VERSION 5.8 ;
BUSBITCHARS "[]" ;
DIVIDERCHAR "/" ;
UNITS
    DATABASE MICRONS 1000 ;
END UNITS

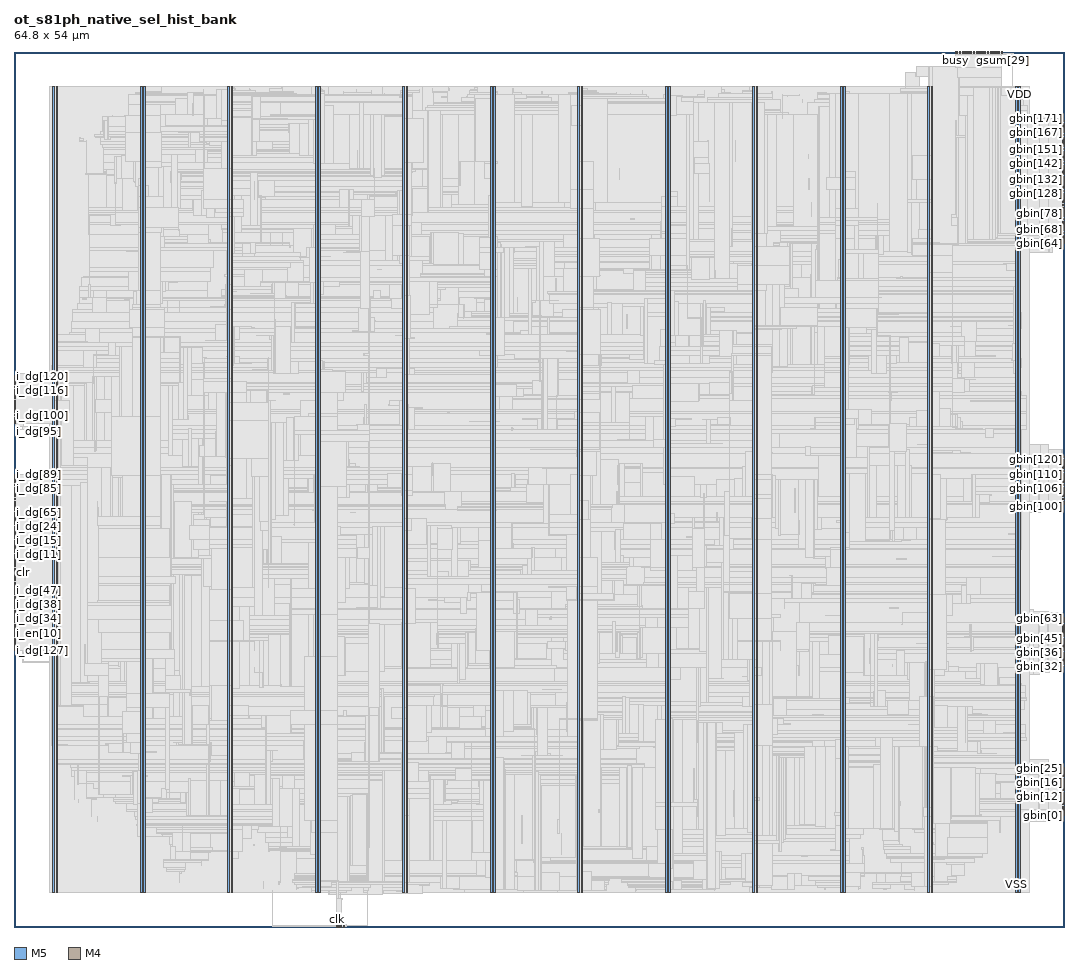
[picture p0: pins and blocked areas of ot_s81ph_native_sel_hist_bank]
MACRO ot_s81ph_native_sel_hist_bank
  FOREIGN ot_s81ph_native_sel_hist_bank 0 0 ;
  CLASS BLOCK ;
  SIZE 64.8 BY 54 ;
  PIN busy
    DIRECTION OUTPUT ;
    USE SIGNAL ;
    PORT
      LAYER M5 ;
        RECT  58.128 53.916 58.152 54 ;
    END
  END busy
  PIN clk
    DIRECTION INPUT ;
    USE SIGNAL ;
    PORT
      LAYER M5 ;
        RECT  19.92 0 19.944 0.084 ;
    END
  END clk
  PIN clr
    DIRECTION INPUT ;
    USE SIGNAL ;
    PORT
      LAYER M4 ;
        RECT  0 21.84 0.084 21.864 ;
    END
  END clr
  PIN gbin[0]
    DIRECTION OUTPUT ;
    USE SIGNAL ;
    PORT
      LAYER M4 ;
        RECT  64.716 6.864 64.8 6.888 ;
    END
  END gbin[0]
  PIN gbin[100]
    DIRECTION OUTPUT ;
    USE SIGNAL ;
    PORT
      LAYER M4 ;
        RECT  64.716 26.448 64.8 26.472 ;
    END
  END gbin[100]
  PIN gbin[101]
    DIRECTION OUTPUT ;
    USE SIGNAL ;
    PORT
      LAYER M4 ;
        RECT  64.716 26.544 64.8 26.568 ;
    END
  END gbin[101]
  PIN gbin[102]
    DIRECTION OUTPUT ;
    USE SIGNAL ;
    PORT
      LAYER M4 ;
        RECT  64.716 26.64 64.8 26.664 ;
    END
  END gbin[102]
  PIN gbin[103]
    DIRECTION OUTPUT ;
    USE SIGNAL ;
    PORT
      LAYER M4 ;
        RECT  64.716 26.736 64.8 26.76 ;
    END
  END gbin[103]
  PIN gbin[104]
    DIRECTION OUTPUT ;
    USE SIGNAL ;
    PORT
      LAYER M4 ;
        RECT  64.716 26.832 64.8 26.856 ;
    END
  END gbin[104]
  PIN gbin[105]
    DIRECTION OUTPUT ;
    USE SIGNAL ;
    PORT
      LAYER M4 ;
        RECT  64.716 26.928 64.8 26.952 ;
    END
  END gbin[105]
  PIN gbin[106]
    DIRECTION OUTPUT ;
    USE SIGNAL ;
    PORT
      LAYER M4 ;
        RECT  64.716 27.024 64.8 27.048 ;
    END
  END gbin[106]
  PIN gbin[107]
    DIRECTION OUTPUT ;
    USE SIGNAL ;
    PORT
      LAYER M4 ;
        RECT  64.716 27.12 64.8 27.144 ;
    END
  END gbin[107]
  PIN gbin[108]
    DIRECTION OUTPUT ;
    USE SIGNAL ;
    PORT
      LAYER M4 ;
        RECT  64.716 27.216 64.8 27.24 ;
    END
  END gbin[108]
  PIN gbin[109]
    DIRECTION OUTPUT ;
    USE SIGNAL ;
    PORT
      LAYER M4 ;
        RECT  64.716 27.312 64.8 27.336 ;
    END
  END gbin[109]
  PIN gbin[10]
    DIRECTION OUTPUT ;
    USE SIGNAL ;
    PORT
      LAYER M4 ;
        RECT  64.716 7.824 64.8 7.848 ;
    END
  END gbin[10]
  PIN gbin[110]
    DIRECTION OUTPUT ;
    USE SIGNAL ;
    PORT
      LAYER M4 ;
        RECT  64.716 27.408 64.8 27.432 ;
    END
  END gbin[110]
  PIN gbin[111]
    DIRECTION OUTPUT ;
    USE SIGNAL ;
    PORT
      LAYER M4 ;
        RECT  64.716 27.504 64.8 27.528 ;
    END
  END gbin[111]
  PIN gbin[112]
    DIRECTION OUTPUT ;
    USE SIGNAL ;
    PORT
      LAYER M4 ;
        RECT  64.716 27.6 64.8 27.624 ;
    END
  END gbin[112]
  PIN gbin[113]
    DIRECTION OUTPUT ;
    USE SIGNAL ;
    PORT
      LAYER M4 ;
        RECT  64.716 27.696 64.8 27.72 ;
    END
  END gbin[113]
  PIN gbin[114]
    DIRECTION OUTPUT ;
    USE SIGNAL ;
    PORT
      LAYER M4 ;
        RECT  64.716 27.792 64.8 27.816 ;
    END
  END gbin[114]
  PIN gbin[115]
    DIRECTION OUTPUT ;
    USE SIGNAL ;
    PORT
      LAYER M4 ;
        RECT  64.716 27.888 64.8 27.912 ;
    END
  END gbin[115]
  PIN gbin[116]
    DIRECTION OUTPUT ;
    USE SIGNAL ;
    PORT
      LAYER M4 ;
        RECT  64.716 27.984 64.8 28.008 ;
    END
  END gbin[116]
  PIN gbin[117]
    DIRECTION OUTPUT ;
    USE SIGNAL ;
    PORT
      LAYER M4 ;
        RECT  64.716 28.08 64.8 28.104 ;
    END
  END gbin[117]
  PIN gbin[118]
    DIRECTION OUTPUT ;
    USE SIGNAL ;
    PORT
      LAYER M4 ;
        RECT  64.716 28.176 64.8 28.2 ;
    END
  END gbin[118]
  PIN gbin[119]
    DIRECTION OUTPUT ;
    USE SIGNAL ;
    PORT
      LAYER M4 ;
        RECT  64.716 28.272 64.8 28.296 ;
    END
  END gbin[119]
  PIN gbin[11]
    DIRECTION OUTPUT ;
    USE SIGNAL ;
    PORT
      LAYER M4 ;
        RECT  64.716 7.92 64.8 7.944 ;
    END
  END gbin[11]
  PIN gbin[120]
    DIRECTION OUTPUT ;
    USE SIGNAL ;
    PORT
      LAYER M4 ;
        RECT  64.716 28.368 64.8 28.392 ;
    END
  END gbin[120]
  PIN gbin[121]
    DIRECTION OUTPUT ;
    USE SIGNAL ;
    PORT
      LAYER M4 ;
        RECT  64.716 28.464 64.8 28.488 ;
    END
  END gbin[121]
  PIN gbin[122]
    DIRECTION OUTPUT ;
    USE SIGNAL ;
    PORT
      LAYER M4 ;
        RECT  64.716 28.56 64.8 28.584 ;
    END
  END gbin[122]
  PIN gbin[123]
    DIRECTION OUTPUT ;
    USE SIGNAL ;
    PORT
      LAYER M4 ;
        RECT  64.716 28.656 64.8 28.68 ;
    END
  END gbin[123]
  PIN gbin[124]
    DIRECTION OUTPUT ;
    USE SIGNAL ;
    PORT
      LAYER M4 ;
        RECT  64.716 28.752 64.8 28.776 ;
    END
  END gbin[124]
  PIN gbin[125]
    DIRECTION OUTPUT ;
    USE SIGNAL ;
    PORT
      LAYER M4 ;
        RECT  64.716 28.848 64.8 28.872 ;
    END
  END gbin[125]
  PIN gbin[126]
    DIRECTION OUTPUT ;
    USE SIGNAL ;
    PORT
      LAYER M4 ;
        RECT  64.716 28.944 64.8 28.968 ;
    END
  END gbin[126]
  PIN gbin[127]
    DIRECTION OUTPUT ;
    USE SIGNAL ;
    PORT
      LAYER M4 ;
        RECT  64.716 29.04 64.8 29.064 ;
    END
  END gbin[127]
  PIN gbin[128]
    DIRECTION OUTPUT ;
    USE SIGNAL ;
    PORT
      LAYER M4 ;
        RECT  64.716 45.264 64.8 45.288 ;
    END
  END gbin[128]
  PIN gbin[129]
    DIRECTION OUTPUT ;
    USE SIGNAL ;
    PORT
      LAYER M4 ;
        RECT  64.716 45.36 64.8 45.384 ;
    END
  END gbin[129]
  PIN gbin[12]
    DIRECTION OUTPUT ;
    USE SIGNAL ;
    PORT
      LAYER M4 ;
        RECT  64.716 8.016 64.8 8.04 ;
    END
  END gbin[12]
  PIN gbin[130]
    DIRECTION OUTPUT ;
    USE SIGNAL ;
    PORT
      LAYER M4 ;
        RECT  64.716 45.456 64.8 45.48 ;
    END
  END gbin[130]
  PIN gbin[131]
    DIRECTION OUTPUT ;
    USE SIGNAL ;
    PORT
      LAYER M4 ;
        RECT  64.716 45.552 64.8 45.576 ;
    END
  END gbin[131]
  PIN gbin[132]
    DIRECTION OUTPUT ;
    USE SIGNAL ;
    PORT
      LAYER M4 ;
        RECT  64.716 45.648 64.8 45.672 ;
    END
  END gbin[132]
  PIN gbin[133]
    DIRECTION OUTPUT ;
    USE SIGNAL ;
    PORT
      LAYER M4 ;
        RECT  64.716 45.744 64.8 45.768 ;
    END
  END gbin[133]
  PIN gbin[134]
    DIRECTION OUTPUT ;
    USE SIGNAL ;
    PORT
      LAYER M4 ;
        RECT  64.716 45.84 64.8 45.864 ;
    END
  END gbin[134]
  PIN gbin[135]
    DIRECTION OUTPUT ;
    USE SIGNAL ;
    PORT
      LAYER M4 ;
        RECT  64.716 45.936 64.8 45.96 ;
    END
  END gbin[135]
  PIN gbin[136]
    DIRECTION OUTPUT ;
    USE SIGNAL ;
    PORT
      LAYER M4 ;
        RECT  64.716 46.032 64.8 46.056 ;
    END
  END gbin[136]
  PIN gbin[137]
    DIRECTION OUTPUT ;
    USE SIGNAL ;
    PORT
      LAYER M4 ;
        RECT  64.716 46.128 64.8 46.152 ;
    END
  END gbin[137]
  PIN gbin[138]
    DIRECTION OUTPUT ;
    USE SIGNAL ;
    PORT
      LAYER M4 ;
        RECT  64.716 46.224 64.8 46.248 ;
    END
  END gbin[138]
  PIN gbin[139]
    DIRECTION OUTPUT ;
    USE SIGNAL ;
    PORT
      LAYER M4 ;
        RECT  64.716 46.32 64.8 46.344 ;
    END
  END gbin[139]
  PIN gbin[13]
    DIRECTION OUTPUT ;
    USE SIGNAL ;
    PORT
      LAYER M4 ;
        RECT  64.716 8.112 64.8 8.136 ;
    END
  END gbin[13]
  PIN gbin[140]
    DIRECTION OUTPUT ;
    USE SIGNAL ;
    PORT
      LAYER M4 ;
        RECT  64.716 46.416 64.8 46.44 ;
    END
  END gbin[140]
  PIN gbin[141]
    DIRECTION OUTPUT ;
    USE SIGNAL ;
    PORT
      LAYER M4 ;
        RECT  64.716 46.512 64.8 46.536 ;
    END
  END gbin[141]
  PIN gbin[142]
    DIRECTION OUTPUT ;
    USE SIGNAL ;
    PORT
      LAYER M4 ;
        RECT  64.716 46.608 64.8 46.632 ;
    END
  END gbin[142]
  PIN gbin[143]
    DIRECTION OUTPUT ;
    USE SIGNAL ;
    PORT
      LAYER M4 ;
        RECT  64.716 46.704 64.8 46.728 ;
    END
  END gbin[143]
  PIN gbin[144]
    DIRECTION OUTPUT ;
    USE SIGNAL ;
    PORT
      LAYER M4 ;
        RECT  64.716 46.8 64.8 46.824 ;
    END
  END gbin[144]
  PIN gbin[145]
    DIRECTION OUTPUT ;
    USE SIGNAL ;
    PORT
      LAYER M4 ;
        RECT  64.716 46.896 64.8 46.92 ;
    END
  END gbin[145]
  PIN gbin[146]
    DIRECTION OUTPUT ;
    USE SIGNAL ;
    PORT
      LAYER M4 ;
        RECT  64.716 46.992 64.8 47.016 ;
    END
  END gbin[146]
  PIN gbin[147]
    DIRECTION OUTPUT ;
    USE SIGNAL ;
    PORT
      LAYER M4 ;
        RECT  64.716 47.088 64.8 47.112 ;
    END
  END gbin[147]
  PIN gbin[148]
    DIRECTION OUTPUT ;
    USE SIGNAL ;
    PORT
      LAYER M4 ;
        RECT  64.716 47.184 64.8 47.208 ;
    END
  END gbin[148]
  PIN gbin[149]
    DIRECTION OUTPUT ;
    USE SIGNAL ;
    PORT
      LAYER M4 ;
        RECT  64.716 47.28 64.8 47.304 ;
    END
  END gbin[149]
  PIN gbin[14]
    DIRECTION OUTPUT ;
    USE SIGNAL ;
    PORT
      LAYER M4 ;
        RECT  64.716 8.208 64.8 8.232 ;
    END
  END gbin[14]
  PIN gbin[150]
    DIRECTION OUTPUT ;
    USE SIGNAL ;
    PORT
      LAYER M4 ;
        RECT  64.716 47.376 64.8 47.4 ;
    END
  END gbin[150]
  PIN gbin[151]
    DIRECTION OUTPUT ;
    USE SIGNAL ;
    PORT
      LAYER M4 ;
        RECT  64.716 47.472 64.8 47.496 ;
    END
  END gbin[151]
  PIN gbin[152]
    DIRECTION OUTPUT ;
    USE SIGNAL ;
    PORT
      LAYER M4 ;
        RECT  64.716 47.568 64.8 47.592 ;
    END
  END gbin[152]
  PIN gbin[153]
    DIRECTION OUTPUT ;
    USE SIGNAL ;
    PORT
      LAYER M4 ;
        RECT  64.716 47.664 64.8 47.688 ;
    END
  END gbin[153]
  PIN gbin[154]
    DIRECTION OUTPUT ;
    USE SIGNAL ;
    PORT
      LAYER M4 ;
        RECT  64.716 47.76 64.8 47.784 ;
    END
  END gbin[154]
  PIN gbin[155]
    DIRECTION OUTPUT ;
    USE SIGNAL ;
    PORT
      LAYER M4 ;
        RECT  64.716 47.856 64.8 47.88 ;
    END
  END gbin[155]
  PIN gbin[156]
    DIRECTION OUTPUT ;
    USE SIGNAL ;
    PORT
      LAYER M4 ;
        RECT  64.716 47.952 64.8 47.976 ;
    END
  END gbin[156]
  PIN gbin[157]
    DIRECTION OUTPUT ;
    USE SIGNAL ;
    PORT
      LAYER M4 ;
        RECT  64.716 48.048 64.8 48.072 ;
    END
  END gbin[157]
  PIN gbin[158]
    DIRECTION OUTPUT ;
    USE SIGNAL ;
    PORT
      LAYER M4 ;
        RECT  64.716 48.144 64.8 48.168 ;
    END
  END gbin[158]
  PIN gbin[159]
    DIRECTION OUTPUT ;
    USE SIGNAL ;
    PORT
      LAYER M4 ;
        RECT  64.716 48.24 64.8 48.264 ;
    END
  END gbin[159]
  PIN gbin[15]
    DIRECTION OUTPUT ;
    USE SIGNAL ;
    PORT
      LAYER M4 ;
        RECT  64.716 8.304 64.8 8.328 ;
    END
  END gbin[15]
  PIN gbin[160]
    DIRECTION OUTPUT ;
    USE SIGNAL ;
    PORT
      LAYER M4 ;
        RECT  64.716 48.336 64.8 48.36 ;
    END
  END gbin[160]
  PIN gbin[161]
    DIRECTION OUTPUT ;
    USE SIGNAL ;
    PORT
      LAYER M4 ;
        RECT  64.716 48.432 64.8 48.456 ;
    END
  END gbin[161]
  PIN gbin[162]
    DIRECTION OUTPUT ;
    USE SIGNAL ;
    PORT
      LAYER M4 ;
        RECT  64.716 48.528 64.8 48.552 ;
    END
  END gbin[162]
  PIN gbin[163]
    DIRECTION OUTPUT ;
    USE SIGNAL ;
    PORT
      LAYER M4 ;
        RECT  64.716 48.624 64.8 48.648 ;
    END
  END gbin[163]
  PIN gbin[164]
    DIRECTION OUTPUT ;
    USE SIGNAL ;
    PORT
      LAYER M4 ;
        RECT  64.716 48.72 64.8 48.744 ;
    END
  END gbin[164]
  PIN gbin[165]
    DIRECTION OUTPUT ;
    USE SIGNAL ;
    PORT
      LAYER M4 ;
        RECT  64.716 48.816 64.8 48.84 ;
    END
  END gbin[165]
  PIN gbin[166]
    DIRECTION OUTPUT ;
    USE SIGNAL ;
    PORT
      LAYER M4 ;
        RECT  64.716 48.912 64.8 48.936 ;
    END
  END gbin[166]
  PIN gbin[167]
    DIRECTION OUTPUT ;
    USE SIGNAL ;
    PORT
      LAYER M4 ;
        RECT  64.716 49.008 64.8 49.032 ;
    END
  END gbin[167]
  PIN gbin[168]
    DIRECTION OUTPUT ;
    USE SIGNAL ;
    PORT
      LAYER M4 ;
        RECT  64.716 49.104 64.8 49.128 ;
    END
  END gbin[168]
  PIN gbin[169]
    DIRECTION OUTPUT ;
    USE SIGNAL ;
    PORT
      LAYER M4 ;
        RECT  64.716 49.2 64.8 49.224 ;
    END
  END gbin[169]
  PIN gbin[16]
    DIRECTION OUTPUT ;
    USE SIGNAL ;
    PORT
      LAYER M4 ;
        RECT  64.716 8.4 64.8 8.424 ;
    END
  END gbin[16]
  PIN gbin[170]
    DIRECTION OUTPUT ;
    USE SIGNAL ;
    PORT
      LAYER M4 ;
        RECT  64.716 49.296 64.8 49.32 ;
    END
  END gbin[170]
  PIN gbin[171]
    DIRECTION OUTPUT ;
    USE SIGNAL ;
    PORT
      LAYER M4 ;
        RECT  64.716 49.392 64.8 49.416 ;
    END
  END gbin[171]
  PIN gbin[172]
    DIRECTION OUTPUT ;
    USE SIGNAL ;
    PORT
      LAYER M4 ;
        RECT  64.716 49.488 64.8 49.512 ;
    END
  END gbin[172]
  PIN gbin[173]
    DIRECTION OUTPUT ;
    USE SIGNAL ;
    PORT
      LAYER M4 ;
        RECT  64.716 49.584 64.8 49.608 ;
    END
  END gbin[173]
  PIN gbin[174]
    DIRECTION OUTPUT ;
    USE SIGNAL ;
    PORT
      LAYER M4 ;
        RECT  64.716 49.68 64.8 49.704 ;
    END
  END gbin[174]
  PIN gbin[175]
    DIRECTION OUTPUT ;
    USE SIGNAL ;
    PORT
      LAYER M4 ;
        RECT  64.716 49.776 64.8 49.8 ;
    END
  END gbin[175]
  PIN gbin[17]
    DIRECTION OUTPUT ;
    USE SIGNAL ;
    PORT
      LAYER M4 ;
        RECT  64.716 8.496 64.8 8.52 ;
    END
  END gbin[17]
  PIN gbin[18]
    DIRECTION OUTPUT ;
    USE SIGNAL ;
    PORT
      LAYER M4 ;
        RECT  64.716 8.592 64.8 8.616 ;
    END
  END gbin[18]
  PIN gbin[19]
    DIRECTION OUTPUT ;
    USE SIGNAL ;
    PORT
      LAYER M4 ;
        RECT  64.716 8.688 64.8 8.712 ;
    END
  END gbin[19]
  PIN gbin[1]
    DIRECTION OUTPUT ;
    USE SIGNAL ;
    PORT
      LAYER M4 ;
        RECT  64.716 6.96 64.8 6.984 ;
    END
  END gbin[1]
  PIN gbin[20]
    DIRECTION OUTPUT ;
    USE SIGNAL ;
    PORT
      LAYER M4 ;
        RECT  64.716 8.784 64.8 8.808 ;
    END
  END gbin[20]
  PIN gbin[21]
    DIRECTION OUTPUT ;
    USE SIGNAL ;
    PORT
      LAYER M4 ;
        RECT  64.716 8.88 64.8 8.904 ;
    END
  END gbin[21]
  PIN gbin[22]
    DIRECTION OUTPUT ;
    USE SIGNAL ;
    PORT
      LAYER M4 ;
        RECT  64.716 8.976 64.8 9 ;
    END
  END gbin[22]
  PIN gbin[23]
    DIRECTION OUTPUT ;
    USE SIGNAL ;
    PORT
      LAYER M4 ;
        RECT  64.716 9.072 64.8 9.096 ;
    END
  END gbin[23]
  PIN gbin[24]
    DIRECTION OUTPUT ;
    USE SIGNAL ;
    PORT
      LAYER M4 ;
        RECT  64.716 9.168 64.8 9.192 ;
    END
  END gbin[24]
  PIN gbin[25]
    DIRECTION OUTPUT ;
    USE SIGNAL ;
    PORT
      LAYER M4 ;
        RECT  64.716 9.264 64.8 9.288 ;
    END
  END gbin[25]
  PIN gbin[26]
    DIRECTION OUTPUT ;
    USE SIGNAL ;
    PORT
      LAYER M4 ;
        RECT  64.716 9.36 64.8 9.384 ;
    END
  END gbin[26]
  PIN gbin[27]
    DIRECTION OUTPUT ;
    USE SIGNAL ;
    PORT
      LAYER M4 ;
        RECT  64.716 9.456 64.8 9.48 ;
    END
  END gbin[27]
  PIN gbin[28]
    DIRECTION OUTPUT ;
    USE SIGNAL ;
    PORT
      LAYER M4 ;
        RECT  64.716 9.552 64.8 9.576 ;
    END
  END gbin[28]
  PIN gbin[29]
    DIRECTION OUTPUT ;
    USE SIGNAL ;
    PORT
      LAYER M4 ;
        RECT  64.716 9.648 64.8 9.672 ;
    END
  END gbin[29]
  PIN gbin[2]
    DIRECTION OUTPUT ;
    USE SIGNAL ;
    PORT
      LAYER M4 ;
        RECT  64.716 7.056 64.8 7.08 ;
    END
  END gbin[2]
  PIN gbin[30]
    DIRECTION OUTPUT ;
    USE SIGNAL ;
    PORT
      LAYER M4 ;
        RECT  64.716 9.744 64.8 9.768 ;
    END
  END gbin[30]
  PIN gbin[31]
    DIRECTION OUTPUT ;
    USE SIGNAL ;
    PORT
      LAYER M4 ;
        RECT  64.716 9.84 64.8 9.864 ;
    END
  END gbin[31]
  PIN gbin[32]
    DIRECTION OUTPUT ;
    USE SIGNAL ;
    PORT
      LAYER M4 ;
        RECT  64.716 16.08 64.8 16.104 ;
    END
  END gbin[32]
  PIN gbin[33]
    DIRECTION OUTPUT ;
    USE SIGNAL ;
    PORT
      LAYER M4 ;
        RECT  64.716 16.176 64.8 16.2 ;
    END
  END gbin[33]
  PIN gbin[34]
    DIRECTION OUTPUT ;
    USE SIGNAL ;
    PORT
      LAYER M4 ;
        RECT  64.716 16.272 64.8 16.296 ;
    END
  END gbin[34]
  PIN gbin[35]
    DIRECTION OUTPUT ;
    USE SIGNAL ;
    PORT
      LAYER M4 ;
        RECT  64.716 16.368 64.8 16.392 ;
    END
  END gbin[35]
  PIN gbin[36]
    DIRECTION OUTPUT ;
    USE SIGNAL ;
    PORT
      LAYER M4 ;
        RECT  64.716 16.464 64.8 16.488 ;
    END
  END gbin[36]
  PIN gbin[37]
    DIRECTION OUTPUT ;
    USE SIGNAL ;
    PORT
      LAYER M4 ;
        RECT  64.716 16.56 64.8 16.584 ;
    END
  END gbin[37]
  PIN gbin[38]
    DIRECTION OUTPUT ;
    USE SIGNAL ;
    PORT
      LAYER M4 ;
        RECT  64.716 16.656 64.8 16.68 ;
    END
  END gbin[38]
  PIN gbin[39]
    DIRECTION OUTPUT ;
    USE SIGNAL ;
    PORT
      LAYER M4 ;
        RECT  64.716 16.752 64.8 16.776 ;
    END
  END gbin[39]
  PIN gbin[3]
    DIRECTION OUTPUT ;
    USE SIGNAL ;
    PORT
      LAYER M4 ;
        RECT  64.716 7.152 64.8 7.176 ;
    END
  END gbin[3]
  PIN gbin[40]
    DIRECTION OUTPUT ;
    USE SIGNAL ;
    PORT
      LAYER M4 ;
        RECT  64.716 16.848 64.8 16.872 ;
    END
  END gbin[40]
  PIN gbin[41]
    DIRECTION OUTPUT ;
    USE SIGNAL ;
    PORT
      LAYER M4 ;
        RECT  64.716 16.944 64.8 16.968 ;
    END
  END gbin[41]
  PIN gbin[42]
    DIRECTION OUTPUT ;
    USE SIGNAL ;
    PORT
      LAYER M4 ;
        RECT  64.716 17.04 64.8 17.064 ;
    END
  END gbin[42]
  PIN gbin[43]
    DIRECTION OUTPUT ;
    USE SIGNAL ;
    PORT
      LAYER M4 ;
        RECT  64.716 17.136 64.8 17.16 ;
    END
  END gbin[43]
  PIN gbin[44]
    DIRECTION OUTPUT ;
    USE SIGNAL ;
    PORT
      LAYER M4 ;
        RECT  64.716 17.232 64.8 17.256 ;
    END
  END gbin[44]
  PIN gbin[45]
    DIRECTION OUTPUT ;
    USE SIGNAL ;
    PORT
      LAYER M4 ;
        RECT  64.716 17.328 64.8 17.352 ;
    END
  END gbin[45]
  PIN gbin[46]
    DIRECTION OUTPUT ;
    USE SIGNAL ;
    PORT
      LAYER M4 ;
        RECT  64.716 17.424 64.8 17.448 ;
    END
  END gbin[46]
  PIN gbin[47]
    DIRECTION OUTPUT ;
    USE SIGNAL ;
    PORT
      LAYER M4 ;
        RECT  64.716 17.52 64.8 17.544 ;
    END
  END gbin[47]
  PIN gbin[48]
    DIRECTION OUTPUT ;
    USE SIGNAL ;
    PORT
      LAYER M4 ;
        RECT  64.716 17.616 64.8 17.64 ;
    END
  END gbin[48]
  PIN gbin[49]
    DIRECTION OUTPUT ;
    USE SIGNAL ;
    PORT
      LAYER M4 ;
        RECT  64.716 17.712 64.8 17.736 ;
    END
  END gbin[49]
  PIN gbin[4]
    DIRECTION OUTPUT ;
    USE SIGNAL ;
    PORT
      LAYER M4 ;
        RECT  64.716 7.248 64.8 7.272 ;
    END
  END gbin[4]
  PIN gbin[50]
    DIRECTION OUTPUT ;
    USE SIGNAL ;
    PORT
      LAYER M4 ;
        RECT  64.716 17.808 64.8 17.832 ;
    END
  END gbin[50]
  PIN gbin[51]
    DIRECTION OUTPUT ;
    USE SIGNAL ;
    PORT
      LAYER M4 ;
        RECT  64.716 17.904 64.8 17.928 ;
    END
  END gbin[51]
  PIN gbin[52]
    DIRECTION OUTPUT ;
    USE SIGNAL ;
    PORT
      LAYER M4 ;
        RECT  64.716 18 64.8 18.024 ;
    END
  END gbin[52]
  PIN gbin[53]
    DIRECTION OUTPUT ;
    USE SIGNAL ;
    PORT
      LAYER M4 ;
        RECT  64.716 18.096 64.8 18.12 ;
    END
  END gbin[53]
  PIN gbin[54]
    DIRECTION OUTPUT ;
    USE SIGNAL ;
    PORT
      LAYER M4 ;
        RECT  64.716 18.192 64.8 18.216 ;
    END
  END gbin[54]
  PIN gbin[55]
    DIRECTION OUTPUT ;
    USE SIGNAL ;
    PORT
      LAYER M4 ;
        RECT  64.716 18.288 64.8 18.312 ;
    END
  END gbin[55]
  PIN gbin[56]
    DIRECTION OUTPUT ;
    USE SIGNAL ;
    PORT
      LAYER M4 ;
        RECT  64.716 18.384 64.8 18.408 ;
    END
  END gbin[56]
  PIN gbin[57]
    DIRECTION OUTPUT ;
    USE SIGNAL ;
    PORT
      LAYER M4 ;
        RECT  64.716 18.48 64.8 18.504 ;
    END
  END gbin[57]
  PIN gbin[58]
    DIRECTION OUTPUT ;
    USE SIGNAL ;
    PORT
      LAYER M4 ;
        RECT  64.716 18.576 64.8 18.6 ;
    END
  END gbin[58]
  PIN gbin[59]
    DIRECTION OUTPUT ;
    USE SIGNAL ;
    PORT
      LAYER M4 ;
        RECT  64.716 18.672 64.8 18.696 ;
    END
  END gbin[59]
  PIN gbin[5]
    DIRECTION OUTPUT ;
    USE SIGNAL ;
    PORT
      LAYER M4 ;
        RECT  64.716 7.344 64.8 7.368 ;
    END
  END gbin[5]
  PIN gbin[60]
    DIRECTION OUTPUT ;
    USE SIGNAL ;
    PORT
      LAYER M4 ;
        RECT  64.716 18.768 64.8 18.792 ;
    END
  END gbin[60]
  PIN gbin[61]
    DIRECTION OUTPUT ;
    USE SIGNAL ;
    PORT
      LAYER M4 ;
        RECT  64.716 18.864 64.8 18.888 ;
    END
  END gbin[61]
  PIN gbin[62]
    DIRECTION OUTPUT ;
    USE SIGNAL ;
    PORT
      LAYER M4 ;
        RECT  64.716 18.96 64.8 18.984 ;
    END
  END gbin[62]
  PIN gbin[63]
    DIRECTION OUTPUT ;
    USE SIGNAL ;
    PORT
      LAYER M4 ;
        RECT  64.716 19.056 64.8 19.08 ;
    END
  END gbin[63]
  PIN gbin[64]
    DIRECTION OUTPUT ;
    USE SIGNAL ;
    PORT
      LAYER M4 ;
        RECT  64.716 42.192 64.8 42.216 ;
    END
  END gbin[64]
  PIN gbin[65]
    DIRECTION OUTPUT ;
    USE SIGNAL ;
    PORT
      LAYER M4 ;
        RECT  64.716 42.288 64.8 42.312 ;
    END
  END gbin[65]
  PIN gbin[66]
    DIRECTION OUTPUT ;
    USE SIGNAL ;
    PORT
      LAYER M4 ;
        RECT  64.716 42.384 64.8 42.408 ;
    END
  END gbin[66]
  PIN gbin[67]
    DIRECTION OUTPUT ;
    USE SIGNAL ;
    PORT
      LAYER M4 ;
        RECT  64.716 42.48 64.8 42.504 ;
    END
  END gbin[67]
  PIN gbin[68]
    DIRECTION OUTPUT ;
    USE SIGNAL ;
    PORT
      LAYER M4 ;
        RECT  64.716 42.576 64.8 42.6 ;
    END
  END gbin[68]
  PIN gbin[69]
    DIRECTION OUTPUT ;
    USE SIGNAL ;
    PORT
      LAYER M4 ;
        RECT  64.716 42.672 64.8 42.696 ;
    END
  END gbin[69]
  PIN gbin[6]
    DIRECTION OUTPUT ;
    USE SIGNAL ;
    PORT
      LAYER M4 ;
        RECT  64.716 7.44 64.8 7.464 ;
    END
  END gbin[6]
  PIN gbin[70]
    DIRECTION OUTPUT ;
    USE SIGNAL ;
    PORT
      LAYER M4 ;
        RECT  64.716 42.768 64.8 42.792 ;
    END
  END gbin[70]
  PIN gbin[71]
    DIRECTION OUTPUT ;
    USE SIGNAL ;
    PORT
      LAYER M4 ;
        RECT  64.716 42.864 64.8 42.888 ;
    END
  END gbin[71]
  PIN gbin[72]
    DIRECTION OUTPUT ;
    USE SIGNAL ;
    PORT
      LAYER M4 ;
        RECT  64.716 42.96 64.8 42.984 ;
    END
  END gbin[72]
  PIN gbin[73]
    DIRECTION OUTPUT ;
    USE SIGNAL ;
    PORT
      LAYER M4 ;
        RECT  64.716 43.056 64.8 43.08 ;
    END
  END gbin[73]
  PIN gbin[74]
    DIRECTION OUTPUT ;
    USE SIGNAL ;
    PORT
      LAYER M4 ;
        RECT  64.716 43.152 64.8 43.176 ;
    END
  END gbin[74]
  PIN gbin[75]
    DIRECTION OUTPUT ;
    USE SIGNAL ;
    PORT
      LAYER M4 ;
        RECT  64.716 43.248 64.8 43.272 ;
    END
  END gbin[75]
  PIN gbin[76]
    DIRECTION OUTPUT ;
    USE SIGNAL ;
    PORT
      LAYER M4 ;
        RECT  64.716 43.344 64.8 43.368 ;
    END
  END gbin[76]
  PIN gbin[77]
    DIRECTION OUTPUT ;
    USE SIGNAL ;
    PORT
      LAYER M4 ;
        RECT  64.716 43.44 64.8 43.464 ;
    END
  END gbin[77]
  PIN gbin[78]
    DIRECTION OUTPUT ;
    USE SIGNAL ;
    PORT
      LAYER M4 ;
        RECT  64.716 43.536 64.8 43.56 ;
    END
  END gbin[78]
  PIN gbin[79]
    DIRECTION OUTPUT ;
    USE SIGNAL ;
    PORT
      LAYER M4 ;
        RECT  64.716 43.632 64.8 43.656 ;
    END
  END gbin[79]
  PIN gbin[7]
    DIRECTION OUTPUT ;
    USE SIGNAL ;
    PORT
      LAYER M4 ;
        RECT  64.716 7.536 64.8 7.56 ;
    END
  END gbin[7]
  PIN gbin[80]
    DIRECTION OUTPUT ;
    USE SIGNAL ;
    PORT
      LAYER M4 ;
        RECT  64.716 43.728 64.8 43.752 ;
    END
  END gbin[80]
  PIN gbin[81]
    DIRECTION OUTPUT ;
    USE SIGNAL ;
    PORT
      LAYER M4 ;
        RECT  64.716 43.824 64.8 43.848 ;
    END
  END gbin[81]
  PIN gbin[82]
    DIRECTION OUTPUT ;
    USE SIGNAL ;
    PORT
      LAYER M4 ;
        RECT  64.716 43.92 64.8 43.944 ;
    END
  END gbin[82]
  PIN gbin[83]
    DIRECTION OUTPUT ;
    USE SIGNAL ;
    PORT
      LAYER M4 ;
        RECT  64.716 44.016 64.8 44.04 ;
    END
  END gbin[83]
  PIN gbin[84]
    DIRECTION OUTPUT ;
    USE SIGNAL ;
    PORT
      LAYER M4 ;
        RECT  64.716 44.112 64.8 44.136 ;
    END
  END gbin[84]
  PIN gbin[85]
    DIRECTION OUTPUT ;
    USE SIGNAL ;
    PORT
      LAYER M4 ;
        RECT  64.716 44.208 64.8 44.232 ;
    END
  END gbin[85]
  PIN gbin[86]
    DIRECTION OUTPUT ;
    USE SIGNAL ;
    PORT
      LAYER M4 ;
        RECT  64.716 44.304 64.8 44.328 ;
    END
  END gbin[86]
  PIN gbin[87]
    DIRECTION OUTPUT ;
    USE SIGNAL ;
    PORT
      LAYER M4 ;
        RECT  64.716 44.4 64.8 44.424 ;
    END
  END gbin[87]
  PIN gbin[88]
    DIRECTION OUTPUT ;
    USE SIGNAL ;
    PORT
      LAYER M4 ;
        RECT  64.716 44.496 64.8 44.52 ;
    END
  END gbin[88]
  PIN gbin[89]
    DIRECTION OUTPUT ;
    USE SIGNAL ;
    PORT
      LAYER M4 ;
        RECT  64.716 44.592 64.8 44.616 ;
    END
  END gbin[89]
  PIN gbin[8]
    DIRECTION OUTPUT ;
    USE SIGNAL ;
    PORT
      LAYER M4 ;
        RECT  64.716 7.632 64.8 7.656 ;
    END
  END gbin[8]
  PIN gbin[90]
    DIRECTION OUTPUT ;
    USE SIGNAL ;
    PORT
      LAYER M4 ;
        RECT  64.716 44.688 64.8 44.712 ;
    END
  END gbin[90]
  PIN gbin[91]
    DIRECTION OUTPUT ;
    USE SIGNAL ;
    PORT
      LAYER M4 ;
        RECT  64.716 44.784 64.8 44.808 ;
    END
  END gbin[91]
  PIN gbin[92]
    DIRECTION OUTPUT ;
    USE SIGNAL ;
    PORT
      LAYER M4 ;
        RECT  64.716 44.88 64.8 44.904 ;
    END
  END gbin[92]
  PIN gbin[93]
    DIRECTION OUTPUT ;
    USE SIGNAL ;
    PORT
      LAYER M4 ;
        RECT  64.716 44.976 64.8 45 ;
    END
  END gbin[93]
  PIN gbin[94]
    DIRECTION OUTPUT ;
    USE SIGNAL ;
    PORT
      LAYER M4 ;
        RECT  64.716 45.072 64.8 45.096 ;
    END
  END gbin[94]
  PIN gbin[95]
    DIRECTION OUTPUT ;
    USE SIGNAL ;
    PORT
      LAYER M4 ;
        RECT  64.716 45.168 64.8 45.192 ;
    END
  END gbin[95]
  PIN gbin[96]
    DIRECTION OUTPUT ;
    USE SIGNAL ;
    PORT
      LAYER M4 ;
        RECT  64.716 26.064 64.8 26.088 ;
    END
  END gbin[96]
  PIN gbin[97]
    DIRECTION OUTPUT ;
    USE SIGNAL ;
    PORT
      LAYER M4 ;
        RECT  64.716 26.16 64.8 26.184 ;
    END
  END gbin[97]
  PIN gbin[98]
    DIRECTION OUTPUT ;
    USE SIGNAL ;
    PORT
      LAYER M4 ;
        RECT  64.716 26.256 64.8 26.28 ;
    END
  END gbin[98]
  PIN gbin[99]
    DIRECTION OUTPUT ;
    USE SIGNAL ;
    PORT
      LAYER M4 ;
        RECT  64.716 26.352 64.8 26.376 ;
    END
  END gbin[99]
  PIN gbin[9]
    DIRECTION OUTPUT ;
    USE SIGNAL ;
    PORT
      LAYER M4 ;
        RECT  64.716 7.728 64.8 7.752 ;
    END
  END gbin[9]
  PIN gsel[0]
    DIRECTION INPUT ;
    USE SIGNAL ;
    PORT
      LAYER M5 ;
        RECT  20.016 0 20.04 0.084 ;
    END
  END gsel[0]
  PIN gsel[1]
    DIRECTION INPUT ;
    USE SIGNAL ;
    PORT
      LAYER M5 ;
        RECT  20.112 0 20.136 0.084 ;
    END
  END gsel[1]
  PIN gsel[2]
    DIRECTION INPUT ;
    USE SIGNAL ;
    PORT
      LAYER M5 ;
        RECT  20.208 0 20.232 0.084 ;
    END
  END gsel[2]
  PIN gsel[3]
    DIRECTION INPUT ;
    USE SIGNAL ;
    PORT
      LAYER M5 ;
        RECT  20.304 0 20.328 0.084 ;
    END
  END gsel[3]
  PIN gsum[0]
    DIRECTION OUTPUT ;
    USE SIGNAL ;
    PORT
      LAYER M5 ;
        RECT  58.224 53.916 58.248 54 ;
    END
  END gsum[0]
  PIN gsum[10]
    DIRECTION OUTPUT ;
    USE SIGNAL ;
    PORT
      LAYER M5 ;
        RECT  59.184 53.916 59.208 54 ;
    END
  END gsum[10]
  PIN gsum[11]
    DIRECTION OUTPUT ;
    USE SIGNAL ;
    PORT
      LAYER M5 ;
        RECT  59.28 53.916 59.304 54 ;
    END
  END gsum[11]
  PIN gsum[12]
    DIRECTION OUTPUT ;
    USE SIGNAL ;
    PORT
      LAYER M5 ;
        RECT  59.376 53.916 59.4 54 ;
    END
  END gsum[12]
  PIN gsum[13]
    DIRECTION OUTPUT ;
    USE SIGNAL ;
    PORT
      LAYER M5 ;
        RECT  59.472 53.916 59.496 54 ;
    END
  END gsum[13]
  PIN gsum[14]
    DIRECTION OUTPUT ;
    USE SIGNAL ;
    PORT
      LAYER M5 ;
        RECT  59.568 53.916 59.592 54 ;
    END
  END gsum[14]
  PIN gsum[15]
    DIRECTION OUTPUT ;
    USE SIGNAL ;
    PORT
      LAYER M5 ;
        RECT  59.664 53.916 59.688 54 ;
    END
  END gsum[15]
  PIN gsum[16]
    DIRECTION OUTPUT ;
    USE SIGNAL ;
    PORT
      LAYER M5 ;
        RECT  59.76 53.916 59.784 54 ;
    END
  END gsum[16]
  PIN gsum[17]
    DIRECTION OUTPUT ;
    USE SIGNAL ;
    PORT
      LAYER M5 ;
        RECT  59.856 53.916 59.88 54 ;
    END
  END gsum[17]
  PIN gsum[18]
    DIRECTION OUTPUT ;
    USE SIGNAL ;
    PORT
      LAYER M5 ;
        RECT  59.952 53.916 59.976 54 ;
    END
  END gsum[18]
  PIN gsum[19]
    DIRECTION OUTPUT ;
    USE SIGNAL ;
    PORT
      LAYER M5 ;
        RECT  60.048 53.916 60.072 54 ;
    END
  END gsum[19]
  PIN gsum[1]
    DIRECTION OUTPUT ;
    USE SIGNAL ;
    PORT
      LAYER M5 ;
        RECT  58.32 53.916 58.344 54 ;
    END
  END gsum[1]
  PIN gsum[20]
    DIRECTION OUTPUT ;
    USE SIGNAL ;
    PORT
      LAYER M5 ;
        RECT  60.144 53.916 60.168 54 ;
    END
  END gsum[20]
  PIN gsum[21]
    DIRECTION OUTPUT ;
    USE SIGNAL ;
    PORT
      LAYER M5 ;
        RECT  60.24 53.916 60.264 54 ;
    END
  END gsum[21]
  PIN gsum[22]
    DIRECTION OUTPUT ;
    USE SIGNAL ;
    PORT
      LAYER M5 ;
        RECT  60.336 53.916 60.36 54 ;
    END
  END gsum[22]
  PIN gsum[23]
    DIRECTION OUTPUT ;
    USE SIGNAL ;
    PORT
      LAYER M5 ;
        RECT  60.432 53.916 60.456 54 ;
    END
  END gsum[23]
  PIN gsum[24]
    DIRECTION OUTPUT ;
    USE SIGNAL ;
    PORT
      LAYER M5 ;
        RECT  60.528 53.916 60.552 54 ;
    END
  END gsum[24]
  PIN gsum[25]
    DIRECTION OUTPUT ;
    USE SIGNAL ;
    PORT
      LAYER M5 ;
        RECT  60.624 53.916 60.648 54 ;
    END
  END gsum[25]
  PIN gsum[26]
    DIRECTION OUTPUT ;
    USE SIGNAL ;
    PORT
      LAYER M5 ;
        RECT  60.72 53.916 60.744 54 ;
    END
  END gsum[26]
  PIN gsum[27]
    DIRECTION OUTPUT ;
    USE SIGNAL ;
    PORT
      LAYER M5 ;
        RECT  60.816 53.916 60.84 54 ;
    END
  END gsum[27]
  PIN gsum[28]
    DIRECTION OUTPUT ;
    USE SIGNAL ;
    PORT
      LAYER M5 ;
        RECT  60.912 53.916 60.936 54 ;
    END
  END gsum[28]
  PIN gsum[29]
    DIRECTION OUTPUT ;
    USE SIGNAL ;
    PORT
      LAYER M5 ;
        RECT  61.008 53.916 61.032 54 ;
    END
  END gsum[29]
  PIN gsum[2]
    DIRECTION OUTPUT ;
    USE SIGNAL ;
    PORT
      LAYER M5 ;
        RECT  58.416 53.916 58.44 54 ;
    END
  END gsum[2]
  PIN gsum[3]
    DIRECTION OUTPUT ;
    USE SIGNAL ;
    PORT
      LAYER M5 ;
        RECT  58.512 53.916 58.536 54 ;
    END
  END gsum[3]
  PIN gsum[4]
    DIRECTION OUTPUT ;
    USE SIGNAL ;
    PORT
      LAYER M5 ;
        RECT  58.608 53.916 58.632 54 ;
    END
  END gsum[4]
  PIN gsum[5]
    DIRECTION OUTPUT ;
    USE SIGNAL ;
    PORT
      LAYER M5 ;
        RECT  58.704 53.916 58.728 54 ;
    END
  END gsum[5]
  PIN gsum[6]
    DIRECTION OUTPUT ;
    USE SIGNAL ;
    PORT
      LAYER M5 ;
        RECT  58.8 53.916 58.824 54 ;
    END
  END gsum[6]
  PIN gsum[7]
    DIRECTION OUTPUT ;
    USE SIGNAL ;
    PORT
      LAYER M5 ;
        RECT  58.896 53.916 58.92 54 ;
    END
  END gsum[7]
  PIN gsum[8]
    DIRECTION OUTPUT ;
    USE SIGNAL ;
    PORT
      LAYER M5 ;
        RECT  58.992 53.916 59.016 54 ;
    END
  END gsum[8]
  PIN gsum[9]
    DIRECTION OUTPUT ;
    USE SIGNAL ;
    PORT
      LAYER M5 ;
        RECT  59.088 53.916 59.112 54 ;
    END
  END gsum[9]
  PIN i_dg[0]
    DIRECTION INPUT ;
    USE SIGNAL ;
    PORT
      LAYER M4 ;
        RECT  0 21.936 0.084 21.96 ;
    END
  END i_dg[0]
  PIN i_dg[100]
    DIRECTION INPUT ;
    USE SIGNAL ;
    PORT
      LAYER M4 ;
        RECT  0 31.536 0.084 31.56 ;
    END
  END i_dg[100]
  PIN i_dg[101]
    DIRECTION INPUT ;
    USE SIGNAL ;
    PORT
      LAYER M4 ;
        RECT  0 31.632 0.084 31.656 ;
    END
  END i_dg[101]
  PIN i_dg[102]
    DIRECTION INPUT ;
    USE SIGNAL ;
    PORT
      LAYER M4 ;
        RECT  0 31.728 0.084 31.752 ;
    END
  END i_dg[102]
  PIN i_dg[103]
    DIRECTION INPUT ;
    USE SIGNAL ;
    PORT
      LAYER M4 ;
        RECT  0 31.824 0.084 31.848 ;
    END
  END i_dg[103]
  PIN i_dg[104]
    DIRECTION INPUT ;
    USE SIGNAL ;
    PORT
      LAYER M4 ;
        RECT  0 31.92 0.084 31.944 ;
    END
  END i_dg[104]
  PIN i_dg[105]
    DIRECTION INPUT ;
    USE SIGNAL ;
    PORT
      LAYER M4 ;
        RECT  0 32.016 0.084 32.04 ;
    END
  END i_dg[105]
  PIN i_dg[106]
    DIRECTION INPUT ;
    USE SIGNAL ;
    PORT
      LAYER M4 ;
        RECT  0 32.112 0.084 32.136 ;
    END
  END i_dg[106]
  PIN i_dg[107]
    DIRECTION INPUT ;
    USE SIGNAL ;
    PORT
      LAYER M4 ;
        RECT  0 32.208 0.084 32.232 ;
    END
  END i_dg[107]
  PIN i_dg[108]
    DIRECTION INPUT ;
    USE SIGNAL ;
    PORT
      LAYER M4 ;
        RECT  0 32.304 0.084 32.328 ;
    END
  END i_dg[108]
  PIN i_dg[109]
    DIRECTION INPUT ;
    USE SIGNAL ;
    PORT
      LAYER M4 ;
        RECT  0 32.4 0.084 32.424 ;
    END
  END i_dg[109]
  PIN i_dg[10]
    DIRECTION INPUT ;
    USE SIGNAL ;
    PORT
      LAYER M4 ;
        RECT  0 22.896 0.084 22.92 ;
    END
  END i_dg[10]
  PIN i_dg[110]
    DIRECTION INPUT ;
    USE SIGNAL ;
    PORT
      LAYER M4 ;
        RECT  0 32.496 0.084 32.52 ;
    END
  END i_dg[110]
  PIN i_dg[111]
    DIRECTION INPUT ;
    USE SIGNAL ;
    PORT
      LAYER M4 ;
        RECT  0 32.592 0.084 32.616 ;
    END
  END i_dg[111]
  PIN i_dg[112]
    DIRECTION INPUT ;
    USE SIGNAL ;
    PORT
      LAYER M4 ;
        RECT  0 32.688 0.084 32.712 ;
    END
  END i_dg[112]
  PIN i_dg[113]
    DIRECTION INPUT ;
    USE SIGNAL ;
    PORT
      LAYER M4 ;
        RECT  0 32.784 0.084 32.808 ;
    END
  END i_dg[113]
  PIN i_dg[114]
    DIRECTION INPUT ;
    USE SIGNAL ;
    PORT
      LAYER M4 ;
        RECT  0 32.88 0.084 32.904 ;
    END
  END i_dg[114]
  PIN i_dg[115]
    DIRECTION INPUT ;
    USE SIGNAL ;
    PORT
      LAYER M4 ;
        RECT  0 32.976 0.084 33 ;
    END
  END i_dg[115]
  PIN i_dg[116]
    DIRECTION INPUT ;
    USE SIGNAL ;
    PORT
      LAYER M4 ;
        RECT  0 33.072 0.084 33.096 ;
    END
  END i_dg[116]
  PIN i_dg[117]
    DIRECTION INPUT ;
    USE SIGNAL ;
    PORT
      LAYER M4 ;
        RECT  0 33.168 0.084 33.192 ;
    END
  END i_dg[117]
  PIN i_dg[118]
    DIRECTION INPUT ;
    USE SIGNAL ;
    PORT
      LAYER M4 ;
        RECT  0 33.264 0.084 33.288 ;
    END
  END i_dg[118]
  PIN i_dg[119]
    DIRECTION INPUT ;
    USE SIGNAL ;
    PORT
      LAYER M4 ;
        RECT  0 33.36 0.084 33.384 ;
    END
  END i_dg[119]
  PIN i_dg[11]
    DIRECTION INPUT ;
    USE SIGNAL ;
    PORT
      LAYER M4 ;
        RECT  0 22.992 0.084 23.016 ;
    END
  END i_dg[11]
  PIN i_dg[120]
    DIRECTION INPUT ;
    USE SIGNAL ;
    PORT
      LAYER M4 ;
        RECT  0 33.456 0.084 33.48 ;
    END
  END i_dg[120]
  PIN i_dg[121]
    DIRECTION INPUT ;
    USE SIGNAL ;
    PORT
      LAYER M4 ;
        RECT  0 33.552 0.084 33.576 ;
    END
  END i_dg[121]
  PIN i_dg[122]
    DIRECTION INPUT ;
    USE SIGNAL ;
    PORT
      LAYER M4 ;
        RECT  0 33.648 0.084 33.672 ;
    END
  END i_dg[122]
  PIN i_dg[123]
    DIRECTION INPUT ;
    USE SIGNAL ;
    PORT
      LAYER M4 ;
        RECT  0 33.744 0.084 33.768 ;
    END
  END i_dg[123]
  PIN i_dg[124]
    DIRECTION INPUT ;
    USE SIGNAL ;
    PORT
      LAYER M4 ;
        RECT  0 33.84 0.084 33.864 ;
    END
  END i_dg[124]
  PIN i_dg[125]
    DIRECTION INPUT ;
    USE SIGNAL ;
    PORT
      LAYER M4 ;
        RECT  0 33.936 0.084 33.96 ;
    END
  END i_dg[125]
  PIN i_dg[126]
    DIRECTION INPUT ;
    USE SIGNAL ;
    PORT
      LAYER M4 ;
        RECT  0 34.032 0.084 34.056 ;
    END
  END i_dg[126]
  PIN i_dg[127]
    DIRECTION INPUT ;
    USE SIGNAL ;
    PORT
      LAYER M4 ;
        RECT  0 17.04 0.084 17.064 ;
    END
  END i_dg[127]
  PIN i_dg[12]
    DIRECTION INPUT ;
    USE SIGNAL ;
    PORT
      LAYER M4 ;
        RECT  0 23.088 0.084 23.112 ;
    END
  END i_dg[12]
  PIN i_dg[13]
    DIRECTION INPUT ;
    USE SIGNAL ;
    PORT
      LAYER M4 ;
        RECT  0 23.184 0.084 23.208 ;
    END
  END i_dg[13]
  PIN i_dg[14]
    DIRECTION INPUT ;
    USE SIGNAL ;
    PORT
      LAYER M4 ;
        RECT  0 23.28 0.084 23.304 ;
    END
  END i_dg[14]
  PIN i_dg[15]
    DIRECTION INPUT ;
    USE SIGNAL ;
    PORT
      LAYER M4 ;
        RECT  0 23.376 0.084 23.4 ;
    END
  END i_dg[15]
  PIN i_dg[16]
    DIRECTION INPUT ;
    USE SIGNAL ;
    PORT
      LAYER M4 ;
        RECT  0 23.472 0.084 23.496 ;
    END
  END i_dg[16]
  PIN i_dg[17]
    DIRECTION INPUT ;
    USE SIGNAL ;
    PORT
      LAYER M4 ;
        RECT  0 23.568 0.084 23.592 ;
    END
  END i_dg[17]
  PIN i_dg[18]
    DIRECTION INPUT ;
    USE SIGNAL ;
    PORT
      LAYER M4 ;
        RECT  0 23.664 0.084 23.688 ;
    END
  END i_dg[18]
  PIN i_dg[19]
    DIRECTION INPUT ;
    USE SIGNAL ;
    PORT
      LAYER M4 ;
        RECT  0 23.76 0.084 23.784 ;
    END
  END i_dg[19]
  PIN i_dg[1]
    DIRECTION INPUT ;
    USE SIGNAL ;
    PORT
      LAYER M4 ;
        RECT  0 22.032 0.084 22.056 ;
    END
  END i_dg[1]
  PIN i_dg[20]
    DIRECTION INPUT ;
    USE SIGNAL ;
    PORT
      LAYER M4 ;
        RECT  0 23.856 0.084 23.88 ;
    END
  END i_dg[20]
  PIN i_dg[21]
    DIRECTION INPUT ;
    USE SIGNAL ;
    PORT
      LAYER M4 ;
        RECT  0 23.952 0.084 23.976 ;
    END
  END i_dg[21]
  PIN i_dg[22]
    DIRECTION INPUT ;
    USE SIGNAL ;
    PORT
      LAYER M4 ;
        RECT  0 24.048 0.084 24.072 ;
    END
  END i_dg[22]
  PIN i_dg[23]
    DIRECTION INPUT ;
    USE SIGNAL ;
    PORT
      LAYER M4 ;
        RECT  0 24.144 0.084 24.168 ;
    END
  END i_dg[23]
  PIN i_dg[24]
    DIRECTION INPUT ;
    USE SIGNAL ;
    PORT
      LAYER M4 ;
        RECT  0 24.24 0.084 24.264 ;
    END
  END i_dg[24]
  PIN i_dg[25]
    DIRECTION INPUT ;
    USE SIGNAL ;
    PORT
      LAYER M4 ;
        RECT  0 24.336 0.084 24.36 ;
    END
  END i_dg[25]
  PIN i_dg[26]
    DIRECTION INPUT ;
    USE SIGNAL ;
    PORT
      LAYER M4 ;
        RECT  0 24.432 0.084 24.456 ;
    END
  END i_dg[26]
  PIN i_dg[27]
    DIRECTION INPUT ;
    USE SIGNAL ;
    PORT
      LAYER M4 ;
        RECT  0 24.528 0.084 24.552 ;
    END
  END i_dg[27]
  PIN i_dg[28]
    DIRECTION INPUT ;
    USE SIGNAL ;
    PORT
      LAYER M4 ;
        RECT  0 24.624 0.084 24.648 ;
    END
  END i_dg[28]
  PIN i_dg[29]
    DIRECTION INPUT ;
    USE SIGNAL ;
    PORT
      LAYER M4 ;
        RECT  0 24.72 0.084 24.744 ;
    END
  END i_dg[29]
  PIN i_dg[2]
    DIRECTION INPUT ;
    USE SIGNAL ;
    PORT
      LAYER M4 ;
        RECT  0 22.128 0.084 22.152 ;
    END
  END i_dg[2]
  PIN i_dg[30]
    DIRECTION INPUT ;
    USE SIGNAL ;
    PORT
      LAYER M4 ;
        RECT  0 24.816 0.084 24.84 ;
    END
  END i_dg[30]
  PIN i_dg[31]
    DIRECTION INPUT ;
    USE SIGNAL ;
    PORT
      LAYER M4 ;
        RECT  0 18.768 0.084 18.792 ;
    END
  END i_dg[31]
  PIN i_dg[32]
    DIRECTION INPUT ;
    USE SIGNAL ;
    PORT
      LAYER M4 ;
        RECT  0 18.864 0.084 18.888 ;
    END
  END i_dg[32]
  PIN i_dg[33]
    DIRECTION INPUT ;
    USE SIGNAL ;
    PORT
      LAYER M4 ;
        RECT  0 18.96 0.084 18.984 ;
    END
  END i_dg[33]
  PIN i_dg[34]
    DIRECTION INPUT ;
    USE SIGNAL ;
    PORT
      LAYER M4 ;
        RECT  0 19.056 0.084 19.08 ;
    END
  END i_dg[34]
  PIN i_dg[35]
    DIRECTION INPUT ;
    USE SIGNAL ;
    PORT
      LAYER M4 ;
        RECT  0 19.152 0.084 19.176 ;
    END
  END i_dg[35]
  PIN i_dg[36]
    DIRECTION INPUT ;
    USE SIGNAL ;
    PORT
      LAYER M4 ;
        RECT  0 19.248 0.084 19.272 ;
    END
  END i_dg[36]
  PIN i_dg[37]
    DIRECTION INPUT ;
    USE SIGNAL ;
    PORT
      LAYER M4 ;
        RECT  0 19.344 0.084 19.368 ;
    END
  END i_dg[37]
  PIN i_dg[38]
    DIRECTION INPUT ;
    USE SIGNAL ;
    PORT
      LAYER M4 ;
        RECT  0 19.44 0.084 19.464 ;
    END
  END i_dg[38]
  PIN i_dg[39]
    DIRECTION INPUT ;
    USE SIGNAL ;
    PORT
      LAYER M4 ;
        RECT  0 19.536 0.084 19.56 ;
    END
  END i_dg[39]
  PIN i_dg[3]
    DIRECTION INPUT ;
    USE SIGNAL ;
    PORT
      LAYER M4 ;
        RECT  0 22.224 0.084 22.248 ;
    END
  END i_dg[3]
  PIN i_dg[40]
    DIRECTION INPUT ;
    USE SIGNAL ;
    PORT
      LAYER M4 ;
        RECT  0 19.632 0.084 19.656 ;
    END
  END i_dg[40]
  PIN i_dg[41]
    DIRECTION INPUT ;
    USE SIGNAL ;
    PORT
      LAYER M4 ;
        RECT  0 19.728 0.084 19.752 ;
    END
  END i_dg[41]
  PIN i_dg[42]
    DIRECTION INPUT ;
    USE SIGNAL ;
    PORT
      LAYER M4 ;
        RECT  0 19.824 0.084 19.848 ;
    END
  END i_dg[42]
  PIN i_dg[43]
    DIRECTION INPUT ;
    USE SIGNAL ;
    PORT
      LAYER M4 ;
        RECT  0 19.92 0.084 19.944 ;
    END
  END i_dg[43]
  PIN i_dg[44]
    DIRECTION INPUT ;
    USE SIGNAL ;
    PORT
      LAYER M4 ;
        RECT  0 20.016 0.084 20.04 ;
    END
  END i_dg[44]
  PIN i_dg[45]
    DIRECTION INPUT ;
    USE SIGNAL ;
    PORT
      LAYER M4 ;
        RECT  0 20.112 0.084 20.136 ;
    END
  END i_dg[45]
  PIN i_dg[46]
    DIRECTION INPUT ;
    USE SIGNAL ;
    PORT
      LAYER M4 ;
        RECT  0 20.208 0.084 20.232 ;
    END
  END i_dg[46]
  PIN i_dg[47]
    DIRECTION INPUT ;
    USE SIGNAL ;
    PORT
      LAYER M4 ;
        RECT  0 20.304 0.084 20.328 ;
    END
  END i_dg[47]
  PIN i_dg[48]
    DIRECTION INPUT ;
    USE SIGNAL ;
    PORT
      LAYER M4 ;
        RECT  0 20.4 0.084 20.424 ;
    END
  END i_dg[48]
  PIN i_dg[49]
    DIRECTION INPUT ;
    USE SIGNAL ;
    PORT
      LAYER M4 ;
        RECT  0 20.496 0.084 20.52 ;
    END
  END i_dg[49]
  PIN i_dg[4]
    DIRECTION INPUT ;
    USE SIGNAL ;
    PORT
      LAYER M4 ;
        RECT  0 22.32 0.084 22.344 ;
    END
  END i_dg[4]
  PIN i_dg[50]
    DIRECTION INPUT ;
    USE SIGNAL ;
    PORT
      LAYER M4 ;
        RECT  0 20.592 0.084 20.616 ;
    END
  END i_dg[50]
  PIN i_dg[51]
    DIRECTION INPUT ;
    USE SIGNAL ;
    PORT
      LAYER M4 ;
        RECT  0 20.688 0.084 20.712 ;
    END
  END i_dg[51]
  PIN i_dg[52]
    DIRECTION INPUT ;
    USE SIGNAL ;
    PORT
      LAYER M4 ;
        RECT  0 20.784 0.084 20.808 ;
    END
  END i_dg[52]
  PIN i_dg[53]
    DIRECTION INPUT ;
    USE SIGNAL ;
    PORT
      LAYER M4 ;
        RECT  0 20.88 0.084 20.904 ;
    END
  END i_dg[53]
  PIN i_dg[54]
    DIRECTION INPUT ;
    USE SIGNAL ;
    PORT
      LAYER M4 ;
        RECT  0 20.976 0.084 21 ;
    END
  END i_dg[54]
  PIN i_dg[55]
    DIRECTION INPUT ;
    USE SIGNAL ;
    PORT
      LAYER M4 ;
        RECT  0 21.072 0.084 21.096 ;
    END
  END i_dg[55]
  PIN i_dg[56]
    DIRECTION INPUT ;
    USE SIGNAL ;
    PORT
      LAYER M4 ;
        RECT  0 21.168 0.084 21.192 ;
    END
  END i_dg[56]
  PIN i_dg[57]
    DIRECTION INPUT ;
    USE SIGNAL ;
    PORT
      LAYER M4 ;
        RECT  0 21.264 0.084 21.288 ;
    END
  END i_dg[57]
  PIN i_dg[58]
    DIRECTION INPUT ;
    USE SIGNAL ;
    PORT
      LAYER M4 ;
        RECT  0 21.36 0.084 21.384 ;
    END
  END i_dg[58]
  PIN i_dg[59]
    DIRECTION INPUT ;
    USE SIGNAL ;
    PORT
      LAYER M4 ;
        RECT  0 21.456 0.084 21.48 ;
    END
  END i_dg[59]
  PIN i_dg[5]
    DIRECTION INPUT ;
    USE SIGNAL ;
    PORT
      LAYER M4 ;
        RECT  0 22.416 0.084 22.44 ;
    END
  END i_dg[5]
  PIN i_dg[60]
    DIRECTION INPUT ;
    USE SIGNAL ;
    PORT
      LAYER M4 ;
        RECT  0 21.552 0.084 21.576 ;
    END
  END i_dg[60]
  PIN i_dg[61]
    DIRECTION INPUT ;
    USE SIGNAL ;
    PORT
      LAYER M4 ;
        RECT  0 21.648 0.084 21.672 ;
    END
  END i_dg[61]
  PIN i_dg[62]
    DIRECTION INPUT ;
    USE SIGNAL ;
    PORT
      LAYER M4 ;
        RECT  0 21.744 0.084 21.768 ;
    END
  END i_dg[62]
  PIN i_dg[63]
    DIRECTION INPUT ;
    USE SIGNAL ;
    PORT
      LAYER M4 ;
        RECT  0 24.912 0.084 24.936 ;
    END
  END i_dg[63]
  PIN i_dg[64]
    DIRECTION INPUT ;
    USE SIGNAL ;
    PORT
      LAYER M4 ;
        RECT  0 25.008 0.084 25.032 ;
    END
  END i_dg[64]
  PIN i_dg[65]
    DIRECTION INPUT ;
    USE SIGNAL ;
    PORT
      LAYER M4 ;
        RECT  0 25.104 0.084 25.128 ;
    END
  END i_dg[65]
  PIN i_dg[66]
    DIRECTION INPUT ;
    USE SIGNAL ;
    PORT
      LAYER M4 ;
        RECT  0 25.2 0.084 25.224 ;
    END
  END i_dg[66]
  PIN i_dg[67]
    DIRECTION INPUT ;
    USE SIGNAL ;
    PORT
      LAYER M4 ;
        RECT  0 25.296 0.084 25.32 ;
    END
  END i_dg[67]
  PIN i_dg[68]
    DIRECTION INPUT ;
    USE SIGNAL ;
    PORT
      LAYER M4 ;
        RECT  0 25.392 0.084 25.416 ;
    END
  END i_dg[68]
  PIN i_dg[69]
    DIRECTION INPUT ;
    USE SIGNAL ;
    PORT
      LAYER M4 ;
        RECT  0 25.488 0.084 25.512 ;
    END
  END i_dg[69]
  PIN i_dg[6]
    DIRECTION INPUT ;
    USE SIGNAL ;
    PORT
      LAYER M4 ;
        RECT  0 22.512 0.084 22.536 ;
    END
  END i_dg[6]
  PIN i_dg[70]
    DIRECTION INPUT ;
    USE SIGNAL ;
    PORT
      LAYER M4 ;
        RECT  0 25.584 0.084 25.608 ;
    END
  END i_dg[70]
  PIN i_dg[71]
    DIRECTION INPUT ;
    USE SIGNAL ;
    PORT
      LAYER M4 ;
        RECT  0 25.68 0.084 25.704 ;
    END
  END i_dg[71]
  PIN i_dg[72]
    DIRECTION INPUT ;
    USE SIGNAL ;
    PORT
      LAYER M4 ;
        RECT  0 25.776 0.084 25.8 ;
    END
  END i_dg[72]
  PIN i_dg[73]
    DIRECTION INPUT ;
    USE SIGNAL ;
    PORT
      LAYER M4 ;
        RECT  0 25.872 0.084 25.896 ;
    END
  END i_dg[73]
  PIN i_dg[74]
    DIRECTION INPUT ;
    USE SIGNAL ;
    PORT
      LAYER M4 ;
        RECT  0 25.968 0.084 25.992 ;
    END
  END i_dg[74]
  PIN i_dg[75]
    DIRECTION INPUT ;
    USE SIGNAL ;
    PORT
      LAYER M4 ;
        RECT  0 26.064 0.084 26.088 ;
    END
  END i_dg[75]
  PIN i_dg[76]
    DIRECTION INPUT ;
    USE SIGNAL ;
    PORT
      LAYER M4 ;
        RECT  0 26.16 0.084 26.184 ;
    END
  END i_dg[76]
  PIN i_dg[77]
    DIRECTION INPUT ;
    USE SIGNAL ;
    PORT
      LAYER M4 ;
        RECT  0 26.256 0.084 26.28 ;
    END
  END i_dg[77]
  PIN i_dg[78]
    DIRECTION INPUT ;
    USE SIGNAL ;
    PORT
      LAYER M4 ;
        RECT  0 26.352 0.084 26.376 ;
    END
  END i_dg[78]
  PIN i_dg[79]
    DIRECTION INPUT ;
    USE SIGNAL ;
    PORT
      LAYER M4 ;
        RECT  0 26.448 0.084 26.472 ;
    END
  END i_dg[79]
  PIN i_dg[7]
    DIRECTION INPUT ;
    USE SIGNAL ;
    PORT
      LAYER M4 ;
        RECT  0 22.608 0.084 22.632 ;
    END
  END i_dg[7]
  PIN i_dg[80]
    DIRECTION INPUT ;
    USE SIGNAL ;
    PORT
      LAYER M4 ;
        RECT  0 26.544 0.084 26.568 ;
    END
  END i_dg[80]
  PIN i_dg[81]
    DIRECTION INPUT ;
    USE SIGNAL ;
    PORT
      LAYER M4 ;
        RECT  0 26.64 0.084 26.664 ;
    END
  END i_dg[81]
  PIN i_dg[82]
    DIRECTION INPUT ;
    USE SIGNAL ;
    PORT
      LAYER M4 ;
        RECT  0 26.736 0.084 26.76 ;
    END
  END i_dg[82]
  PIN i_dg[83]
    DIRECTION INPUT ;
    USE SIGNAL ;
    PORT
      LAYER M4 ;
        RECT  0 26.832 0.084 26.856 ;
    END
  END i_dg[83]
  PIN i_dg[84]
    DIRECTION INPUT ;
    USE SIGNAL ;
    PORT
      LAYER M4 ;
        RECT  0 26.928 0.084 26.952 ;
    END
  END i_dg[84]
  PIN i_dg[85]
    DIRECTION INPUT ;
    USE SIGNAL ;
    PORT
      LAYER M4 ;
        RECT  0 27.024 0.084 27.048 ;
    END
  END i_dg[85]
  PIN i_dg[86]
    DIRECTION INPUT ;
    USE SIGNAL ;
    PORT
      LAYER M4 ;
        RECT  0 27.12 0.084 27.144 ;
    END
  END i_dg[86]
  PIN i_dg[87]
    DIRECTION INPUT ;
    USE SIGNAL ;
    PORT
      LAYER M4 ;
        RECT  0 27.216 0.084 27.24 ;
    END
  END i_dg[87]
  PIN i_dg[88]
    DIRECTION INPUT ;
    USE SIGNAL ;
    PORT
      LAYER M4 ;
        RECT  0 27.312 0.084 27.336 ;
    END
  END i_dg[88]
  PIN i_dg[89]
    DIRECTION INPUT ;
    USE SIGNAL ;
    PORT
      LAYER M4 ;
        RECT  0 27.408 0.084 27.432 ;
    END
  END i_dg[89]
  PIN i_dg[8]
    DIRECTION INPUT ;
    USE SIGNAL ;
    PORT
      LAYER M4 ;
        RECT  0 22.704 0.084 22.728 ;
    END
  END i_dg[8]
  PIN i_dg[90]
    DIRECTION INPUT ;
    USE SIGNAL ;
    PORT
      LAYER M4 ;
        RECT  0 27.504 0.084 27.528 ;
    END
  END i_dg[90]
  PIN i_dg[91]
    DIRECTION INPUT ;
    USE SIGNAL ;
    PORT
      LAYER M4 ;
        RECT  0 27.6 0.084 27.624 ;
    END
  END i_dg[91]
  PIN i_dg[92]
    DIRECTION INPUT ;
    USE SIGNAL ;
    PORT
      LAYER M4 ;
        RECT  0 27.696 0.084 27.72 ;
    END
  END i_dg[92]
  PIN i_dg[93]
    DIRECTION INPUT ;
    USE SIGNAL ;
    PORT
      LAYER M4 ;
        RECT  0 27.792 0.084 27.816 ;
    END
  END i_dg[93]
  PIN i_dg[94]
    DIRECTION INPUT ;
    USE SIGNAL ;
    PORT
      LAYER M4 ;
        RECT  0 27.888 0.084 27.912 ;
    END
  END i_dg[94]
  PIN i_dg[95]
    DIRECTION INPUT ;
    USE SIGNAL ;
    PORT
      LAYER M4 ;
        RECT  0 31.056 0.084 31.08 ;
    END
  END i_dg[95]
  PIN i_dg[96]
    DIRECTION INPUT ;
    USE SIGNAL ;
    PORT
      LAYER M4 ;
        RECT  0 31.152 0.084 31.176 ;
    END
  END i_dg[96]
  PIN i_dg[97]
    DIRECTION INPUT ;
    USE SIGNAL ;
    PORT
      LAYER M4 ;
        RECT  0 31.248 0.084 31.272 ;
    END
  END i_dg[97]
  PIN i_dg[98]
    DIRECTION INPUT ;
    USE SIGNAL ;
    PORT
      LAYER M4 ;
        RECT  0 31.344 0.084 31.368 ;
    END
  END i_dg[98]
  PIN i_dg[99]
    DIRECTION INPUT ;
    USE SIGNAL ;
    PORT
      LAYER M4 ;
        RECT  0 31.44 0.084 31.464 ;
    END
  END i_dg[99]
  PIN i_dg[9]
    DIRECTION INPUT ;
    USE SIGNAL ;
    PORT
      LAYER M4 ;
        RECT  0 22.8 0.084 22.824 ;
    END
  END i_dg[9]
  PIN i_en[0]
    DIRECTION INPUT ;
    USE SIGNAL ;
    PORT
      LAYER M4 ;
        RECT  0 17.136 0.084 17.16 ;
    END
  END i_en[0]
  PIN i_en[10]
    DIRECTION INPUT ;
    USE SIGNAL ;
    PORT
      LAYER M4 ;
        RECT  0 18.096 0.084 18.12 ;
    END
  END i_en[10]
  PIN i_en[11]
    DIRECTION INPUT ;
    USE SIGNAL ;
    PORT
      LAYER M4 ;
        RECT  0 18.192 0.084 18.216 ;
    END
  END i_en[11]
  PIN i_en[12]
    DIRECTION INPUT ;
    USE SIGNAL ;
    PORT
      LAYER M4 ;
        RECT  0 18.288 0.084 18.312 ;
    END
  END i_en[12]
  PIN i_en[13]
    DIRECTION INPUT ;
    USE SIGNAL ;
    PORT
      LAYER M4 ;
        RECT  0 18.384 0.084 18.408 ;
    END
  END i_en[13]
  PIN i_en[14]
    DIRECTION INPUT ;
    USE SIGNAL ;
    PORT
      LAYER M4 ;
        RECT  0 18.48 0.084 18.504 ;
    END
  END i_en[14]
  PIN i_en[15]
    DIRECTION INPUT ;
    USE SIGNAL ;
    PORT
      LAYER M4 ;
        RECT  0 18.576 0.084 18.6 ;
    END
  END i_en[15]
  PIN i_en[1]
    DIRECTION INPUT ;
    USE SIGNAL ;
    PORT
      LAYER M4 ;
        RECT  0 17.232 0.084 17.256 ;
    END
  END i_en[1]
  PIN i_en[2]
    DIRECTION INPUT ;
    USE SIGNAL ;
    PORT
      LAYER M4 ;
        RECT  0 17.328 0.084 17.352 ;
    END
  END i_en[2]
  PIN i_en[3]
    DIRECTION INPUT ;
    USE SIGNAL ;
    PORT
      LAYER M4 ;
        RECT  0 17.424 0.084 17.448 ;
    END
  END i_en[3]
  PIN i_en[4]
    DIRECTION INPUT ;
    USE SIGNAL ;
    PORT
      LAYER M4 ;
        RECT  0 17.52 0.084 17.544 ;
    END
  END i_en[4]
  PIN i_en[5]
    DIRECTION INPUT ;
    USE SIGNAL ;
    PORT
      LAYER M4 ;
        RECT  0 17.616 0.084 17.64 ;
    END
  END i_en[5]
  PIN i_en[6]
    DIRECTION INPUT ;
    USE SIGNAL ;
    PORT
      LAYER M4 ;
        RECT  0 17.712 0.084 17.736 ;
    END
  END i_en[6]
  PIN i_en[7]
    DIRECTION INPUT ;
    USE SIGNAL ;
    PORT
      LAYER M4 ;
        RECT  0 17.808 0.084 17.832 ;
    END
  END i_en[7]
  PIN i_en[8]
    DIRECTION INPUT ;
    USE SIGNAL ;
    PORT
      LAYER M4 ;
        RECT  0 17.904 0.084 17.928 ;
    END
  END i_en[8]
  PIN i_en[9]
    DIRECTION INPUT ;
    USE SIGNAL ;
    PORT
      LAYER M4 ;
        RECT  0 18 0.084 18.024 ;
    END
  END i_en[9]
  PIN i_v
    DIRECTION INPUT ;
    USE SIGNAL ;
    PORT
      LAYER M4 ;
        RECT  0 18.672 0.084 18.696 ;
    END
  END i_v
  PIN rst_n
    DIRECTION INPUT ;
    USE SIGNAL ;
    PORT
      LAYER M5 ;
        RECT  20.4 0 20.424 0.084 ;
    END
  END rst_n
  PIN VDD
    DIRECTION INOUT ;
    USE POWER ;
    PORT
      LAYER M5 ;
        RECT  61.992 2.151 62.112 51.849 ;
        RECT  56.592 2.151 56.712 51.849 ;
        RECT  51.192 2.151 51.312 51.849 ;
        RECT  45.792 2.151 45.912 51.849 ;
        RECT  40.392 2.151 40.512 51.849 ;
        RECT  34.992 2.151 35.112 51.849 ;
        RECT  29.592 2.151 29.712 51.849 ;
        RECT  24.192 2.151 24.312 51.849 ;
        RECT  18.792 2.151 18.912 51.849 ;
        RECT  13.392 2.151 13.512 51.849 ;
        RECT  7.992 2.151 8.112 51.849 ;
        RECT  2.592 2.151 2.712 51.849 ;
    END
  END VDD
  PIN VSS
    DIRECTION INOUT ;
    USE GROUND ;
    PORT
      LAYER M5 ;
        RECT  61.8 2.137 61.92 51.863 ;
        RECT  56.4 2.137 56.52 51.863 ;
        RECT  51 2.137 51.12 51.863 ;
        RECT  45.6 2.137 45.72 51.863 ;
        RECT  40.2 2.137 40.32 51.863 ;
        RECT  34.8 2.137 34.92 51.863 ;
        RECT  29.4 2.137 29.52 51.863 ;
        RECT  24 2.137 24.12 51.863 ;
        RECT  18.6 2.137 18.72 51.863 ;
        RECT  13.2 2.137 13.32 51.863 ;
        RECT  7.8 2.137 7.92 51.863 ;
        RECT  2.4 2.137 2.52 51.863 ;
    END
  END VSS
  OBS
    LAYER RVTN ;
     RECT  2.16 2.16 62.64 2.295 ;
     RECT  2.16 2.565 62.64 2.835 ;
     RECT  2.16 3.105 62.64 3.375 ;
     RECT  2.16 3.645 62.64 3.915 ;
     RECT  2.16 4.185 62.64 4.455 ;
     RECT  2.16 4.725 62.64 4.995 ;
     RECT  2.16 5.265 62.64 5.535 ;
     RECT  2.16 5.805 62.64 6.075 ;
     RECT  2.16 6.345 62.64 6.615 ;
     RECT  2.16 6.885 62.64 7.155 ;
     RECT  2.16 7.425 62.64 7.695 ;
     RECT  2.16 7.965 62.64 8.235 ;
     RECT  2.16 8.505 62.64 8.775 ;
     RECT  2.16 9.045 62.64 9.315 ;
     RECT  2.16 9.585 62.64 9.855 ;
     RECT  2.16 10.125 62.64 10.395 ;
     RECT  2.16 10.665 62.64 10.935 ;
     RECT  2.16 11.205 62.64 11.475 ;
     RECT  2.16 11.745 62.64 12.015 ;
     RECT  2.16 12.285 62.64 12.555 ;
     RECT  2.16 12.825 62.64 13.095 ;
     RECT  2.16 13.365 62.64 13.635 ;
     RECT  2.16 13.905 62.64 14.175 ;
     RECT  2.16 14.445 62.64 14.715 ;
     RECT  2.16 14.985 62.64 15.255 ;
     RECT  2.16 15.525 62.64 15.795 ;
     RECT  2.16 16.065 62.64 16.335 ;
     RECT  2.16 16.605 62.64 16.875 ;
     RECT  2.16 17.145 62.64 17.415 ;
     RECT  2.16 17.685 62.64 17.955 ;
     RECT  2.16 18.225 62.64 18.495 ;
     RECT  2.16 18.765 62.64 19.035 ;
     RECT  2.16 19.305 62.64 19.575 ;
     RECT  2.16 19.845 62.64 20.115 ;
     RECT  2.16 20.385 62.64 20.655 ;
     RECT  2.16 20.925 62.64 21.195 ;
     RECT  2.16 21.465 62.64 21.735 ;
     RECT  2.16 22.005 62.64 22.275 ;
     RECT  2.16 22.545 62.64 22.815 ;
     RECT  2.16 23.085 62.64 23.355 ;
     RECT  2.16 23.625 62.64 23.895 ;
     RECT  2.16 24.165 62.64 24.435 ;
     RECT  2.16 24.705 62.64 24.975 ;
     RECT  2.16 25.245 62.64 25.515 ;
     RECT  2.16 25.785 62.64 26.055 ;
     RECT  2.16 26.325 62.64 26.595 ;
     RECT  2.16 26.865 62.64 27.135 ;
     RECT  2.16 27.405 62.64 27.675 ;
     RECT  2.16 27.945 62.64 28.215 ;
     RECT  2.16 28.485 62.64 28.755 ;
     RECT  2.16 29.025 62.64 29.295 ;
     RECT  2.16 29.565 62.64 29.835 ;
     RECT  2.16 30.105 62.64 30.375 ;
     RECT  2.16 30.645 62.64 30.915 ;
     RECT  2.16 31.185 62.64 31.455 ;
     RECT  2.16 31.725 62.64 31.995 ;
     RECT  2.16 32.265 62.64 32.535 ;
     RECT  2.16 32.805 62.64 33.075 ;
     RECT  2.16 33.345 62.64 33.615 ;
     RECT  2.16 33.885 62.64 34.155 ;
     RECT  2.16 34.425 62.64 34.695 ;
     RECT  2.16 34.965 62.64 35.235 ;
     RECT  2.16 35.505 62.64 35.775 ;
     RECT  2.16 36.045 62.64 36.315 ;
     RECT  2.16 36.585 62.64 36.855 ;
     RECT  2.16 37.125 62.64 37.395 ;
     RECT  2.16 37.665 62.64 37.935 ;
     RECT  2.16 38.205 62.64 38.475 ;
     RECT  2.16 38.745 62.64 39.015 ;
     RECT  2.16 39.285 62.64 39.555 ;
     RECT  2.16 39.825 62.64 40.095 ;
     RECT  2.16 40.365 62.64 40.635 ;
     RECT  2.16 40.905 62.64 41.175 ;
     RECT  2.16 41.445 62.64 41.715 ;
     RECT  2.16 41.985 62.64 42.255 ;
     RECT  2.16 42.525 62.64 42.795 ;
     RECT  2.16 43.065 62.64 43.335 ;
     RECT  2.16 43.605 62.64 43.875 ;
     RECT  2.16 44.145 62.64 44.415 ;
     RECT  2.16 44.685 62.64 44.955 ;
     RECT  2.16 45.225 62.64 45.495 ;
     RECT  2.16 45.765 62.64 46.035 ;
     RECT  2.16 46.305 62.64 46.575 ;
     RECT  2.16 46.845 62.64 47.115 ;
     RECT  2.16 47.385 62.64 47.655 ;
     RECT  2.16 47.925 62.64 48.195 ;
     RECT  2.16 48.465 62.64 48.735 ;
     RECT  2.16 49.005 62.64 49.275 ;
     RECT  2.16 49.545 62.64 49.815 ;
     RECT  2.16 50.085 62.64 50.355 ;
     RECT  2.16 50.625 62.64 50.895 ;
     RECT  2.16 51.165 62.64 51.435 ;
     RECT  2.16 51.705 62.64 51.84 ;
    LAYER RVTP ;
     RECT  2.16 2.295 62.64 2.565 ;
     RECT  2.16 2.835 62.64 3.105 ;
     RECT  2.16 3.375 62.64 3.645 ;
     RECT  2.16 3.915 62.64 4.185 ;
     RECT  2.16 4.455 62.64 4.725 ;
     RECT  2.16 4.995 62.64 5.265 ;
     RECT  2.16 5.535 62.64 5.805 ;
     RECT  2.16 6.075 62.64 6.345 ;
     RECT  2.16 6.615 62.64 6.885 ;
     RECT  2.16 7.155 62.64 7.425 ;
     RECT  2.16 7.695 62.64 7.965 ;
     RECT  2.16 8.235 62.64 8.505 ;
     RECT  2.16 8.775 62.64 9.045 ;
     RECT  2.16 9.315 62.64 9.585 ;
     RECT  2.16 9.855 62.64 10.125 ;
     RECT  2.16 10.395 62.64 10.665 ;
     RECT  2.16 10.935 62.64 11.205 ;
     RECT  2.16 11.475 62.64 11.745 ;
     RECT  2.16 12.015 62.64 12.285 ;
     RECT  2.16 12.555 62.64 12.825 ;
     RECT  2.16 13.095 62.64 13.365 ;
     RECT  2.16 13.635 62.64 13.905 ;
     RECT  2.16 14.175 62.64 14.445 ;
     RECT  2.16 14.715 62.64 14.985 ;
     RECT  2.16 15.255 62.64 15.525 ;
     RECT  2.16 15.795 62.64 16.065 ;
     RECT  2.16 16.335 62.64 16.605 ;
     RECT  2.16 16.875 62.64 17.145 ;
     RECT  2.16 17.415 62.64 17.685 ;
     RECT  2.16 17.955 62.64 18.225 ;
     RECT  2.16 18.495 62.64 18.765 ;
     RECT  2.16 19.035 62.64 19.305 ;
     RECT  2.16 19.575 62.64 19.845 ;
     RECT  2.16 20.115 62.64 20.385 ;
     RECT  2.16 20.655 62.64 20.925 ;
     RECT  2.16 21.195 62.64 21.465 ;
     RECT  2.16 21.735 62.64 22.005 ;
     RECT  2.16 22.275 62.64 22.545 ;
     RECT  2.16 22.815 62.64 23.085 ;
     RECT  2.16 23.355 62.64 23.625 ;
     RECT  2.16 23.895 62.64 24.165 ;
     RECT  2.16 24.435 62.64 24.705 ;
     RECT  2.16 24.975 62.64 25.245 ;
     RECT  2.16 25.515 62.64 25.785 ;
     RECT  2.16 26.055 62.64 26.325 ;
     RECT  2.16 26.595 62.64 26.865 ;
     RECT  2.16 27.135 62.64 27.405 ;
     RECT  2.16 27.675 62.64 27.945 ;
     RECT  2.16 28.215 62.64 28.485 ;
     RECT  2.16 28.755 62.64 29.025 ;
     RECT  2.16 29.295 62.64 29.565 ;
     RECT  2.16 29.835 62.64 30.105 ;
     RECT  2.16 30.375 62.64 30.645 ;
     RECT  2.16 30.915 62.64 31.185 ;
     RECT  2.16 31.455 62.64 31.725 ;
     RECT  2.16 31.995 62.64 32.265 ;
     RECT  2.16 32.535 62.64 32.805 ;
     RECT  2.16 33.075 62.64 33.345 ;
     RECT  2.16 33.615 62.64 33.885 ;
     RECT  2.16 34.155 62.64 34.425 ;
     RECT  2.16 34.695 62.64 34.965 ;
     RECT  2.16 35.235 62.64 35.505 ;
     RECT  2.16 35.775 62.64 36.045 ;
     RECT  2.16 36.315 62.64 36.585 ;
     RECT  2.16 36.855 62.64 37.125 ;
     RECT  2.16 37.395 62.64 37.665 ;
     RECT  2.16 37.935 62.64 38.205 ;
     RECT  2.16 38.475 62.64 38.745 ;
     RECT  2.16 39.015 62.64 39.285 ;
     RECT  2.16 39.555 62.64 39.825 ;
     RECT  2.16 40.095 62.64 40.365 ;
     RECT  2.16 40.635 62.64 40.905 ;
     RECT  2.16 41.175 62.64 41.445 ;
     RECT  2.16 41.715 62.64 41.985 ;
     RECT  2.16 42.255 62.64 42.525 ;
     RECT  2.16 42.795 62.64 43.065 ;
     RECT  2.16 43.335 62.64 43.605 ;
     RECT  2.16 43.875 62.64 44.145 ;
     RECT  2.16 44.415 62.64 44.685 ;
     RECT  2.16 44.955 62.64 45.225 ;
     RECT  2.16 45.495 62.64 45.765 ;
     RECT  2.16 46.035 62.64 46.305 ;
     RECT  2.16 46.575 62.64 46.845 ;
     RECT  2.16 47.115 62.64 47.385 ;
     RECT  2.16 47.655 62.64 47.925 ;
     RECT  2.16 48.195 62.64 48.465 ;
     RECT  2.16 48.735 62.64 49.005 ;
     RECT  2.16 49.275 62.64 49.545 ;
     RECT  2.16 49.815 62.64 50.085 ;
     RECT  2.16 50.355 62.64 50.625 ;
     RECT  2.16 50.895 62.64 51.165 ;
     RECT  2.16 51.435 62.64 51.705 ;
    LAYER M1 ;
     RECT  2.16 2.151 62.64 51.849 ;
    LAYER M2 ;
     RECT  0.103 21.132 0.203 21.15 ;
     RECT  0.103 32.472 0.499 32.49 ;
     RECT  0.103 22.788 0.535 22.806 ;
     RECT  0.499 24.246 0.535 24.264 ;
     RECT  0.103 30.69 0.535 30.708 ;
     RECT  0.499 32.472 0.535 32.904 ;
     RECT  0.535 16.344 2.16 16.362 ;
     RECT  0.535 19.656 2.16 19.674 ;
     RECT  0.535 20.466 2.16 20.484 ;
     RECT  0.535 22.086 2.16 24.768 ;
     RECT  0.535 25.866 2.16 25.884 ;
     RECT  0.535 30.69 2.16 30.906 ;
     RECT  0.535 32.472 2.16 33.066 ;
     RECT  2.16 2.151 18.355 51.849 ;
     RECT  18.355 2.106 19.435 51.849 ;
     RECT  19.435 2.034 22.739 51.849 ;
     RECT  22.739 2.07 25.223 51.849 ;
     RECT  25.223 2.106 45.383 51.849 ;
     RECT  45.383 2.151 62.64 51.849 ;
     RECT  62.64 15.606 62.915 19.566 ;
     RECT  62.915 15.606 63.311 19.494 ;
     RECT  62.64 25.596 63.347 29.754 ;
     RECT  62.64 6.516 63.851 10.314 ;
     RECT  63.311 15.696 63.851 19.494 ;
     RECT  63.347 25.794 63.851 29.754 ;
     RECT  62.64 41.616 63.851 50.148 ;
     RECT  63.851 6.516 63.887 7.884 ;
     RECT  63.851 15.696 63.887 18.018 ;
     RECT  63.851 25.794 63.887 27.774 ;
     RECT  63.851 41.616 63.887 49.266 ;
     RECT  63.887 6.516 63.923 7.344 ;
     RECT  63.887 16.236 63.923 17.064 ;
     RECT  63.887 26.334 63.923 26.694 ;
     RECT  63.887 41.616 63.923 43.164 ;
     RECT  63.887 43.956 63.923 49.266 ;
     RECT  63.923 6.516 63.959 6.534 ;
     RECT  63.923 16.308 63.959 16.524 ;
     RECT  63.923 43.956 63.959 44.784 ;
     RECT  63.923 45.846 63.959 48.024 ;
     RECT  63.923 48.816 63.959 49.266 ;
     RECT  63.959 16.506 63.995 16.524 ;
     RECT  63.923 41.616 64.067 43.056 ;
     RECT  64.067 41.616 64.103 41.634 ;
     RECT  64.067 42.57 64.103 43.056 ;
     RECT  63.959 46.656 64.103 48.024 ;
     RECT  63.887 17.856 64.643 18.018 ;
     RECT  64.643 17.892 64.679 18.018 ;
     RECT  63.851 18.846 64.679 19.404 ;
     RECT  63.851 28.53 64.679 29.484 ;
     RECT  64.103 46.656 64.679 46.674 ;
     RECT  64.103 47.628 64.679 48.024 ;
     RECT  63.851 8.784 64.715 9.144 ;
     RECT  63.851 9.936 64.715 9.954 ;
     RECT  64.679 18 64.715 18.018 ;
     RECT  64.679 19.386 64.715 19.404 ;
     RECT  63.923 26.334 64.715 26.352 ;
     RECT  64.679 28.53 64.715 29.214 ;
     RECT  63.959 44.226 64.715 44.784 ;
     RECT  63.959 45.846 64.715 45.864 ;
     RECT  64.679 47.628 64.715 47.799 ;
     RECT  63.959 48.816 64.715 49.23 ;
     RECT  63.851 50.13 64.715 50.148 ;
    LAYER M3 ;
     RECT  19.908 0.091 19.926 1.723 ;
     RECT  19.908 1.723 20.178 2.029 ;
     RECT  22.716 2.029 22.734 2.065 ;
     RECT  19.44 2.029 20.178 2.101 ;
     RECT  21.816 0.091 21.834 2.101 ;
     RECT  18.36 2.101 18.378 2.143 ;
     RECT  45.36 2.101 45.378 2.143 ;
     RECT  24.015 2.143 24.105 2.191 ;
     RECT  33.552 2.191 33.57 2.227 ;
     RECT  31.428 2.191 31.446 2.251 ;
     RECT  15.948 0.043 15.966 2.255 ;
     RECT  18.36 2.143 18.705 2.263 ;
     RECT  19.44 2.101 20.538 2.263 ;
     RECT  21.564 2.101 21.834 2.263 ;
     RECT  22.716 2.065 22.806 2.263 ;
     RECT  23.616 2.191 24.105 2.263 ;
     RECT  33.552 2.227 33.714 2.263 ;
     RECT  38.34 2.191 38.358 2.263 ;
     RECT  27.792 2.191 27.81 2.299 ;
     RECT  29.415 2.143 29.505 2.299 ;
     RECT  31.104 2.251 31.446 2.299 ;
     RECT  33.552 2.263 34.074 2.299 ;
     RECT  36.54 2.251 36.558 2.299 ;
     RECT  38.34 2.263 38.43 2.299 ;
     RECT  40.215 2.143 40.305 2.299 ;
     RECT  43.236 2.263 43.254 2.299 ;
     RECT  46.764 2.293 46.782 2.299 ;
     RECT  51.015 2.143 51.105 2.299 ;
     RECT  55.548 2.263 55.566 2.299 ;
     RECT  27.144 2.299 27.882 2.335 ;
     RECT  28.944 2.299 29.505 2.335 ;
     RECT  31.104 2.299 32.166 2.335 ;
     RECT  33.012 2.299 34.074 2.335 ;
     RECT  34.815 2.143 34.905 2.335 ;
     RECT  36.288 2.299 36.558 2.335 ;
     RECT  42.66 2.299 43.254 2.335 ;
     RECT  53.856 2.299 53.874 2.335 ;
     RECT  17.424 2.335 17.442 2.371 ;
     RECT  26.352 2.347 26.37 2.371 ;
     RECT  27.144 2.335 29.505 2.371 ;
     RECT  30.276 2.299 30.294 2.371 ;
     RECT  31.104 2.335 34.074 2.371 ;
     RECT  41.256 2.299 41.274 2.371 ;
     RECT  42.624 2.335 43.29 2.371 ;
     RECT  46.764 2.299 46.854 2.371 ;
     RECT  48.132 2.299 48.15 2.371 ;
     RECT  52.128 2.335 52.146 2.371 ;
     RECT  53.676 2.335 53.874 2.371 ;
     RECT  41.256 2.371 41.346 2.395 ;
     RECT  42.624 2.371 43.326 2.395 ;
     RECT  2.415 2.143 2.505 2.413 ;
     RECT  7.815 2.143 7.905 2.413 ;
     RECT  13.215 2.143 13.305 2.413 ;
     RECT  22.716 2.263 24.105 2.413 ;
     RECT  26.352 2.371 29.505 2.413 ;
     RECT  30.276 2.371 34.074 2.413 ;
     RECT  38.34 2.299 40.305 2.413 ;
     RECT  41.112 2.395 41.346 2.413 ;
     RECT  45.36 2.143 45.705 2.413 ;
     RECT  51.015 2.299 51.174 2.413 ;
     RECT  56.415 2.143 56.505 2.413 ;
     RECT  61.815 2.143 61.905 2.413 ;
     RECT  17.424 2.371 17.586 2.461 ;
     RECT  18.36 2.263 20.826 2.461 ;
     RECT  21.564 2.263 21.906 2.461 ;
     RECT  38.34 2.413 41.346 2.461 ;
     RECT  50.004 2.299 50.094 2.461 ;
     RECT  51.015 2.413 51.297 2.461 ;
     RECT  26.352 2.413 34.074 2.497 ;
     RECT  34.815 2.335 36.558 2.497 ;
     RECT  37.908 2.461 41.346 2.497 ;
     RECT  42.624 2.395 43.542 2.497 ;
     RECT  45.36 2.413 45.897 2.497 ;
     RECT  46.764 2.371 46.998 2.497 ;
     RECT  48.06 2.371 48.15 2.497 ;
     RECT  49.572 2.461 51.297 2.533 ;
     RECT  25.2 2.065 25.218 2.569 ;
     RECT  37.908 2.497 43.542 2.569 ;
     RECT  52.128 2.371 52.218 2.569 ;
     RECT  17.424 2.461 21.978 2.605 ;
     RECT  22.716 2.413 24.297 2.605 ;
     RECT  26.352 2.497 36.558 2.605 ;
     RECT  52.956 2.371 54.09 2.605 ;
     RECT  54.936 2.299 55.566 2.605 ;
     RECT  56.415 2.413 56.697 2.605 ;
     RECT  17.352 2.605 24.297 2.641 ;
     RECT  25.02 2.569 25.614 2.641 ;
     RECT  37.872 2.569 43.542 2.641 ;
     RECT  52.956 2.605 54.198 2.641 ;
     RECT  54.936 2.605 56.697 2.641 ;
     RECT  57.6 2.605 57.618 2.641 ;
     RECT  44.964 2.497 45.897 2.731 ;
     RECT  49.464 2.533 51.297 2.731 ;
     RECT  52.056 2.569 52.218 2.731 ;
     RECT  52.956 2.641 57.654 2.731 ;
     RECT  52.956 2.731 58.194 2.759 ;
     RECT  17.28 2.641 25.614 2.767 ;
     RECT  26.352 2.605 36.666 2.767 ;
     RECT  37.872 2.641 44.226 2.767 ;
     RECT  44.964 2.731 46.026 2.767 ;
     RECT  46.764 2.497 48.15 2.767 ;
     RECT  15.408 2.371 15.426 2.795 ;
     RECT  37.512 2.767 44.226 2.803 ;
     RECT  44.964 2.767 48.294 2.803 ;
     RECT  16.344 2.641 16.362 2.813 ;
     RECT  54.72 2.759 58.194 2.831 ;
     RECT  17.208 2.767 36.666 2.839 ;
     RECT  49.464 2.731 52.218 2.839 ;
     RECT  57.6 2.831 58.194 2.903 ;
     RECT  17.208 2.839 36.738 2.939 ;
     RECT  37.512 2.803 48.294 2.957 ;
     RECT  17.28 2.939 36.738 3.001 ;
     RECT  37.512 2.957 41.958 3.001 ;
     RECT  17.28 3.001 41.958 3.029 ;
     RECT  17.28 3.029 39.222 3.101 ;
     RECT  57.636 2.903 58.194 3.101 ;
     RECT  54.72 2.831 56.826 3.137 ;
     RECT  49.032 2.839 52.218 3.145 ;
     RECT  17.28 3.101 31.086 3.173 ;
     RECT  42.732 2.957 48.294 3.181 ;
     RECT  49.032 3.145 52.47 3.181 ;
     RECT  57.852 3.101 58.194 3.181 ;
     RECT  10.224 2.731 10.242 3.271 ;
     RECT  17.28 3.173 28.53 3.299 ;
     RECT  53.208 2.759 53.766 3.299 ;
     RECT  29.412 3.173 31.086 3.335 ;
     RECT  53.208 3.299 53.226 3.335 ;
     RECT  29.412 3.335 31.014 3.407 ;
     RECT  10.224 3.271 10.314 3.415 ;
     RECT  10.224 3.415 10.53 3.451 ;
     RECT  9.432 3.451 10.53 3.541 ;
     RECT  9.432 3.541 10.602 3.649 ;
     RECT  57.852 3.181 58.662 3.847 ;
     RECT  42.732 3.181 52.47 3.911 ;
     RECT  32.112 3.101 39.186 3.931 ;
     RECT  40.215 3.029 41.958 3.931 ;
     RECT  11.556 3.811 11.574 3.955 ;
     RECT  32.112 3.931 41.958 3.955 ;
     RECT  54.792 3.137 56.826 3.955 ;
     RECT  57.564 3.847 58.662 3.955 ;
     RECT  9.252 3.649 10.602 3.991 ;
     RECT  11.52 3.955 11.574 3.991 ;
     RECT  32.076 3.955 41.958 4.019 ;
     RECT  29.415 3.407 31.014 4.081 ;
     RECT  32.076 4.019 32.346 4.081 ;
     RECT  33.12 4.019 41.958 4.081 ;
     RECT  42.732 3.911 51.57 4.081 ;
     RECT  33.12 4.081 51.57 4.109 ;
     RECT  9.252 3.991 11.574 4.117 ;
     RECT  9.252 4.117 12.006 4.145 ;
     RECT  9.648 4.145 12.006 4.181 ;
     RECT  13.215 2.413 13.497 4.225 ;
     RECT  17.424 3.299 28.53 4.225 ;
     RECT  29.415 4.081 32.346 4.225 ;
     RECT  54.108 3.955 59.274 4.225 ;
     RECT  53.856 4.225 59.274 4.261 ;
     RECT  53.856 4.261 59.742 4.379 ;
     RECT  39.924 4.109 51.57 4.415 ;
     RECT  52.38 3.911 52.47 4.415 ;
     RECT  53.856 4.379 56.898 4.531 ;
     RECT  57.636 4.379 59.742 4.531 ;
     RECT  53.748 4.531 56.898 4.559 ;
     RECT  10.908 4.181 12.006 4.621 ;
     RECT  10.908 4.621 12.15 4.651 ;
     RECT  13.215 4.225 13.878 4.651 ;
     RECT  17.424 4.225 32.346 4.657 ;
     RECT  10.908 4.651 13.878 4.685 ;
     RECT  10.908 4.685 13.59 4.691 ;
     RECT  15.732 4.657 15.75 4.729 ;
     RECT  16.488 4.657 32.346 4.729 ;
     RECT  15.732 4.729 32.346 4.765 ;
     RECT  33.12 4.109 39.042 4.765 ;
     RECT  52.38 4.415 52.398 4.801 ;
     RECT  53.748 4.559 55.314 4.801 ;
     RECT  15.732 4.765 39.042 4.829 ;
     RECT  10.908 4.691 12.222 4.919 ;
     RECT  52.308 4.801 52.398 4.919 ;
     RECT  9.648 4.181 9.99 4.955 ;
     RECT  53.676 4.801 55.314 4.955 ;
     RECT  15.732 4.829 29.697 4.973 ;
     RECT  56.232 4.559 56.898 5.063 ;
     RECT  9.648 4.955 9.81 5.071 ;
     RECT  14.796 4.999 14.814 5.099 ;
     RECT  53.676 4.955 54.846 5.099 ;
     RECT  15.732 4.973 17.226 5.197 ;
     RECT  30.564 4.829 39.042 5.269 ;
     RECT  39.96 4.415 51.57 5.269 ;
     RECT  53.676 5.099 54.666 5.333 ;
     RECT  53.676 5.333 54.594 5.341 ;
     RECT  18.144 4.973 29.697 5.459 ;
     RECT  30.564 5.269 51.57 5.467 ;
     RECT  57.636 4.531 60.066 5.495 ;
     RECT  14.616 5.461 14.634 5.501 ;
     RECT  15.516 5.197 17.226 5.501 ;
     RECT  9.612 5.071 9.81 5.575 ;
     RECT  13.215 4.691 13.497 5.701 ;
     RECT  30.564 5.467 52.218 5.701 ;
     RECT  9.18 5.575 9.81 5.737 ;
     RECT  9.072 5.737 9.81 5.773 ;
     RECT  10.908 4.919 12.114 5.773 ;
     RECT  13.176 5.701 13.497 5.773 ;
     RECT  8.82 5.773 9.81 5.845 ;
     RECT  10.908 5.773 13.497 5.845 ;
     RECT  15.516 5.501 16.866 5.845 ;
     RECT  56.268 5.063 56.898 5.845 ;
     RECT  18.324 5.459 29.697 5.885 ;
     RECT  8.82 5.845 13.497 5.995 ;
     RECT  53.604 5.341 54.594 6.007 ;
     RECT  55.548 5.845 56.898 6.007 ;
     RECT  53.388 6.007 54.594 6.079 ;
     RECT  55.44 6.007 56.898 6.079 ;
     RECT  18.54 5.885 29.697 6.091 ;
     RECT  30.564 5.701 52.434 6.091 ;
     RECT  7.815 2.413 8.097 6.115 ;
     RECT  8.82 5.995 14.094 6.115 ;
     RECT  7.815 6.115 14.094 6.235 ;
     RECT  18.54 6.091 52.434 6.235 ;
     RECT  7.815 6.235 14.202 6.241 ;
     RECT  15.048 5.845 16.866 6.241 ;
     RECT  7.815 6.241 16.866 6.277 ;
     RECT  7.632 6.277 16.866 6.313 ;
     RECT  7.632 6.313 17.046 6.349 ;
     RECT  7.632 6.349 17.262 6.385 ;
     RECT  57.708 5.495 60.066 6.385 ;
     RECT  53.388 6.079 56.898 6.421 ;
     RECT  57.636 6.385 60.066 6.421 ;
     RECT  61.815 2.413 62.097 6.421 ;
     RECT  18.54 6.235 52.614 6.511 ;
     RECT  53.388 6.421 60.066 6.511 ;
     RECT  18.54 6.511 60.066 6.583 ;
     RECT  60.84 5.845 60.858 6.583 ;
     RECT  63.936 6.511 63.954 6.583 ;
     RECT  7.632 6.385 17.766 6.655 ;
     RECT  63.9 6.583 63.954 6.691 ;
     RECT  5.148 6.511 5.166 6.809 ;
     RECT  7.524 6.655 17.766 6.811 ;
     RECT  18.54 6.583 60.858 6.811 ;
     RECT  7.524 6.811 60.858 6.817 ;
     RECT  61.776 6.421 62.097 6.817 ;
     RECT  7.416 6.817 62.097 7.123 ;
     RECT  6.948 7.123 62.097 7.231 ;
     RECT  6.948 7.231 62.73 7.277 ;
     RECT  63.828 6.691 63.954 7.373 ;
     RECT  63.828 7.373 63.918 7.531 ;
     RECT  6.948 7.277 62.19 7.591 ;
     RECT  63.252 7.531 63.918 7.661 ;
     RECT  6.264 7.591 62.19 7.735 ;
     RECT  4.788 6.817 4.806 7.861 ;
     RECT  3.96 7.699 3.978 7.889 ;
     RECT  6.12 7.735 62.19 7.889 ;
     RECT  4.788 7.861 5.094 7.933 ;
     RECT  4.5 7.933 5.094 7.963 ;
     RECT  6.12 7.889 11.322 7.963 ;
     RECT  63.252 7.661 63.882 8.045 ;
     RECT  61.815 7.889 62.19 8.203 ;
     RECT  63.252 8.045 63.846 8.203 ;
     RECT  12.096 7.889 60.858 8.267 ;
     RECT  12.096 8.267 31.122 8.573 ;
     RECT  12.096 8.573 16.578 8.699 ;
     RECT  31.932 8.267 60.858 8.879 ;
     RECT  40.14 8.879 60.858 8.941 ;
     RECT  61.815 8.203 63.846 8.941 ;
     RECT  40.14 8.941 63.846 8.969 ;
     RECT  4.5 7.963 11.322 8.977 ;
     RECT  12.096 8.699 13.626 8.977 ;
     RECT  40.14 8.969 58.914 9.041 ;
     RECT  40.14 9.041 53.802 9.077 ;
     RECT  54.54 9.041 58.914 9.101 ;
     RECT  43.56 9.077 53.802 9.113 ;
     RECT  54.54 9.101 54.666 9.113 ;
     RECT  17.316 8.573 31.122 9.121 ;
     RECT  31.932 8.879 39.366 9.121 ;
     RECT  43.596 9.113 53.802 9.275 ;
     RECT  3.744 7.897 3.762 9.283 ;
     RECT  14.508 8.699 16.578 9.319 ;
     RECT  17.316 9.121 39.366 9.319 ;
     RECT  14.508 9.319 39.366 9.389 ;
     RECT  59.652 8.969 63.846 9.419 ;
     RECT  4.5 8.977 13.626 9.517 ;
     RECT  14.508 9.389 39.006 9.517 ;
     RECT  40.14 9.077 42.786 9.545 ;
     RECT  3.528 9.283 3.762 9.661 ;
     RECT  4.5 9.517 39.006 9.661 ;
     RECT  55.656 9.101 58.914 9.751 ;
     RECT  59.652 9.419 62.097 9.751 ;
     RECT  3.528 9.661 39.006 9.851 ;
     RECT  3.528 9.851 38.934 9.859 ;
     RECT  43.704 9.275 53.802 9.895 ;
     RECT  54.648 9.113 54.666 9.895 ;
     RECT  64.692 8.683 64.71 9.959 ;
     RECT  63.252 9.419 63.846 10.049 ;
     RECT  2.415 2.413 2.697 10.057 ;
     RECT  3.456 9.859 38.934 10.057 ;
     RECT  55.656 9.751 62.097 10.093 ;
     RECT  2.415 10.057 38.934 10.121 ;
     RECT  41.796 9.545 42.786 10.165 ;
     RECT  43.704 9.895 54.666 10.165 ;
     RECT  55.548 10.093 62.097 10.165 ;
     RECT  41.796 10.165 54.666 10.193 ;
     RECT  40.14 9.545 40.95 10.291 ;
     RECT  41.796 10.193 53.946 10.291 ;
     RECT  63.828 10.049 63.846 10.319 ;
     RECT  2.415 10.121 38.394 10.355 ;
     RECT  18.576 10.355 38.394 10.391 ;
     RECT  55.512 10.165 62.097 10.435 ;
     RECT  40.032 10.291 53.946 10.561 ;
     RECT  55.404 10.435 62.097 10.561 ;
     RECT  39.924 10.561 53.946 10.661 ;
     RECT  39.924 10.661 49.266 10.696 ;
     RECT  18.576 10.391 27.018 10.733 ;
     RECT  26.64 10.733 27.018 10.769 ;
     RECT  39.744 10.696 49.266 10.831 ;
     RECT  27.792 10.391 38.394 11.011 ;
     RECT  50.004 10.661 53.946 11.011 ;
     RECT  55.044 10.561 62.097 11.011 ;
     RECT  39.672 10.831 49.266 11.101 ;
     RECT  27.792 11.011 38.574 11.137 ;
     RECT  39.456 11.101 49.266 11.137 ;
     RECT  2.415 10.355 17.838 11.227 ;
     RECT  26.712 10.769 27.018 11.407 ;
     RECT  27.792 11.137 49.266 11.407 ;
     RECT  26.712 11.407 49.266 11.435 ;
     RECT  2.34 11.227 17.838 11.515 ;
     RECT  18.576 10.733 25.578 11.515 ;
     RECT  37.044 11.435 49.266 11.515 ;
     RECT  50.004 11.011 62.097 11.515 ;
     RECT  37.044 11.515 62.514 11.669 ;
     RECT  2.34 11.515 25.578 11.785 ;
     RECT  26.712 11.435 36.306 11.785 ;
     RECT  37.044 11.669 62.406 11.939 ;
     RECT  37.044 11.939 59.814 12.119 ;
     RECT  2.34 11.785 36.306 12.181 ;
     RECT  37.044 12.119 38.898 12.181 ;
     RECT  2.34 12.181 38.898 12.245 ;
     RECT  2.34 12.245 27.486 12.281 ;
     RECT  28.872 12.245 38.898 12.289 ;
     RECT  26.748 12.281 27.486 12.365 ;
     RECT  28.872 12.289 33.39 12.389 ;
     RECT  60.552 11.939 62.406 12.479 ;
     RECT  2.34 12.281 26.01 12.515 ;
     RECT  39.636 12.119 59.814 12.721 ;
     RECT  60.552 12.479 62.097 12.721 ;
     RECT  34.128 12.289 38.898 12.901 ;
     RECT  39.636 12.721 62.097 12.901 ;
     RECT  28.872 12.389 33.282 12.991 ;
     RECT  34.128 12.901 62.097 13.055 ;
     RECT  26.748 12.365 27.45 13.099 ;
     RECT  28.62 12.991 33.282 13.099 ;
     RECT  28.548 13.099 33.282 13.135 ;
     RECT  26.748 13.099 27.594 13.171 ;
     RECT  28.476 13.135 33.39 13.243 ;
     RECT  26.712 13.171 27.594 13.261 ;
     RECT  28.44 13.243 33.39 13.261 ;
     RECT  34.128 13.055 46.854 13.261 ;
     RECT  26.712 13.261 27.666 13.297 ;
     RECT  28.44 13.261 46.854 13.297 ;
     RECT  26.712 13.297 46.854 13.325 ;
     RECT  47.7 13.055 62.097 13.441 ;
     RECT  2.34 12.515 25.758 13.627 ;
     RECT  26.748 13.325 46.854 13.667 ;
     RECT  34.164 13.667 46.854 13.945 ;
     RECT  47.7 13.441 62.334 13.981 ;
     RECT  34.164 13.945 46.89 14.071 ;
     RECT  47.7 13.981 62.514 14.071 ;
     RECT  34.164 14.071 62.514 14.135 ;
     RECT  2.34 13.627 25.866 14.251 ;
     RECT  2.34 14.251 25.938 14.347 ;
     RECT  26.748 13.667 33.39 14.347 ;
     RECT  2.34 14.347 33.39 14.485 ;
     RECT  34.164 14.135 62.406 14.485 ;
     RECT  2.34 14.485 62.406 14.909 ;
     RECT  2.34 14.909 62.154 15.005 ;
     RECT  2.34 15.005 62.097 15.179 ;
     RECT  63.288 15.601 63.306 15.691 ;
     RECT  2.34 15.179 33.354 15.961 ;
     RECT  34.452 15.179 62.097 16.025 ;
     RECT  2.34 15.961 33.498 16.133 ;
     RECT  63.288 15.691 63.882 16.231 ;
     RECT  34.452 16.025 39.006 16.303 ;
     RECT  63.288 16.231 63.918 16.303 ;
     RECT  63.288 16.303 63.954 16.363 ;
     RECT  34.38 16.303 39.006 16.501 ;
     RECT  63.252 16.363 63.954 16.501 ;
     RECT  2.34 16.133 33.174 16.529 ;
     RECT  63.252 16.501 63.99 16.877 ;
     RECT  33.912 16.501 39.006 16.891 ;
     RECT  39.744 16.025 62.097 16.891 ;
     RECT  2.34 16.529 31.518 17.035 ;
     RECT  0.54 16.339 0.558 17.131 ;
     RECT  33.912 16.891 62.097 17.149 ;
     RECT  63.252 16.877 63.918 17.149 ;
     RECT  33.912 17.149 63.918 17.249 ;
     RECT  0.54 17.131 1.278 17.261 ;
     RECT  2.304 17.035 31.518 17.311 ;
     RECT  32.292 16.529 33.174 17.311 ;
     RECT  63.828 17.249 63.918 17.357 ;
     RECT  63.828 17.357 63.882 17.453 ;
     RECT  0.144 17.371 0.162 17.549 ;
     RECT  64.692 17.515 64.71 17.707 ;
     RECT  64.656 17.707 64.71 17.803 ;
     RECT  2.304 17.311 33.174 17.851 ;
     RECT  33.912 17.249 62.694 17.851 ;
     RECT  64.62 17.803 64.71 17.879 ;
     RECT  64.656 17.879 64.71 17.915 ;
     RECT  2.304 17.851 62.694 18.031 ;
     RECT  2.304 18.031 62.73 18.091 ;
     RECT  63.828 17.453 63.846 18.091 ;
     RECT  1.152 17.261 1.278 18.221 ;
     RECT  2.304 18.091 63.846 18.221 ;
     RECT  48.24 18.221 62.097 18.257 ;
     RECT  2.304 18.221 38.97 18.379 ;
     RECT  2.268 18.379 38.97 18.599 ;
     RECT  64.692 17.915 64.71 18.667 ;
     RECT  1.152 18.221 1.17 18.701 ;
     RECT  48.276 18.257 62.097 18.797 ;
     RECT  64.656 18.667 64.71 18.869 ;
     RECT  2.268 18.599 31.554 18.955 ;
     RECT  62.892 18.221 63.846 18.959 ;
     RECT  2.196 18.955 31.554 18.995 ;
     RECT  63.792 18.959 63.846 19.003 ;
     RECT  63.792 19.003 63.882 19.085 ;
     RECT  32.292 18.599 38.97 19.111 ;
     RECT  39.708 18.221 46.89 19.111 ;
     RECT  63.792 19.085 63.846 19.139 ;
     RECT  32.292 19.111 47.286 19.265 ;
     RECT  64.692 18.869 64.71 19.409 ;
     RECT  63.828 19.139 63.846 19.499 ;
     RECT  62.892 18.959 62.91 19.571 ;
     RECT  2.304 18.995 31.554 19.615 ;
     RECT  32.292 19.265 46.746 19.615 ;
     RECT  2.304 19.615 46.746 19.643 ;
     RECT  33.948 19.643 46.746 19.679 ;
     RECT  0.54 19.651 0.558 19.771 ;
     RECT  34.02 19.679 46.746 19.805 ;
     RECT  34.02 19.805 39.186 19.913 ;
     RECT  0.144 19.771 0.558 19.949 ;
     RECT  47.52 19.651 47.538 20.047 ;
     RECT  48.456 18.797 62.097 20.047 ;
     RECT  40.104 19.805 46.746 20.281 ;
     RECT  47.52 20.047 62.097 20.281 ;
     RECT  2.304 19.643 33.174 20.309 ;
     RECT  40.104 20.281 62.097 20.525 ;
     RECT  34.344 19.913 39.186 20.551 ;
     RECT  40.104 20.525 58.77 20.551 ;
     RECT  0.54 19.949 0.558 20.621 ;
     RECT  28.872 20.309 33.174 20.695 ;
     RECT  34.344 20.551 58.77 20.695 ;
     RECT  0.144 20.923 0.198 21.127 ;
     RECT  2.304 20.309 28.026 21.127 ;
     RECT  28.872 20.695 58.77 21.127 ;
     RECT  2.304 21.127 58.77 21.155 ;
     RECT  38.844 21.155 58.77 21.263 ;
     RECT  0.108 21.127 0.198 21.389 ;
     RECT  0.18 21.389 0.198 21.437 ;
     RECT  2.304 21.155 37.818 21.532 ;
     RECT  38.88 21.263 58.77 21.541 ;
     RECT  59.652 20.525 62.097 21.541 ;
     RECT  2.268 21.532 37.818 21.739 ;
     RECT  2.196 21.739 37.818 22.037 ;
     RECT  2.268 22.037 37.818 22.171 ;
     RECT  38.88 21.541 62.097 22.207 ;
     RECT  2.268 22.171 37.854 22.219 ;
     RECT  38.736 22.207 62.097 22.219 ;
     RECT  2.268 22.219 62.097 22.379 ;
     RECT  2.268 22.379 33.426 22.733 ;
     RECT  0.54 22.081 0.558 22.783 ;
     RECT  0.108 22.783 0.558 22.829 ;
     RECT  34.272 22.379 62.097 23.323 ;
     RECT  2.304 22.733 33.426 23.371 ;
     RECT  34.272 23.323 62.19 23.371 ;
     RECT  2.304 23.371 62.19 23.611 ;
     RECT  2.268 23.611 62.19 23.891 ;
     RECT  0.54 22.829 0.558 24.241 ;
     RECT  0.504 24.241 0.558 24.653 ;
     RECT  2.268 23.891 54.882 24.665 ;
     RECT  2.304 24.665 54.882 24.673 ;
     RECT  55.692 23.891 62.19 24.673 ;
     RECT  2.304 24.673 62.19 24.971 ;
     RECT  2.304 24.971 36.846 25.757 ;
     RECT  63.324 25.591 63.342 25.789 ;
     RECT  27.396 25.757 36.846 25.861 ;
     RECT  2.304 25.757 26.658 25.963 ;
     RECT  27.396 25.861 36.918 25.979 ;
     RECT  2.268 25.963 26.658 26.015 ;
     RECT  2.304 26.015 26.658 26.051 ;
     RECT  27.612 25.979 36.918 26.053 ;
     RECT  37.692 24.971 62.19 26.053 ;
     RECT  63.324 25.789 63.882 26.053 ;
     RECT  27.612 26.053 62.19 26.131 ;
     RECT  63.288 26.053 63.882 26.131 ;
     RECT  0.54 24.653 0.558 26.285 ;
     RECT  27.612 26.131 63.882 26.285 ;
     RECT  64.692 26.155 64.71 26.357 ;
     RECT  63.252 26.285 63.882 26.668 ;
     RECT  2.304 26.051 26.586 26.797 ;
     RECT  27.612 26.285 62.19 26.861 ;
     RECT  2.232 26.797 26.586 26.905 ;
     RECT  2.232 26.905 26.694 26.941 ;
     RECT  27.612 26.861 30.618 26.941 ;
     RECT  2.232 26.941 30.618 27.053 ;
     RECT  63.252 26.668 63.918 27.053 ;
     RECT  63.252 27.053 63.882 27.131 ;
     RECT  31.716 26.861 62.19 27.167 ;
     RECT  31.716 27.167 31.806 27.329 ;
     RECT  63.288 27.131 63.882 27.437 ;
     RECT  31.716 27.329 31.734 27.607 ;
     RECT  2.304 27.053 30.618 27.643 ;
     RECT  31.356 27.607 31.734 27.643 ;
     RECT  64.62 27.499 64.638 27.677 ;
     RECT  63.792 27.437 63.882 27.821 ;
     RECT  2.304 27.643 31.734 27.905 ;
     RECT  0.324 27.787 0.342 27.917 ;
     RECT  2.376 27.905 31.734 28.175 ;
     RECT  32.832 27.167 62.19 28.291 ;
     RECT  63.792 27.821 63.846 28.363 ;
     RECT  2.415 28.175 31.734 28.381 ;
     RECT  32.616 28.291 62.19 28.381 ;
     RECT  64.692 28.267 64.71 28.459 ;
     RECT  63.252 28.363 63.846 28.747 ;
     RECT  63.216 28.747 63.846 28.949 ;
     RECT  2.415 28.381 62.19 29.219 ;
     RECT  64.656 28.459 64.71 29.219 ;
     RECT  64.656 29.219 64.674 29.489 ;
     RECT  3.492 29.219 62.19 29.597 ;
     RECT  63.828 28.949 63.846 29.759 ;
     RECT  2.415 29.219 2.697 29.995 ;
     RECT  3.492 29.597 46.458 29.995 ;
     RECT  2.415 29.995 46.458 30.451 ;
     RECT  47.232 29.597 62.19 30.451 ;
     RECT  2.415 30.451 62.19 30.721 ;
     RECT  0.108 30.685 0.126 30.883 ;
     RECT  2.415 30.721 62.514 30.955 ;
     RECT  0.108 30.883 0.558 31.277 ;
     RECT  0.54 31.277 0.558 31.373 ;
     RECT  2.304 30.955 62.514 31.693 ;
     RECT  2.268 31.693 62.514 31.793 ;
     RECT  2.268 31.793 36.09 31.955 ;
     RECT  0.108 32.467 0.126 32.525 ;
     RECT  30.744 31.955 36.09 32.575 ;
     RECT  30.744 32.575 36.198 32.611 ;
     RECT  36.936 31.793 62.514 32.611 ;
     RECT  30.744 32.611 62.514 32.801 ;
     RECT  2.268 31.955 29.97 32.971 ;
     RECT  0.504 32.881 0.522 33.043 ;
     RECT  30.744 32.801 62.154 33.071 ;
     RECT  0.504 33.043 0.558 33.101 ;
     RECT  2.232 32.971 29.97 33.151 ;
     RECT  0.504 33.101 0.522 33.197 ;
     RECT  2.232 33.151 30.006 33.349 ;
     RECT  30.744 33.071 62.097 33.349 ;
     RECT  2.232 33.349 62.097 33.539 ;
     RECT  2.232 33.539 37.854 33.547 ;
     RECT  2.196 33.547 37.854 33.584 ;
     RECT  0.324 33.739 0.342 33.835 ;
     RECT  0.108 33.835 0.342 33.869 ;
     RECT  38.628 33.539 62.097 33.917 ;
     RECT  0.108 33.869 0.126 34.157 ;
     RECT  2.268 33.584 37.854 34.223 ;
     RECT  2.34 34.223 37.854 34.357 ;
     RECT  38.628 33.917 58.482 34.357 ;
     RECT  59.256 33.917 62.097 34.501 ;
     RECT  2.34 34.357 58.482 34.529 ;
     RECT  2.34 34.529 4.302 34.655 ;
     RECT  5.076 34.529 58.482 34.861 ;
     RECT  59.256 34.501 62.154 34.861 ;
     RECT  5.076 34.861 62.154 35.069 ;
     RECT  2.415 34.655 4.302 35.581 ;
     RECT  5.076 35.069 62.097 35.581 ;
     RECT  2.415 35.581 62.097 35.807 ;
     RECT  42.408 35.807 62.097 35.885 ;
     RECT  2.415 35.807 40.806 36.077 ;
     RECT  2.415 36.077 4.518 36.149 ;
     RECT  42.552 35.885 62.097 36.149 ;
     RECT  42.552 36.149 58.662 36.419 ;
     RECT  59.4 36.149 62.097 36.517 ;
     RECT  2.415 36.149 4.41 36.545 ;
     RECT  5.256 36.077 40.806 36.661 ;
     RECT  41.616 35.807 41.67 36.661 ;
     RECT  42.552 36.419 58.446 36.661 ;
     RECT  3.42 36.545 4.41 36.689 ;
     RECT  5.256 36.661 41.67 36.701 ;
     RECT  5.256 36.701 30.042 36.923 ;
     RECT  3.528 36.689 4.41 36.931 ;
     RECT  5.256 36.923 25.866 36.931 ;
     RECT  59.4 36.517 62.118 36.931 ;
     RECT  26.856 36.923 30.042 37.049 ;
     RECT  27.252 37.049 30.042 37.085 ;
     RECT  30.816 36.701 41.67 37.363 ;
     RECT  42.48 36.661 58.446 37.363 ;
     RECT  59.4 36.931 62.154 37.363 ;
     RECT  3.528 36.931 25.866 37.391 ;
     RECT  27.36 37.085 30.042 37.435 ;
     RECT  30.816 37.363 62.154 37.435 ;
     RECT  27.36 37.435 62.154 37.625 ;
     RECT  28.224 37.625 62.154 37.697 ;
     RECT  28.224 37.697 32.526 37.769 ;
     RECT  27.36 37.625 27.45 37.859 ;
     RECT  28.224 37.769 32.022 37.859 ;
     RECT  3.636 37.391 25.866 37.895 ;
     RECT  33.3 37.697 62.154 37.895 ;
     RECT  28.26 37.859 32.022 38.003 ;
     RECT  3.636 37.895 4.842 38.129 ;
     RECT  10.188 37.895 25.866 38.245 ;
     RECT  27.432 37.859 27.45 38.395 ;
     RECT  3.924 38.129 4.842 38.471 ;
     RECT  33.3 37.895 62.097 38.479 ;
     RECT  28.548 38.003 32.022 38.551 ;
     RECT  5.724 37.895 9.45 38.641 ;
     RECT  10.188 38.245 26.118 38.641 ;
     RECT  28.548 38.551 32.166 38.785 ;
     RECT  5.724 38.641 26.298 38.813 ;
     RECT  27.432 38.395 27.486 38.821 ;
     RECT  28.404 38.785 32.166 38.821 ;
     RECT  4.032 38.471 4.842 38.827 ;
     RECT  5.724 38.813 23.166 38.849 ;
     RECT  12.816 38.849 23.166 38.939 ;
     RECT  12.816 38.939 16.794 38.975 ;
     RECT  33.048 38.479 62.097 39.019 ;
     RECT  33.012 39.019 62.097 39.091 ;
     RECT  32.94 39.091 62.097 39.209 ;
     RECT  27.432 38.821 32.166 39.217 ;
     RECT  33.408 39.209 62.097 39.245 ;
     RECT  5.724 38.849 11.97 39.251 ;
     RECT  34.38 39.245 62.097 39.281 ;
     RECT  4.032 38.827 4.914 39.289 ;
     RECT  5.724 39.251 7.038 39.289 ;
     RECT  12.816 38.975 16.758 39.317 ;
     RECT  34.38 39.281 38.214 39.317 ;
     RECT  23.94 38.813 26.298 39.361 ;
     RECT  23.94 39.361 26.622 39.487 ;
     RECT  27.432 39.217 32.67 39.487 ;
     RECT  4.032 39.289 7.038 39.515 ;
     RECT  13.104 39.317 16.758 39.515 ;
     RECT  38.988 39.281 62.097 39.515 ;
     RECT  17.532 38.939 23.166 39.631 ;
     RECT  23.94 39.487 32.67 39.631 ;
     RECT  15.192 39.515 16.758 39.757 ;
     RECT  17.532 39.631 32.67 39.757 ;
     RECT  38.988 39.515 46.098 39.785 ;
     RECT  15.192 39.757 32.67 39.821 ;
     RECT  7.815 39.251 11.97 39.865 ;
     RECT  46.908 39.515 62.097 39.869 ;
     RECT  33.408 39.245 33.462 40.019 ;
     RECT  4.14 39.515 7.038 40.055 ;
     RECT  17.856 39.821 32.67 40.055 ;
     RECT  38.988 39.785 45.897 40.055 ;
     RECT  48.564 39.869 62.097 40.091 ;
     RECT  34.38 39.317 35.097 40.123 ;
     RECT  4.284 40.055 7.038 40.127 ;
     RECT  25.056 40.055 32.67 40.135 ;
     RECT  4.464 40.127 7.038 40.163 ;
     RECT  4.68 40.163 7.038 40.171 ;
     RECT  13.104 39.515 14.202 40.171 ;
     RECT  12.996 40.171 14.202 40.289 ;
     RECT  25.056 40.135 33.066 40.289 ;
     RECT  38.988 40.055 43.542 40.289 ;
     RECT  46.908 39.869 47.826 40.297 ;
     RECT  25.056 40.289 32.454 40.325 ;
     RECT  38.988 40.289 43.47 40.369 ;
     RECT  34.2 40.123 35.097 40.405 ;
     RECT  4.68 40.171 7.074 40.441 ;
     RECT  7.815 39.865 12.114 40.441 ;
     RECT  35.928 39.317 38.214 40.531 ;
     RECT  38.952 40.369 43.47 40.531 ;
     RECT  44.424 40.055 45.897 40.555 ;
     RECT  46.764 40.297 47.826 40.555 ;
     RECT  13.104 40.289 14.202 40.567 ;
     RECT  13.104 40.567 14.238 40.603 ;
     RECT  15.336 39.821 16.902 40.603 ;
     RECT  35.928 40.531 43.47 40.603 ;
     RECT  33.984 40.405 35.097 40.639 ;
     RECT  35.82 40.603 43.47 40.639 ;
     RECT  4.68 40.441 12.15 40.711 ;
     RECT  13.104 40.603 16.902 40.711 ;
     RECT  17.856 40.055 24.297 40.829 ;
     RECT  25.2 40.325 32.454 40.829 ;
     RECT  44.424 40.555 47.826 40.873 ;
     RECT  48.6 40.091 62.097 40.873 ;
     RECT  25.2 40.829 32.274 40.973 ;
     RECT  13.104 40.711 17.082 40.981 ;
     RECT  17.856 40.829 17.874 40.981 ;
     RECT  33.984 40.639 43.47 41.035 ;
     RECT  33.336 41.035 43.47 41.071 ;
     RECT  44.424 40.873 62.097 41.071 ;
     RECT  33.336 41.071 62.097 41.099 ;
     RECT  18.615 40.829 24.297 41.107 ;
     RECT  25.2 40.973 26.946 41.107 ;
     RECT  13.104 40.981 17.874 41.135 ;
     RECT  18.615 41.107 26.946 41.135 ;
     RECT  27.828 40.973 32.274 41.135 ;
     RECT  27.9 41.135 32.274 41.279 ;
     RECT  13.104 41.135 17.694 41.405 ;
     RECT  33.336 41.099 56.898 41.405 ;
     RECT  33.336 41.405 45.897 41.521 ;
     RECT  14.868 41.405 17.694 41.639 ;
     RECT  27.936 41.279 32.274 41.683 ;
     RECT  33.156 41.521 45.897 41.683 ;
     RECT  27.936 41.683 45.897 41.711 ;
     RECT  4.68 40.711 12.33 41.755 ;
     RECT  13.104 41.405 14.13 41.755 ;
     RECT  18.615 41.135 26.91 41.755 ;
     RECT  18.504 41.755 26.91 41.899 ;
     RECT  4.68 41.755 14.13 41.945 ;
     RECT  18.072 41.899 26.91 41.945 ;
     RECT  64.08 41.611 64.098 41.953 ;
     RECT  14.868 41.639 17.262 42.053 ;
     RECT  46.872 41.405 56.898 42.061 ;
     RECT  57.672 41.099 62.097 42.061 ;
     RECT  9.288 41.945 14.13 42.151 ;
     RECT  14.868 42.053 15.858 42.151 ;
     RECT  18.576 41.945 26.91 42.187 ;
     RECT  46.872 42.061 62.097 42.187 ;
     RECT  46.872 42.187 62.442 42.215 ;
     RECT  9.288 42.151 15.858 42.221 ;
     RECT  28.044 41.711 45.897 42.331 ;
     RECT  47.304 42.215 62.442 42.331 ;
     RECT  28.044 42.331 45.954 42.421 ;
     RECT  9.288 42.221 12.15 42.449 ;
     RECT  18.576 42.187 27.162 42.457 ;
     RECT  28.044 42.421 46.458 42.457 ;
     RECT  47.304 42.331 62.73 42.493 ;
     RECT  63.864 41.953 64.098 42.493 ;
     RECT  47.304 42.493 64.098 42.701 ;
     RECT  4.68 41.945 8.55 42.715 ;
     RECT  9.288 42.449 12.006 42.715 ;
     RECT  18.576 42.457 46.458 42.719 ;
     RECT  4.68 42.715 12.006 42.727 ;
     RECT  12.888 42.221 15.858 42.871 ;
     RECT  16.596 42.053 17.262 42.871 ;
     RECT  25.128 42.719 46.458 42.961 ;
     RECT  47.304 42.701 62.442 42.961 ;
     RECT  12.888 42.871 17.262 43.069 ;
     RECT  12.816 43.069 17.262 43.105 ;
     RECT  18.576 42.719 24.354 43.105 ;
     RECT  25.128 42.961 62.442 43.331 ;
     RECT  4.572 42.727 12.006 43.339 ;
     RECT  12.816 43.105 24.354 43.339 ;
     RECT  4.572 43.339 24.354 43.501 ;
     RECT  25.128 43.331 62.097 43.501 ;
     RECT  63.288 42.701 64.098 43.757 ;
     RECT  63.864 43.757 64.098 43.949 ;
     RECT  4.572 43.501 62.097 44.113 ;
     RECT  4.572 44.113 62.766 44.249 ;
     RECT  4.572 44.249 6.678 44.375 ;
     RECT  13.032 44.249 35.154 44.375 ;
     RECT  13.176 44.375 35.154 44.381 ;
     RECT  63.864 43.949 63.954 44.429 ;
     RECT  35.892 44.249 62.766 44.69 ;
     RECT  35.928 44.69 62.766 44.725 ;
     RECT  63.864 44.429 63.918 44.725 ;
     RECT  35.928 44.725 63.918 44.909 ;
     RECT  35.928 44.909 62.73 45.005 ;
     RECT  13.176 44.381 33.966 45.053 ;
     RECT  64.692 44.011 64.71 45.067 ;
     RECT  7.632 44.249 12.15 45.121 ;
     RECT  13.176 45.053 15.246 45.121 ;
     RECT  7.632 45.121 15.246 45.149 ;
     RECT  35.928 45.005 62.694 45.293 ;
     RECT  34.776 44.381 35.154 45.301 ;
     RECT  16.092 45.053 33.966 45.355 ;
     RECT  16.092 45.355 34.038 45.391 ;
     RECT  34.776 45.301 35.19 45.391 ;
     RECT  16.092 45.391 35.19 45.419 ;
     RECT  36.504 45.293 62.694 45.491 ;
     RECT  7.632 45.149 15.102 45.563 ;
     RECT  7.632 45.563 12.474 45.691 ;
     RECT  16.092 45.419 35.097 45.725 ;
     RECT  36.54 45.491 62.694 45.805 ;
     RECT  63.828 44.909 63.918 45.805 ;
     RECT  64.656 45.067 64.71 45.869 ;
     RECT  7.524 45.691 12.474 45.931 ;
     RECT  36.54 45.805 63.918 46.003 ;
     RECT  64.656 45.869 64.674 46.003 ;
     RECT  7.452 45.931 12.474 46.027 ;
     RECT  13.215 45.563 15.102 46.075 ;
     RECT  16.092 45.725 24.498 46.075 ;
     RECT  36.54 46.003 64.674 46.309 ;
     RECT  36.468 46.309 64.674 46.337 ;
     RECT  7.416 46.027 12.474 46.345 ;
     RECT  13.215 46.075 24.498 46.345 ;
     RECT  36.468 46.337 54.702 46.345 ;
     RECT  5.688 44.375 6.678 46.381 ;
     RECT  7.416 46.345 24.498 46.381 ;
     RECT  36.072 46.345 54.702 46.381 ;
     RECT  4.572 44.375 4.59 46.459 ;
     RECT  5.688 46.381 24.498 46.471 ;
     RECT  4.464 46.459 4.59 46.499 ;
     RECT  36 46.381 54.702 46.499 ;
     RECT  25.56 45.725 35.097 46.507 ;
     RECT  4.464 46.499 4.482 46.535 ;
     RECT  5.544 46.471 24.498 46.579 ;
     RECT  48.564 46.499 54.702 46.607 ;
     RECT  5.544 46.579 24.606 46.615 ;
     RECT  48.708 46.607 54.486 46.643 ;
     RECT  5.544 46.615 24.786 46.741 ;
     RECT  25.56 46.507 35.19 46.741 ;
     RECT  36 46.499 47.754 46.741 ;
     RECT  5.544 46.741 47.754 46.769 ;
     RECT  21.492 46.769 47.754 46.841 ;
     RECT  55.656 46.337 64.674 46.891 ;
     RECT  48.852 46.643 54.486 47.147 ;
     RECT  5.544 46.769 20.754 47.183 ;
     RECT  39.996 46.841 47.754 47.183 ;
     RECT  55.656 46.891 64.71 47.191 ;
     RECT  55.584 47.191 64.71 47.281 ;
     RECT  11.952 47.183 20.754 47.515 ;
     RECT  21.492 46.841 39.258 47.515 ;
     RECT  5.544 47.183 11.178 47.695 ;
     RECT  11.952 47.515 39.258 47.755 ;
     RECT  40.215 47.183 47.754 47.821 ;
     RECT  11.952 47.755 39.474 47.849 ;
     RECT  11.952 47.849 39.258 47.885 ;
     RECT  55.368 47.281 64.71 47.885 ;
     RECT  11.952 47.885 39.222 47.891 ;
     RECT  5.508 47.695 11.178 47.965 ;
     RECT  11.952 47.891 26.262 47.965 ;
     RECT  48.96 47.147 54.162 47.965 ;
     RECT  40.215 47.821 47.826 48.029 ;
     RECT  27.072 47.891 39.222 48.119 ;
     RECT  5.508 47.965 26.262 48.127 ;
     RECT  41.22 48.029 47.826 48.127 ;
     RECT  48.564 47.965 54.162 48.127 ;
     RECT  55.368 47.885 62.694 48.269 ;
     RECT  5.472 48.127 26.262 48.271 ;
     RECT  55.368 48.269 62.658 48.271 ;
     RECT  5.364 48.271 26.262 48.299 ;
     RECT  55.26 48.271 62.658 48.365 ;
     RECT  37.368 48.119 39.222 48.425 ;
     RECT  5.364 48.299 26.19 48.461 ;
     RECT  27.072 48.119 36.486 48.461 ;
     RECT  41.22 48.127 54.162 48.461 ;
     RECT  4.068 48.475 4.086 48.541 ;
     RECT  4.068 48.541 4.266 48.659 ;
     RECT  37.476 48.425 39.222 48.667 ;
     RECT  27.072 48.461 36.162 48.701 ;
     RECT  4.068 48.659 4.086 48.731 ;
     RECT  5.364 48.461 14.31 48.739 ;
     RECT  5.04 48.739 14.31 48.775 ;
     RECT  37.476 48.667 39.366 48.775 ;
     RECT  40.215 48.029 40.497 48.775 ;
     RECT  55.26 48.365 62.622 48.901 ;
     RECT  4.968 48.775 14.31 48.929 ;
     RECT  41.652 48.461 54.162 48.929 ;
     RECT  63.864 47.885 64.71 48.941 ;
     RECT  37.476 48.775 40.497 49.045 ;
     RECT  52.812 48.929 54.162 49.045 ;
     RECT  55.044 48.901 62.622 49.045 ;
     RECT  5.364 48.929 14.31 49.073 ;
     RECT  63.864 48.941 63.954 49.099 ;
     RECT  15.156 48.461 26.19 49.171 ;
     RECT  37.476 49.045 40.554 49.171 ;
     RECT  52.812 49.045 62.622 49.199 ;
     RECT  15.156 49.171 26.262 49.207 ;
     RECT  27.072 48.701 36.09 49.207 ;
     RECT  41.652 48.929 52.074 49.271 ;
     RECT  37.296 49.171 40.554 49.279 ;
     RECT  15.156 49.207 36.09 49.351 ;
     RECT  5.436 49.073 14.31 49.421 ;
     RECT  63.828 49.099 63.954 49.421 ;
     RECT  9.36 49.421 14.31 49.469 ;
     RECT  41.652 49.271 48.006 49.505 ;
     RECT  15.12 49.351 36.09 49.513 ;
     RECT  41.652 49.505 47.826 49.541 ;
     RECT  37.008 49.279 40.554 49.585 ;
     RECT  63.828 49.421 63.846 49.739 ;
     RECT  64.692 48.941 64.71 49.771 ;
     RECT  15.12 49.513 36.27 49.847 ;
     RECT  12.816 49.469 14.31 49.855 ;
     RECT  15.12 49.847 33.714 49.855 ;
     RECT  34.488 49.847 36.27 49.891 ;
     RECT  37.008 49.585 40.878 49.891 ;
     RECT  54.72 49.199 62.622 49.891 ;
     RECT  64.656 49.771 64.71 49.901 ;
     RECT  5.436 49.421 8.55 50.009 ;
     RECT  12.816 49.855 33.714 50.009 ;
     RECT  52.812 49.199 53.658 50.009 ;
     RECT  5.76 50.009 6.066 50.045 ;
     RECT  6.84 50.009 8.55 50.045 ;
     RECT  48.744 49.271 52.074 50.045 ;
     RECT  6.84 50.045 6.858 50.051 ;
     RECT  6.048 50.045 6.066 50.081 ;
     RECT  15.84 50.009 33.714 50.081 ;
     RECT  34.488 49.891 40.878 50.093 ;
     RECT  15.84 50.081 24.297 50.117 ;
     RECT  48.96 50.045 52.074 50.117 ;
     RECT  48.996 50.117 52.074 50.125 ;
     RECT  52.812 50.009 53.622 50.125 ;
     RECT  15.912 50.117 24.297 50.153 ;
     RECT  54.72 49.891 62.694 50.153 ;
     RECT  64.692 49.901 64.71 50.153 ;
     RECT  41.976 49.541 47.826 50.279 ;
     RECT  9.36 49.469 11.934 50.359 ;
     RECT  12.816 50.009 15.066 50.359 ;
     RECT  25.164 50.081 33.714 50.381 ;
     RECT  41.976 50.279 47.286 50.387 ;
     RECT  42.768 50.387 47.286 50.459 ;
     RECT  7.668 50.045 8.55 50.521 ;
     RECT  9.36 50.359 15.066 50.521 ;
     RECT  25.416 50.381 33.714 50.585 ;
     RECT  25.488 50.585 33.714 50.729 ;
     RECT  55.044 50.153 62.55 50.729 ;
     RECT  7.668 50.521 15.066 50.731 ;
     RECT  25.884 50.729 33.714 50.827 ;
     RECT  34.488 50.093 40.497 50.827 ;
     RECT  25.884 50.827 40.497 50.855 ;
     RECT  48.996 50.125 53.622 50.855 ;
     RECT  48.996 50.855 52.938 50.891 ;
     RECT  7.668 50.731 15.174 50.899 ;
     RECT  16.452 50.153 24.297 50.899 ;
     RECT  41.94 50.665 41.958 50.935 ;
     RECT  27.612 50.855 40.497 50.963 ;
     RECT  7.668 50.899 24.297 50.971 ;
     RECT  42.804 50.459 47.286 51.089 ;
     RECT  48.672 50.899 48.69 51.089 ;
     RECT  49.428 50.891 52.938 51.089 ;
     RECT  55.044 50.729 62.298 51.089 ;
     RECT  34.02 50.963 40.497 51.161 ;
     RECT  49.608 51.089 52.938 51.161 ;
     RECT  27.612 50.963 33.174 51.197 ;
     RECT  42.804 51.089 46.782 51.197 ;
     RECT  41.22 50.935 41.958 51.205 ;
     RECT  27.936 51.197 32.958 51.233 ;
     RECT  34.02 51.161 39.186 51.233 ;
     RECT  41.22 51.205 42.642 51.233 ;
     RECT  27.936 51.233 29.934 51.269 ;
     RECT  34.02 51.233 39.042 51.269 ;
     RECT  41.22 51.233 41.238 51.293 ;
     RECT  7.668 50.971 24.606 51.307 ;
     RECT  47.736 51.241 47.754 51.307 ;
     RECT  47.736 51.307 48.474 51.341 ;
     RECT  7.488 51.307 24.606 51.359 ;
     RECT  30.78 51.233 32.958 51.359 ;
     RECT  34.2 51.269 39.006 51.359 ;
     RECT  40.104 51.161 40.497 51.359 ;
     RECT  27.972 51.269 29.862 51.389 ;
     RECT  49.608 51.161 52.398 51.389 ;
     RECT  12.528 51.359 19.17 51.395 ;
     RECT  20.196 51.359 22.05 51.395 ;
     RECT  22.86 51.359 24.606 51.395 ;
     RECT  30.78 51.359 32.778 51.395 ;
     RECT  34.2 51.359 37.206 51.395 ;
     RECT  37.98 51.359 38.79 51.395 ;
     RECT  42.156 51.233 42.642 51.395 ;
     RECT  48.456 51.341 48.474 51.395 ;
     RECT  49.608 51.389 52.218 51.395 ;
     RECT  12.528 51.395 17.406 51.431 ;
     RECT  32.544 51.395 32.598 51.431 ;
     RECT  34.2 51.395 37.17 51.431 ;
     RECT  43.452 51.197 46.782 51.431 ;
     RECT  49.608 51.395 51.534 51.437 ;
     RECT  7.488 51.359 11.682 51.467 ;
     RECT  22.86 51.395 22.878 51.467 ;
     RECT  38.016 51.395 38.034 51.467 ;
     RECT  43.452 51.431 44.19 51.467 ;
     RECT  44.964 51.431 46.782 51.467 ;
     RECT  10.728 51.467 11.682 51.485 ;
     RECT  7.488 51.467 9.126 51.503 ;
     RECT  10.728 51.485 10.746 51.503 ;
     RECT  11.556 51.485 11.682 51.503 ;
     RECT  12.528 51.431 17.262 51.503 ;
     RECT  20.34 51.395 22.05 51.503 ;
     RECT  28.08 51.389 29.862 51.503 ;
     RECT  30.78 51.395 31.338 51.503 ;
     RECT  34.236 51.431 36.09 51.503 ;
     RECT  37.152 51.431 37.17 51.503 ;
     RECT  43.632 51.467 44.19 51.503 ;
     RECT  49.608 51.437 50.13 51.503 ;
     RECT  23.868 51.395 24.606 51.511 ;
     RECT  25.884 50.855 26.766 51.511 ;
     RECT  55.044 51.089 62.097 51.511 ;
     RECT  7.815 51.503 9.126 51.539 ;
     RECT  15.768 51.503 17.262 51.539 ;
     RECT  18.615 51.395 19.17 51.539 ;
     RECT  20.34 51.503 20.358 51.539 ;
     RECT  25.812 51.511 26.766 51.539 ;
     RECT  29.415 51.503 29.862 51.539 ;
     RECT  32.58 51.431 32.598 51.539 ;
     RECT  34.776 51.503 35.946 51.539 ;
     RECT  46.764 51.467 46.782 51.539 ;
     RECT  51.015 51.437 51.534 51.539 ;
     RECT  2.415 36.545 2.697 51.587 ;
     RECT  7.815 51.539 8.097 51.587 ;
     RECT  29.415 51.539 29.697 51.587 ;
     RECT  40.215 51.359 40.497 51.587 ;
     RECT  44.964 51.467 45.897 51.587 ;
     RECT  51.015 51.539 51.297 51.587 ;
     RECT  54.72 51.511 62.097 51.587 ;
     RECT  12.528 51.503 14.922 51.629 ;
     RECT  18.615 51.539 19.134 51.629 ;
     RECT  22.032 51.503 22.05 51.629 ;
     RECT  23.868 51.511 25.038 51.629 ;
     RECT  28.08 51.503 28.602 51.629 ;
     RECT  34.815 51.539 35.946 51.629 ;
     RECT  38.772 51.395 38.79 51.629 ;
     RECT  42.624 51.395 42.642 51.629 ;
     RECT  44.964 51.587 45.705 51.629 ;
     RECT  11.664 51.503 11.682 51.665 ;
     RECT  18.615 51.629 19.026 51.665 ;
     RECT  43.632 51.503 43.866 51.665 ;
     RECT  12.528 51.629 13.662 51.677 ;
     RECT  14.544 51.629 14.598 51.701 ;
     RECT  21.132 51.503 21.15 51.701 ;
     RECT  25.02 51.629 25.038 51.701 ;
     RECT  28.188 51.629 28.602 51.701 ;
     RECT  14.544 51.701 14.562 51.737 ;
     RECT  15.768 51.539 16.542 51.737 ;
     RECT  25.812 51.539 25.83 51.737 ;
     RECT  34.815 51.629 35.406 51.737 ;
     RECT  54.72 51.587 61.905 51.737 ;
     RECT  13.176 51.677 13.662 51.773 ;
     RECT  15.768 51.737 15.786 51.773 ;
     RECT  18.615 51.665 18.954 51.773 ;
     RECT  26.784 51.601 26.874 51.773 ;
     RECT  30.78 51.503 30.798 51.773 ;
     RECT  9.108 51.539 9.126 51.809 ;
     RECT  13.176 51.773 13.59 51.809 ;
     RECT  16.524 51.737 16.542 51.809 ;
     RECT  26.784 51.773 26.802 51.809 ;
     RECT  28.404 51.701 28.602 51.809 ;
     RECT  43.632 51.665 43.65 51.809 ;
     RECT  60.804 51.737 61.905 51.821 ;
     RECT  2.415 51.587 2.505 51.857 ;
     RECT  7.815 51.587 7.905 51.857 ;
     RECT  13.215 51.809 13.305 51.857 ;
     RECT  18.615 51.773 18.705 51.857 ;
     RECT  24.015 51.629 24.105 51.857 ;
     RECT  29.415 51.587 29.505 51.857 ;
     RECT  34.815 51.737 34.905 51.857 ;
     RECT  40.215 51.587 40.305 51.857 ;
     RECT  45.615 51.629 45.705 51.857 ;
     RECT  51.015 51.587 51.105 51.857 ;
     RECT  55.044 51.737 60.03 51.857 ;
     RECT  61.632 51.821 61.905 51.857 ;
     RECT  60.804 51.821 60.894 51.869 ;
     RECT  57.204 51.857 60.03 51.917 ;
     RECT  57.204 51.917 59.958 52.157 ;
     RECT  57.564 52.157 59.958 52.253 ;
     RECT  57.564 52.253 57.582 52.589 ;
     RECT  58.32 52.253 59.958 52.589 ;
     RECT  55.044 51.857 55.854 52.733 ;
     RECT  58.716 52.589 59.958 53.021 ;
     RECT  55.728 52.733 55.854 53.069 ;
     RECT  55.728 53.069 55.746 53.117 ;
     RECT  58.716 53.021 59.706 53.165 ;
     RECT  59.256 53.165 59.706 53.885 ;
     RECT  60.804 51.869 60.822 53.885 ;
     RECT  61.632 51.857 61.65 53.885 ;
    LAYER M4 ;
     RECT  0.06 31.056 0.097 34.056 ;
     RECT  2.329 11.232 2.408 11.256 ;
     RECT  0.06 17.04 2.408 27.912 ;
     RECT  0.097 31.056 2.408 34.152 ;
     RECT  2.408 2.148 2.512 51.852 ;
     RECT  2.512 2.418 2.704 51.582 ;
     RECT  2.704 13.68 2.729 33.96 ;
     RECT  2.729 13.68 2.873 33.864 ;
     RECT  2.873 28.464 2.909 33.864 ;
     RECT  2.704 11.232 3.305 11.256 ;
     RECT  2.873 13.68 3.557 27.24 ;
     RECT  2.909 28.464 3.665 33.432 ;
     RECT  2.704 10.08 3.971 10.104 ;
     RECT  3.557 15.072 4.093 27.24 ;
     RECT  3.557 13.68 4.309 13.704 ;
     RECT  3.665 30 4.381 33.432 ;
     RECT  4.381 30 4.453 33.528 ;
     RECT  4.201 38.736 4.457 38.76 ;
     RECT  4.057 48.48 4.499 48.504 ;
     RECT  4.093 15.072 4.525 27.432 ;
     RECT  3.665 28.464 4.525 28.968 ;
     RECT  4.525 15.072 4.529 28.968 ;
     RECT  4.529 15.072 4.565 28.344 ;
     RECT  4.565 15.072 4.673 15.096 ;
     RECT  4.604 38.832 4.691 39.672 ;
     RECT  4.645 40.704 4.745 40.728 ;
     RECT  4.453 30 4.844 33.576 ;
     RECT  3.925 8.832 4.885 8.856 ;
     RECT  4.885 8.544 4.925 8.856 ;
     RECT  4.844 30 4.981 33.96 ;
     RECT  4.981 29.376 5.068 33.96 ;
     RECT  4.925 8.544 5.213 8.568 ;
     RECT  4.565 16.224 5.411 28.344 ;
     RECT  5.221 8.16 5.497 8.184 ;
     RECT  5.029 48.768 5.533 48.792 ;
     RECT  5.533 48.768 5.569 49.752 ;
     RECT  5.068 30 5.573 33.96 ;
     RECT  4.415 46.464 5.713 46.488 ;
     RECT  4.309 13.008 5.749 13.704 ;
     RECT  5.569 48.624 5.749 49.752 ;
     RECT  5.641 11.28 5.821 11.304 ;
     RECT  5.749 48.624 5.825 50.04 ;
     RECT  5.749 13.008 5.843 14.232 ;
     RECT  4.885 35.28 5.857 35.304 ;
     RECT  5.411 16.416 5.933 28.344 ;
     RECT  5.825 48.624 5.933 48.792 ;
     RECT  4.645 43.92 5.965 43.944 ;
     RECT  5.933 16.416 6.076 27.912 ;
     RECT  5.713 46.464 6.217 46.776 ;
     RECT  6.217 46.176 6.229 47.544 ;
     RECT  5.857 35.28 6.257 36.072 ;
     RECT  5.965 43.296 6.275 43.944 ;
     RECT  5.497 7.968 6.293 8.184 ;
     RECT  6.229 45.888 6.316 47.544 ;
     RECT  4.691 38.832 6.329 38.856 ;
     RECT  5.933 48.768 6.329 48.792 ;
     RECT  6.076 16.416 6.433 27.768 ;
     RECT  5.573 30.048 6.541 33.96 ;
     RECT  6.257 35.28 6.541 35.832 ;
     RECT  6.275 43.296 6.545 43.32 ;
     RECT  6.433 16.08 6.577 27.768 ;
     RECT  6.433 28.992 6.613 29.064 ;
     RECT  6.541 30.048 6.613 35.832 ;
     RECT  6.316 46.176 6.613 47.544 ;
     RECT  5.821 10.8 6.677 11.304 ;
     RECT  6.677 10.8 6.761 11.976 ;
     RECT  6.577 15.168 6.803 27.768 ;
     RECT  6.829 38.736 7.1 38.76 ;
     RECT  6.293 8.16 7.189 8.184 ;
     RECT  6.721 9.312 7.189 9.336 ;
     RECT  6.761 10.8 7.189 11.4 ;
     RECT  7.189 8.16 7.333 9.336 ;
     RECT  7.333 8.16 7.369 9.624 ;
     RECT  7.1 38.064 7.369 38.76 ;
     RECT  6.613 46.176 7.405 47.64 ;
     RECT  6.613 28.992 7.477 35.832 ;
     RECT  7.125 37.008 7.477 37.032 ;
     RECT  7.405 46.032 7.513 47.64 ;
     RECT  7.58 6.288 7.621 6.312 ;
     RECT  7.369 7.584 7.621 9.624 ;
     RECT  7.621 5.568 7.649 9.624 ;
     RECT  6.803 20.256 7.649 27.768 ;
     RECT  7.649 5.568 7.808 9.672 ;
     RECT  7.189 10.704 7.808 11.4 ;
     RECT  5.843 13.008 7.808 14.136 ;
     RECT  6.803 15.168 7.808 19.128 ;
     RECT  7.649 20.256 7.808 27.96 ;
     RECT  7.477 28.992 7.808 37.032 ;
     RECT  7.369 38.064 7.808 39.24 ;
     RECT  6.937 41.664 7.808 41.688 ;
     RECT  7.669 43.008 7.808 43.032 ;
     RECT  7.513 45.696 7.808 47.64 ;
     RECT  7.477 49.008 7.808 49.032 ;
     RECT  5.825 50.016 7.808 50.04 ;
     RECT  7.045 51.312 7.808 51.336 ;
     RECT  7.808 2.148 7.912 51.852 ;
     RECT  7.912 2.418 8.104 51.582 ;
     RECT  8.104 28.992 8.201 29.016 ;
     RECT  8.104 9.312 8.237 9.336 ;
     RECT  8.104 30.048 8.435 33.528 ;
     RECT  8.104 7.056 8.561 7.944 ;
     RECT  8.104 12.864 8.569 26.76 ;
     RECT  8.569 12.864 8.597 17.784 ;
     RECT  8.104 34.656 8.705 36.408 ;
     RECT  8.104 37.44 8.741 37.464 ;
     RECT  8.104 10.8 8.777 10.824 ;
     RECT  8.705 34.752 8.849 36.408 ;
     RECT  8.561 7.68 8.921 7.944 ;
     RECT  8.104 41.664 8.921 46.92 ;
     RECT  8.104 49.008 9.059 50.76 ;
     RECT  9.059 49.008 9.107 49.032 ;
     RECT  8.921 7.92 9.133 7.944 ;
     RECT  8.569 18.768 9.133 26.76 ;
     RECT  8.104 27.888 9.133 27.912 ;
     RECT  8.104 38.448 9.173 39.816 ;
     RECT  8.849 35.424 9.212 36.408 ;
     RECT  8.921 42.624 9.251 46.92 ;
     RECT  9.212 35.424 9.299 37.224 ;
     RECT  9.173 39.216 9.353 39.816 ;
     RECT  8.597 12.864 9.389 14.376 ;
     RECT  9.133 7.92 9.395 8.52 ;
     RECT  8.435 30.048 9.529 33.432 ;
     RECT  9.353 39.312 9.533 39.816 ;
     RECT  8.104 5.568 9.677 5.592 ;
     RECT  8.597 15.984 9.685 17.784 ;
     RECT  9.133 18.768 9.685 27.912 ;
     RECT  9.251 44.352 9.709 46.92 ;
     RECT  9.685 15.984 9.713 27.912 ;
     RECT  9.529 29.088 9.785 33.432 ;
     RECT  9.389 13.008 9.817 14.376 ;
     RECT  9.713 15.984 9.836 21.768 ;
     RECT  9.713 22.752 9.857 27.336 ;
     RECT  9.857 22.752 9.893 26.232 ;
     RECT  9.059 50.112 9.997 50.76 ;
     RECT  9.817 11.376 10.033 11.4 ;
     RECT  9.533 39.792 10.109 39.816 ;
     RECT  9.709 44.352 10.109 47.688 ;
     RECT  9.785 31.344 10.141 33.432 ;
     RECT  10.033 11.184 10.181 11.4 ;
     RECT  9.251 42.624 10.209 43.032 ;
     RECT  9.817 13.008 10.213 14.52 ;
     RECT  9.836 15.84 10.213 21.768 ;
     RECT  9.299 35.424 10.213 36.408 ;
     RECT  10.213 35.376 10.249 36.408 ;
     RECT  10.249 34.704 10.259 36.408 ;
     RECT  9.395 7.92 10.285 8.28 ;
     RECT  10.109 44.352 10.289 46.584 ;
     RECT  10.289 46.128 10.325 46.584 ;
     RECT  10.316 6.288 10.403 6.312 ;
     RECT  10.181 11.28 10.429 11.4 ;
     RECT  10.213 13.008 10.429 21.768 ;
     RECT  9.785 29.088 10.429 30.072 ;
     RECT  10.141 31.344 10.465 33.624 ;
     RECT  10.259 34.704 10.465 35.736 ;
     RECT  10.429 11.28 10.505 21.768 ;
     RECT  10.285 7.68 10.573 8.28 ;
     RECT  10.573 7.632 10.645 8.28 ;
     RECT  10.109 47.664 10.649 47.688 ;
     RECT  10.209 42.624 10.717 42.744 ;
     RECT  9.997 50.112 10.717 51.144 ;
     RECT  10.465 31.344 10.721 35.736 ;
     RECT  10.645 6.912 10.753 8.28 ;
     RECT  10.177 49.008 10.753 49.032 ;
     RECT  10.721 31.344 10.757 31.56 ;
     RECT  10.429 28.416 10.789 30.072 ;
     RECT  10.753 6.912 10.865 9.144 ;
     RECT  10.753 48.096 10.901 49.032 ;
     RECT  10.789 28.416 10.937 30.792 ;
     RECT  10.721 32.784 10.937 35.736 ;
     RECT  10.505 11.28 10.973 21.72 ;
     RECT  9.893 22.8 10.973 26.232 ;
     RECT  10.973 11.28 11.009 13.656 ;
     RECT  10.289 44.352 11.041 44.904 ;
     RECT  9.253 38.208 11.045 38.232 ;
     RECT  11.041 44.256 11.077 44.904 ;
     RECT  10.717 50.112 11.081 51.48 ;
     RECT  10.973 22.8 11.365 25.608 ;
     RECT  9.857 27.312 11.365 27.336 ;
     RECT  10.937 28.416 11.365 30.12 ;
     RECT  10.901 48.384 11.477 49.032 ;
     RECT  10.973 14.832 11.545 21.72 ;
     RECT  11.365 22.752 11.545 25.608 ;
     RECT  11.077 43.92 11.545 44.904 ;
     RECT  11.545 14.832 11.549 25.608 ;
     RECT  11.365 27.312 11.657 30.12 ;
     RECT  10.937 34.8 11.657 35.736 ;
     RECT  10.325 46.56 11.689 46.584 ;
     RECT  11.081 50.112 11.689 51.336 ;
     RECT  11.549 24.336 11.693 25.608 ;
     RECT  11.657 34.8 11.765 35.16 ;
     RECT  11.689 49.584 11.773 51.336 ;
     RECT  10.865 6.912 11.869 9.048 ;
     RECT  11.477 48.384 11.869 48.456 ;
     RECT  11.545 43.92 11.905 45.48 ;
     RECT  11.693 24.336 11.909 25.272 ;
     RECT  11.765 35.136 11.909 35.16 ;
     RECT  10.937 32.784 11.977 33.816 ;
     RECT  11.009 12.48 11.98 13.656 ;
     RECT  11.689 46.56 11.987 46.824 ;
     RECT  11.869 6.912 11.989 10.008 ;
     RECT  11.009 11.28 11.989 11.4 ;
     RECT  10.717 42.192 12.017 42.744 ;
     RECT  11.989 6.912 12.035 11.4 ;
     RECT  11.869 48.336 12.085 48.456 ;
     RECT  12.035 10.224 12.097 11.4 ;
     RECT  11.909 24.672 12.125 25.272 ;
     RECT  11.657 27.312 12.125 27.912 ;
     RECT  12.097 10.56 12.161 11.4 ;
     RECT  11.98 12.72 12.193 13.656 ;
     RECT  11.549 14.832 12.193 23.352 ;
     RECT  11.905 43.776 12.38 45.48 ;
     RECT  11.833 36.192 12.409 36.216 ;
     RECT  11.657 29.04 12.445 30.12 ;
     RECT  12.445 29.04 12.481 30.6 ;
     RECT  11.977 31.92 12.481 33.816 ;
     RECT  11.773 49.872 12.517 51.336 ;
     RECT  12.035 6.912 12.733 9.048 ;
     RECT  11.987 46.752 12.805 46.824 ;
     RECT  12.085 48.24 12.805 48.456 ;
     RECT  12.517 49.872 12.805 51.672 ;
     RECT  12.157 38.256 13.021 38.28 ;
     RECT  12.481 29.04 13.057 33.816 ;
     RECT  13.021 38.256 13.057 38.424 ;
     RECT  13.052 39.6 13.057 39.624 ;
     RECT  12.125 24.72 13.093 25.272 ;
     RECT  12.085 26.256 13.093 26.28 ;
     RECT  12.125 27.312 13.093 27.864 ;
     RECT  13.057 28.992 13.093 33.816 ;
     RECT  12.409 36.192 13.093 37.176 ;
     RECT  13.057 38.256 13.093 39.624 ;
     RECT  12.805 49.776 13.165 51.672 ;
     RECT  9.961 4.656 13.208 4.68 ;
     RECT  12.733 6.864 13.208 9.048 ;
     RECT  12.161 10.56 13.208 10.584 ;
     RECT  12.193 12.72 13.208 23.352 ;
     RECT  13.093 24.72 13.208 26.28 ;
     RECT  13.093 27.312 13.208 33.816 ;
     RECT  13.093 35.184 13.208 35.208 ;
     RECT  13.093 36.192 13.208 39.624 ;
     RECT  12.017 42.192 13.208 42.216 ;
     RECT  12.38 43.776 13.208 45.576 ;
     RECT  12.805 46.752 13.208 48.456 ;
     RECT  13.165 49.776 13.208 51.768 ;
     RECT  13.208 2.148 13.312 51.852 ;
     RECT  13.312 2.418 13.504 51.768 ;
     RECT  13.504 34.656 13.565 37.032 ;
     RECT  13.504 41.568 13.601 45.144 ;
     RECT  13.504 51.648 13.601 51.768 ;
     RECT  13.565 34.8 13.637 37.032 ;
     RECT  13.504 40.56 13.637 40.584 ;
     RECT  13.601 51.648 13.673 51.672 ;
     RECT  13.504 39.216 13.709 39.24 ;
     RECT  13.504 7.536 13.889 8.568 ;
     RECT  13.504 14.736 13.889 19.8 ;
     RECT  13.637 34.8 13.889 35.208 ;
     RECT  13.637 36.24 13.925 37.032 ;
     RECT  13.601 42.864 14.069 45.144 ;
     RECT  13.504 4.656 14.099 6.264 ;
     RECT  13.504 26.448 14.339 31.224 ;
     RECT  14.339 30.384 14.357 31.224 ;
     RECT  13.504 32.304 14.365 33.672 ;
     RECT  13.504 12.864 14.483 13.656 ;
     RECT  14.483 12.864 14.524 13.08 ;
     RECT  13.889 14.928 14.537 19.8 ;
     RECT  14.357 30.576 14.569 31.224 ;
     RECT  14.365 32.304 14.569 33.096 ;
     RECT  14.069 43.296 14.569 45.144 ;
     RECT  13.504 46.512 14.569 46.536 ;
     RECT  13.601 41.568 14.605 41.592 ;
     RECT  13.504 47.616 14.629 49.944 ;
     RECT  14.629 47.616 14.641 50.76 ;
     RECT  14.099 5.472 14.645 6.264 ;
     RECT  13.889 34.8 14.645 34.824 ;
     RECT  13.925 36.96 14.645 37.032 ;
     RECT  14.641 47.616 14.723 51.24 ;
     RECT  13.504 20.976 14.749 23.4 ;
     RECT  13.504 24.72 14.749 25.464 ;
     RECT  14.339 26.448 14.749 29.112 ;
     RECT  14.645 36.96 14.825 36.984 ;
     RECT  13.889 7.536 14.857 8.472 ;
     RECT  14.537 19.248 14.857 19.8 ;
     RECT  14.749 20.976 14.857 29.112 ;
     RECT  14.605 41.568 14.897 42.264 ;
     RECT  14.723 47.616 14.969 48.456 ;
     RECT  14.569 43.296 15.005 46.536 ;
     RECT  14.645 6 15.077 6.264 ;
     RECT  14.537 14.928 15.145 17.688 ;
     RECT  14.723 49.872 15.185 51.24 ;
     RECT  14.897 42.192 15.212 42.264 ;
     RECT  15.005 43.296 15.212 45.048 ;
     RECT  14.524 12.864 15.289 13.032 ;
     RECT  15.212 42.192 15.299 45.048 ;
     RECT  14.857 19.248 15.365 29.112 ;
     RECT  15.145 14.784 15.395 17.688 ;
     RECT  15.365 22.464 15.397 29.112 ;
     RECT  15.289 12.288 15.5 13.032 ;
     RECT  15.299 44.88 15.509 45.048 ;
     RECT  14.857 7.536 15.541 9.432 ;
     RECT  15.5 11.616 15.541 13.032 ;
     RECT  15.541 7.536 15.587 13.032 ;
     RECT  15.397 22.464 15.613 29.544 ;
     RECT  14.569 30.576 15.613 33.096 ;
     RECT  15.613 22.464 15.617 33.096 ;
     RECT  14.749 34.368 15.644 34.392 ;
     RECT  15.395 14.928 15.685 17.688 ;
     RECT  14.965 36.48 15.793 36.504 ;
     RECT  15.587 7.536 15.833 10.92 ;
     RECT  15.617 22.464 15.833 32.52 ;
     RECT  15.833 22.464 15.869 31.128 ;
     RECT  15.644 34.368 15.901 35.112 ;
     RECT  15.793 36.288 15.901 36.504 ;
     RECT  14.605 39.072 15.901 39.096 ;
     RECT  15.077 6.192 15.937 6.264 ;
     RECT  15.833 7.536 15.937 9.192 ;
     RECT  15.901 39.072 15.937 39.624 ;
     RECT  15.833 10.224 15.941 10.92 ;
     RECT  14.969 47.952 15.941 48.456 ;
     RECT  15.901 34.368 16.009 36.504 ;
     RECT  16.009 34.176 16.069 36.504 ;
     RECT  15.937 39.072 16.069 39.768 ;
     RECT  15.365 19.248 16.085 21.48 ;
     RECT  15.869 25.152 16.121 31.128 ;
     RECT  16.069 34.176 16.156 37.512 ;
     RECT  15.833 32.496 16.157 32.52 ;
     RECT  15.941 10.896 16.265 10.92 ;
     RECT  15.937 6.192 16.373 9.192 ;
     RECT  16.333 2.784 16.451 2.808 ;
     RECT  15.685 14.928 16.453 18.024 ;
     RECT  15.869 22.464 16.481 24.072 ;
     RECT  16.121 25.392 16.625 31.128 ;
     RECT  16.069 38.784 16.769 39.768 ;
     RECT  16.769 38.784 16.805 38.808 ;
     RECT  16.625 28.8 16.837 31.128 ;
     RECT  16.405 4.896 16.841 4.92 ;
     RECT  15.941 47.952 16.873 47.976 ;
     RECT  15.185 49.872 16.877 49.896 ;
     RECT  16.625 25.392 16.913 27.672 ;
     RECT  16.913 25.392 16.949 25.752 ;
     RECT  16.453 14.832 16.981 18.024 ;
     RECT  16.085 19.248 16.981 19.944 ;
     RECT  15.299 42.192 16.981 42.216 ;
     RECT  16.873 47.904 16.981 47.976 ;
     RECT  16.945 49.056 16.981 49.56 ;
     RECT  16.621 32.88 16.985 32.904 ;
     RECT  16.981 47.904 17.017 49.56 ;
     RECT  16.981 41.952 17.021 42.216 ;
     RECT  16.156 34.176 17.057 37.032 ;
     RECT  15.587 11.952 17.077 13.032 ;
     RECT  16.981 14.832 17.089 19.944 ;
     RECT  16.085 21.12 17.089 21.48 ;
     RECT  17.021 41.952 17.093 41.976 ;
     RECT  17.077 11.952 17.123 13.32 ;
     RECT  17.057 36.048 17.125 37.032 ;
     RECT  17.089 14.832 17.129 21.48 ;
     RECT  17.123 13.008 17.164 13.32 ;
     RECT  16.373 6.192 17.197 8.568 ;
     RECT  16.837 28.8 17.269 31.416 ;
     RECT  17.125 36.048 17.309 38.52 ;
     RECT  17.228 24.816 17.315 24.84 ;
     RECT  17.309 37.008 17.381 38.52 ;
     RECT  17.269 28.8 17.561 31.464 ;
     RECT  17.057 34.176 17.561 34.92 ;
     RECT  17.017 47.712 17.629 49.56 ;
     RECT  17.197 4.944 17.633 8.568 ;
     RECT  17.561 29.088 17.665 31.464 ;
     RECT  17.633 8.544 18.025 8.568 ;
     RECT  17.593 41.328 18.061 41.352 ;
     RECT  18.025 8.544 18.097 9.048 ;
     RECT  16.913 27.12 18.133 27.672 ;
     RECT  17.129 14.832 18.169 19.272 ;
     RECT  17.629 47.616 18.169 49.56 ;
     RECT  17.129 20.88 18.205 21.48 ;
     RECT  16.481 22.464 18.205 23.736 ;
     RECT  18.133 26.88 18.205 27.672 ;
     RECT  17.413 39.792 18.229 39.816 ;
     RECT  18.061 41.328 18.229 41.928 ;
     RECT  17.381 38.496 18.277 38.52 ;
     RECT  18.229 39.792 18.277 41.928 ;
     RECT  17.633 4.944 18.313 7.56 ;
     RECT  18.169 47.616 18.457 49.848 ;
     RECT  18.277 38.496 18.469 41.928 ;
     RECT  18.097 8.544 18.493 9.432 ;
     RECT  18.205 26.832 18.493 27.672 ;
     RECT  18.421 25.728 18.529 25.752 ;
     RECT  18.493 26.832 18.529 27.912 ;
     RECT  18.529 25.728 18.565 27.912 ;
     RECT  18.169 14.784 18.601 19.272 ;
     RECT  17.809 2.496 18.608 2.52 ;
     RECT  18.313 4.464 18.608 7.56 ;
     RECT  18.493 8.544 18.608 9.816 ;
     RECT  17.123 11.952 18.608 11.976 ;
     RECT  17.164 13.008 18.608 13.032 ;
     RECT  18.601 14.784 18.608 19.56 ;
     RECT  18.205 20.88 18.608 23.736 ;
     RECT  18.565 24.96 18.608 27.912 ;
     RECT  17.665 29.088 18.608 32.52 ;
     RECT  17.561 34.368 18.608 34.92 ;
     RECT  17.381 37.008 18.608 37.032 ;
     RECT  18.469 38.496 18.608 43.368 ;
     RECT  15.509 44.88 18.608 44.904 ;
     RECT  18.457 47.136 18.608 49.848 ;
     RECT  15.185 50.928 18.608 51.24 ;
     RECT  18.608 2.148 18.712 51.852 ;
     RECT  18.712 2.418 18.904 51.582 ;
     RECT  18.904 9.024 18.929 10.248 ;
     RECT  18.929 9.024 19.001 9.048 ;
     RECT  18.904 31.824 19.101 34.92 ;
     RECT  18.904 39.024 19.109 39.816 ;
     RECT  19.101 31.824 19.181 34.872 ;
     RECT  18.904 47.136 19.181 51.432 ;
     RECT  18.904 11.424 19.217 11.976 ;
     RECT  19.217 11.664 19.235 11.976 ;
     RECT  19.181 31.824 19.235 34.392 ;
     RECT  18.904 15.312 19.433 30.6 ;
     RECT  19.433 20.016 19.505 30.6 ;
     RECT  18.904 41.376 19.541 41.4 ;
     RECT  18.904 2.496 19.613 8.04 ;
     RECT  18.929 10.128 19.613 10.248 ;
     RECT  19.433 15.312 19.613 18.84 ;
     RECT  19.613 15.456 19.667 18.84 ;
     RECT  19.235 32.448 19.667 34.392 ;
     RECT  19.667 15.456 19.685 17.928 ;
     RECT  19.505 20.016 19.685 24.744 ;
     RECT  19.667 32.448 19.721 34.248 ;
     RECT  19.181 47.136 19.721 50.712 ;
     RECT  18.904 42.72 19.865 43.368 ;
     RECT  15.937 0.048 19.897 0.072 ;
     RECT  19.235 11.664 19.901 11.688 ;
     RECT  18.904 44.88 20.113 44.904 ;
     RECT  19.109 39.504 20.117 39.816 ;
     RECT  19.685 24.144 20.153 24.744 ;
     RECT  20.117 39.792 20.189 39.816 ;
     RECT  20.149 1.728 20.243 1.752 ;
     RECT  19.721 32.496 20.333 34.248 ;
     RECT  18.904 13.008 20.365 13.032 ;
     RECT  19.897 0.048 20.389 0.12 ;
     RECT  19.685 15.504 20.405 17.928 ;
     RECT  20.405 15.504 20.441 17.832 ;
     RECT  19.685 20.016 20.441 22.776 ;
     RECT  20.441 15.504 20.477 17.496 ;
     RECT  20.333 32.976 20.483 34.248 ;
     RECT  20.365 41.616 20.509 41.64 ;
     RECT  20.365 13.008 20.513 13.368 ;
     RECT  20.389 0.048 20.531 0.168 ;
     RECT  19.505 26.496 20.531 30.6 ;
     RECT  19.613 2.832 20.581 8.04 ;
     RECT  19.865 43.248 20.653 43.368 ;
     RECT  20.113 44.4 20.653 45.528 ;
     RECT  20.531 28.416 20.657 30.6 ;
     RECT  20.581 2.784 20.693 8.04 ;
     RECT  20.441 20.88 20.693 22.776 ;
     RECT  20.531 26.496 20.693 27.336 ;
     RECT  19.721 47.136 20.725 50.136 ;
     RECT  20.657 28.416 20.729 28.872 ;
     RECT  20.653 43.248 20.729 45.528 ;
     RECT  20.693 3.792 20.761 8.04 ;
     RECT  19.613 10.224 20.833 10.248 ;
     RECT  20.729 43.248 20.869 43.896 ;
     RECT  20.761 3.792 20.905 8.136 ;
     RECT  20.657 29.952 20.981 30.6 ;
     RECT  20.729 44.88 20.981 45.528 ;
     RECT  20.729 28.416 21.053 28.632 ;
     RECT  20.761 25.584 21.089 25.608 ;
     RECT  20.693 21.264 21.149 22.776 ;
     RECT  20.153 24.144 21.149 24.216 ;
     RECT  20.981 29.952 21.225 29.976 ;
     RECT  20.869 36.768 21.265 36.792 ;
     RECT  21.157 38.208 21.265 38.232 ;
     RECT  20.509 41.616 21.301 41.688 ;
     RECT  20.869 42.72 21.301 43.896 ;
     RECT  20.725 46.8 21.301 50.136 ;
     RECT  21.053 28.416 21.305 28.44 ;
     RECT  20.483 33.504 21.445 34.248 ;
     RECT  21.157 30.96 21.553 30.984 ;
     RECT  20.693 2.784 21.589 2.808 ;
     RECT  21.548 35.28 21.589 35.304 ;
     RECT  21.445 33.072 21.593 34.248 ;
     RECT  21.301 46.8 21.593 50.904 ;
     RECT  21.553 30.96 21.625 31.464 ;
     RECT  20.833 10.224 21.661 10.776 ;
     RECT  21.149 21.264 21.661 24.216 ;
     RECT  21.589 35.28 21.673 35.4 ;
     RECT  21.661 10.224 21.697 11.4 ;
     RECT  20.513 13.008 21.697 13.032 ;
     RECT  20.693 26.88 21.697 27.336 ;
     RECT  21.625 30.96 21.737 32.232 ;
     RECT  21.301 41.616 21.737 43.896 ;
     RECT  21.589 2.736 21.769 2.808 ;
     RECT  20.905 3.792 21.769 8.184 ;
     RECT  21.593 33.552 21.773 34.248 ;
     RECT  21.697 26.784 21.809 27.336 ;
     RECT  21.737 41.76 21.836 43.896 ;
     RECT  20.981 44.88 21.836 45.192 ;
     RECT  21.769 2.736 21.842 8.184 ;
     RECT  20.531 0.096 21.845 0.12 ;
     RECT  21.842 2.784 21.877 8.184 ;
     RECT  21.836 41.76 21.923 45.192 ;
     RECT  21.661 21.216 21.949 24.216 ;
     RECT  21.737 30.96 21.953 31.464 ;
     RECT  21.265 36.768 21.985 38.232 ;
     RECT  21.593 46.8 21.985 50.136 ;
     RECT  21.985 36.768 22.025 38.808 ;
     RECT  21.949 21.072 22.129 24.216 ;
     RECT  20.477 15.792 22.165 17.496 ;
     RECT  22.025 38.784 22.165 38.808 ;
     RECT  21.985 46.368 22.165 50.136 ;
     RECT  22.025 36.768 22.277 37.608 ;
     RECT  22.165 15.792 22.309 17.976 ;
     RECT  22.277 37.392 22.313 37.416 ;
     RECT  21.773 33.888 22.345 34.248 ;
     RECT  22.309 15.792 22.417 18.312 ;
     RECT  21.157 19.68 22.417 19.704 ;
     RECT  22.129 21.072 22.417 24.744 ;
     RECT  21.809 26.88 22.421 27.336 ;
     RECT  21.697 10.224 22.501 13.032 ;
     RECT  22.417 15.744 22.501 18.312 ;
     RECT  22.501 10.224 22.529 13.608 ;
     RECT  22.165 38.784 22.601 39.288 ;
     RECT  22.417 19.68 22.637 24.744 ;
     RECT  22.529 10.752 22.669 13.608 ;
     RECT  22.201 14.688 22.669 14.712 ;
     RECT  22.453 40.56 22.673 40.584 ;
     RECT  22.165 46.272 22.673 50.136 ;
     RECT  21.877 2.784 22.741 9.048 ;
     RECT  22.669 10.752 22.781 14.712 ;
     RECT  22.501 15.744 22.853 18.696 ;
     RECT  22.673 46.368 22.853 50.136 ;
     RECT  22.741 2.784 22.889 9.672 ;
     RECT  22.781 10.752 22.889 14.232 ;
     RECT  22.637 20.4 22.889 24.744 ;
     RECT  21.923 41.76 22.957 43.896 ;
     RECT  22.345 33.888 22.961 34.488 ;
     RECT  22.421 27.12 23.029 27.336 ;
     RECT  23.137 32.208 23.173 32.232 ;
     RECT  22.601 38.784 23.245 38.808 ;
     RECT  23.245 38.736 23.317 38.808 ;
     RECT  22.957 41.136 23.365 43.896 ;
     RECT  21.923 45.168 23.533 45.192 ;
     RECT  23.533 45.168 23.605 45.24 ;
     RECT  23.605 45.168 23.641 45.288 ;
     RECT  23.365 41.136 23.677 43.944 ;
     RECT  23.641 45.168 23.677 45.48 ;
     RECT  21.953 30.96 23.821 30.984 ;
     RECT  23.173 32.208 23.821 32.472 ;
     RECT  23.677 41.136 23.821 45.48 ;
     RECT  22.853 16.08 23.893 18.696 ;
     RECT  22.889 4.128 23.929 9.672 ;
     RECT  22.889 10.752 23.929 10.776 ;
     RECT  23.893 16.08 23.929 18.792 ;
     RECT  23.029 27.12 23.929 27.96 ;
     RECT  23.533 36.48 24.001 36.504 ;
     RECT  22.889 2.784 24.008 3.144 ;
     RECT  23.929 4.128 24.008 10.776 ;
     RECT  22.889 12.288 24.008 14.232 ;
     RECT  23.929 16.032 24.008 18.792 ;
     RECT  22.889 20.928 24.008 24.744 ;
     RECT  23.929 26.64 24.008 27.96 ;
     RECT  23.821 30.96 24.008 32.472 ;
     RECT  22.961 34.224 24.008 34.488 ;
     RECT  24.001 36.336 24.008 36.504 ;
     RECT  23.317 38.16 24.008 38.808 ;
     RECT  23.821 40.944 24.008 45.48 ;
     RECT  22.853 46.8 24.008 50.04 ;
     RECT  23.785 51.216 24.008 51.24 ;
     RECT  24.008 2.148 24.112 51.852 ;
     RECT  24.112 2.418 24.304 51.582 ;
     RECT  24.304 30.672 24.329 32.232 ;
     RECT  24.304 2.736 24.419 7.944 ;
     RECT  24.304 40.944 24.419 45.576 ;
     RECT  24.419 41.376 24.515 45.576 ;
     RECT  24.304 26.64 24.581 28.392 ;
     RECT  24.515 43.92 24.617 45.576 ;
     RECT  24.304 46.8 24.617 51.24 ;
     RECT  24.329 30.672 24.689 32.04 ;
     RECT  24.304 34.08 24.689 34.488 ;
     RECT  24.304 36.336 24.689 36.36 ;
     RECT  24.304 20.832 24.803 20.856 ;
     RECT  24.304 8.976 24.977 10.152 ;
     RECT  24.689 32.016 25.193 32.04 ;
     RECT  24.304 23.616 25.445 25.224 ;
     RECT  24.304 11.424 25.481 13.656 ;
     RECT  24.304 21.984 25.513 22.536 ;
     RECT  25.445 23.616 25.513 24.792 ;
     RECT  24.617 44.112 25.549 45.576 ;
     RECT  24.617 46.8 25.549 50.376 ;
     RECT  24.977 8.976 25.589 9.672 ;
     RECT  25.549 44.112 25.589 50.376 ;
     RECT  24.689 30.672 25.625 30.696 ;
     RECT  24.419 4.128 25.657 7.944 ;
     RECT  25.589 8.976 25.657 9.336 ;
     RECT  24.515 41.376 25.657 42.6 ;
     RECT  24.304 37.824 25.661 39.864 ;
     RECT  25.657 4.128 25.697 9.336 ;
     RECT  24.304 16.032 25.697 18.792 ;
     RECT  25.657 40.944 25.717 42.6 ;
     RECT  25.513 21.648 25.733 24.792 ;
     RECT  25.481 12 25.769 13.656 ;
     RECT  24.581 26.88 25.772 28.392 ;
     RECT  25.772 26.88 25.859 28.632 ;
     RECT  25.717 40.944 25.873 42.84 ;
     RECT  25.697 4.128 25.877 9.096 ;
     RECT  25.661 38.4 26.129 39.864 ;
     RECT  25.585 20.16 26.161 20.184 ;
     RECT  25.697 17.184 26.165 18.792 ;
     RECT  26.165 17.184 26.173 18.216 ;
     RECT  25.589 44.4 26.309 50.376 ;
     RECT  24.419 2.736 26.341 3.144 ;
     RECT  25.769 12.288 26.348 13.656 ;
     RECT  24.304 14.976 26.348 15 ;
     RECT  26.348 12.288 26.435 15 ;
     RECT  26.341 2.352 26.449 3.144 ;
     RECT  25.877 4.128 26.449 6.552 ;
     RECT  26.309 44.4 26.453 50.136 ;
     RECT  25.877 7.536 26.489 9.096 ;
     RECT  26.435 14.976 26.489 15 ;
     RECT  26.161 20.16 26.593 20.328 ;
     RECT  26.449 2.352 26.669 6.552 ;
     RECT  26.489 8.784 26.741 9.096 ;
     RECT  26.435 12.288 26.771 13.656 ;
     RECT  26.741 9.024 26.777 9.096 ;
     RECT  26.377 51.216 26.777 51.24 ;
     RECT  26.737 31.776 26.885 31.8 ;
     RECT  26.017 10.704 26.921 10.728 ;
     RECT  25.859 26.88 26.957 28.584 ;
     RECT  25.697 16.032 26.989 16.2 ;
     RECT  26.173 17.184 26.989 17.496 ;
     RECT  26.489 7.536 26.993 7.8 ;
     RECT  25.733 21.648 27.013 22.632 ;
     RECT  25.733 23.664 27.013 24.792 ;
     RECT  27.013 21.648 27.029 24.792 ;
     RECT  26.453 44.4 27.029 45.192 ;
     RECT  26.777 9.072 27.253 9.096 ;
     RECT  27.253 9.072 27.34 9.768 ;
     RECT  26.989 15.024 27.349 15.048 ;
     RECT  26.989 16.032 27.349 17.496 ;
     RECT  26.993 7.68 27.389 7.8 ;
     RECT  27.029 21.648 27.389 24.648 ;
     RECT  27.389 7.776 27.425 7.8 ;
     RECT  25.873 40.896 27.425 42.84 ;
     RECT  27.029 44.592 27.452 45.192 ;
     RECT  26.453 46.176 27.452 50.136 ;
     RECT  26.669 2.352 27.493 3.144 ;
     RECT  26.771 12.288 27.497 13.56 ;
     RECT  27.349 15.024 27.497 17.496 ;
     RECT  26.593 20.016 27.529 20.328 ;
     RECT  27.389 23.664 27.569 24.648 ;
     RECT  27.34 9.072 27.605 9.528 ;
     RECT  26.129 38.4 27.733 38.424 ;
     RECT  27.425 40.896 27.749 42.792 ;
     RECT  27.733 37.584 27.779 38.424 ;
     RECT  27.779 37.584 27.82 37.992 ;
     RECT  27.497 15.264 27.853 17.496 ;
     RECT  27.853 15.264 27.893 18.168 ;
     RECT  27.529 19.344 27.929 20.328 ;
     RECT  27.925 51.216 27.961 51.24 ;
     RECT  27.929 20.16 27.997 20.328 ;
     RECT  27.893 16.032 28.001 18.168 ;
     RECT  28.001 16.128 28.037 18.168 ;
     RECT  27.389 21.648 28.037 22.632 ;
     RECT  27.997 20.16 28.145 20.616 ;
     RECT  28.037 21.984 28.145 22.632 ;
     RECT  26.669 4.128 28.259 6.552 ;
     RECT  28.259 4.176 28.289 6.552 ;
     RECT  28.213 11.424 28.297 11.448 ;
     RECT  28.289 4.272 28.325 6.552 ;
     RECT  27.497 13.008 28.357 13.56 ;
     RECT  27.452 44.592 28.393 50.136 ;
     RECT  27.961 51.216 28.393 51.384 ;
     RECT  28.037 16.272 28.508 18.168 ;
     RECT  27.569 23.808 28.645 24.648 ;
     RECT  28.249 9.024 28.681 9.048 ;
     RECT  28.573 7.584 28.717 7.608 ;
     RECT  28.681 8.688 28.717 9.048 ;
     RECT  27.749 40.896 28.741 42.6 ;
     RECT  28.393 35.568 28.753 35.592 ;
     RECT  28.325 4.56 28.969 6.552 ;
     RECT  28.717 7.584 28.969 9.048 ;
     RECT  28.741 40.608 29.029 42.6 ;
     RECT  27.82 37.968 29.041 37.992 ;
     RECT  28.357 13.008 29.077 13.656 ;
     RECT  29.029 40.128 29.269 42.6 ;
     RECT  28.508 16.272 29.365 18.408 ;
     RECT  27.493 2.304 29.401 3.144 ;
     RECT  29.401 2.304 29.408 3.384 ;
     RECT  28.969 4.56 29.408 9.048 ;
     RECT  29.077 11.76 29.408 13.656 ;
     RECT  29.365 16.032 29.408 18.408 ;
     RECT  28.145 20.592 29.408 20.616 ;
     RECT  28.145 21.984 29.408 22.2 ;
     RECT  28.645 23.376 29.408 24.648 ;
     RECT  27.349 25.728 29.408 25.752 ;
     RECT  26.957 26.88 29.408 27.912 ;
     RECT  28.141 31.2 29.408 31.224 ;
     RECT  24.689 34.08 29.408 34.104 ;
     RECT  28.753 35.28 29.408 35.592 ;
     RECT  29.149 36.576 29.408 36.6 ;
     RECT  29.041 37.968 29.408 38.712 ;
     RECT  29.269 40.128 29.408 43.32 ;
     RECT  28.393 44.592 29.408 51.384 ;
     RECT  29.408 2.148 29.512 51.852 ;
     RECT  29.512 2.304 29.704 51.582 ;
     RECT  29.704 25.728 29.765 25.752 ;
     RECT  29.704 36.576 29.837 42.6 ;
     RECT  29.704 34.512 29.843 35.352 ;
     RECT  29.704 31.2 29.981 31.224 ;
     RECT  29.837 36.576 30.017 42.216 ;
     RECT  30.017 36.576 30.089 42.12 ;
     RECT  29.704 2.304 30.197 10.44 ;
     RECT  29.704 11.76 30.197 14.568 ;
     RECT  30.197 2.304 30.269 10.2 ;
     RECT  30.089 36.576 30.275 41.928 ;
     RECT  30.269 2.304 30.341 9.72 ;
     RECT  30.275 37.584 30.593 41.928 ;
     RECT  29.704 21.984 30.733 22.008 ;
     RECT  29.704 23.376 30.733 24.648 ;
     RECT  29.704 27.12 30.733 27.912 ;
     RECT  30.733 23.376 30.773 24.936 ;
     RECT  30.689 30.672 30.773 30.792 ;
     RECT  30.773 23.376 30.809 23.688 ;
     RECT  29.704 20.16 30.841 20.616 ;
     RECT  30.197 12.048 30.845 14.568 ;
     RECT  30.773 30.768 30.845 30.792 ;
     RECT  30.593 37.872 30.853 41.928 ;
     RECT  30.733 27.12 30.881 27.96 ;
     RECT  29.843 35.04 30.881 35.352 ;
     RECT  30.853 41.616 30.881 41.928 ;
     RECT  29.704 44.688 30.881 51.384 ;
     RECT  30.341 2.304 30.917 9.384 ;
     RECT  29.704 16.032 30.917 18.216 ;
     RECT  30.881 27.12 30.953 27.912 ;
     RECT  30.917 16.56 30.985 18.216 ;
     RECT  30.841 19.344 30.985 20.616 ;
     RECT  29.704 32.736 31.025 33.48 ;
     RECT  30.985 16.56 31.061 20.616 ;
     RECT  30.917 2.304 31.093 3.144 ;
     RECT  31.061 16.56 31.097 20.184 ;
     RECT  31.097 19.344 31.169 20.184 ;
     RECT  30.275 36.576 31.237 36.6 ;
     RECT  30.733 21.984 31.273 22.056 ;
     RECT  30.881 44.688 31.309 50.136 ;
     RECT  31.273 21.744 31.381 22.056 ;
     RECT  31.025 32.736 31.421 33.24 ;
     RECT  30.881 41.904 31.561 41.928 ;
     RECT  30.953 27.12 31.633 27.336 ;
     RECT  30.881 51.12 31.637 51.384 ;
     RECT  31.381 21.744 31.669 22.296 ;
     RECT  30.845 12.528 31.673 14.568 ;
     RECT  31.237 36.576 31.777 36.84 ;
     RECT  30.853 37.872 31.777 40.632 ;
     RECT  31.673 12.528 31.889 14.472 ;
     RECT  31.669 21.744 31.916 22.728 ;
     RECT  31.889 12.528 31.921 13.56 ;
     RECT  31.916 21.744 31.925 22.824 ;
     RECT  31.777 36.576 31.925 40.632 ;
     RECT  31.925 21.984 31.957 22.824 ;
     RECT  31.421 32.832 31.993 33.24 ;
     RECT  31.309 44.448 31.997 50.136 ;
     RECT  30.917 4.176 32.029 9.384 ;
     RECT  31.309 10.56 32.029 10.584 ;
     RECT  31.921 12.24 32.06 13.56 ;
     RECT  32.029 4.176 32.101 10.584 ;
     RECT  31.957 21.984 32.105 23.4 ;
     RECT  31.093 2.256 32.137 3.144 ;
     RECT  32.101 4.176 32.137 10.824 ;
     RECT  32.137 2.256 32.195 10.824 ;
     RECT  32.06 12.192 32.245 13.56 ;
     RECT  31.925 38.64 32.245 40.632 ;
     RECT  31.561 41.904 32.245 41.976 ;
     RECT  32.195 10.56 32.281 10.824 ;
     RECT  32.245 11.904 32.281 13.56 ;
     RECT  31.381 31.344 32.281 31.368 ;
     RECT  32.281 30.912 32.317 31.368 ;
     RECT  30.881 35.04 32.353 35.064 ;
     RECT  32.195 2.256 32.393 9.576 ;
     RECT  32.245 38.64 32.461 41.976 ;
     RECT  32.393 2.256 32.501 9.384 ;
     RECT  32.317 30.672 32.533 31.368 ;
     RECT  31.993 32.832 32.533 33.72 ;
     RECT  32.501 2.256 32.537 8.76 ;
     RECT  32.533 30.672 32.605 33.72 ;
     RECT  32.353 34.848 32.605 35.064 ;
     RECT  30.773 24.912 32.677 24.936 ;
     RECT  31.633 26.208 32.677 27.336 ;
     RECT  32.605 30.672 32.681 35.064 ;
     RECT  32.461 38.64 32.681 42.312 ;
     RECT  31.097 16.56 32.861 17.496 ;
     RECT  32.281 10.56 32.897 13.56 ;
     RECT  32.681 30.72 32.897 35.064 ;
     RECT  32.861 17.184 32.929 17.496 ;
     RECT  31.925 36.576 32.929 37.032 ;
     RECT  32.897 11.76 32.933 13.56 ;
     RECT  32.677 24.912 33.001 27.336 ;
     RECT  33.001 24.192 33.041 27.336 ;
     RECT  32.929 36.576 33.041 37.608 ;
     RECT  33.068 19.008 33.101 19.032 ;
     RECT  32.897 10.56 33.113 10.68 ;
     RECT  33.101 19.008 33.155 19.128 ;
     RECT  33.155 19.104 33.185 19.128 ;
     RECT  32.681 40.128 33.365 42.312 ;
     RECT  32.897 30.72 33.491 31.368 ;
     RECT  33.491 30.768 33.545 31.368 ;
     RECT  32.897 32.736 33.545 35.064 ;
     RECT  31.997 44.736 33.577 50.136 ;
     RECT  31.637 51.36 33.577 51.384 ;
     RECT  33.545 32.784 33.617 35.064 ;
     RECT  32.681 38.64 33.617 38.664 ;
     RECT  32.537 2.256 33.653 3.336 ;
     RECT  32.641 14.64 33.761 14.664 ;
     RECT  32.105 21.984 33.761 22.776 ;
     RECT  33.041 37.584 33.829 37.608 ;
     RECT  33.113 10.56 33.833 10.584 ;
     RECT  33.365 40.128 33.937 40.632 ;
     RECT  33.365 41.904 33.937 42.312 ;
     RECT  32.929 17.184 34.009 17.64 ;
     RECT  32.933 12.192 34.117 13.56 ;
     RECT  32.965 20.976 34.117 21 ;
     RECT  33.761 22.032 34.117 22.776 ;
     RECT  33.041 24.192 34.117 24.216 ;
     RECT  34.117 12.096 34.124 13.56 ;
     RECT  34.124 12.096 34.189 13.848 ;
     RECT  33.577 44.736 34.357 51.384 ;
     RECT  33.041 25.44 34.369 27.336 ;
     RECT  33.469 15.984 34.477 16.008 ;
     RECT  33.545 31.344 34.585 31.368 ;
     RECT  32.537 4.32 34.657 8.76 ;
     RECT  33.653 2.256 34.693 3.144 ;
     RECT  34.657 4.32 34.693 9.336 ;
     RECT  34.117 20.16 34.729 21 ;
     RECT  31.885 29.472 34.729 29.496 ;
     RECT  34.117 35.52 34.765 35.544 ;
     RECT  33.041 36.576 34.765 36.6 ;
     RECT  34.693 2.256 34.808 9.336 ;
     RECT  34.189 11.76 34.808 13.848 ;
     RECT  34.477 15.312 34.808 16.008 ;
     RECT  34.009 17.088 34.808 17.64 ;
     RECT  34.729 19.344 34.808 21 ;
     RECT  34.117 22.032 34.808 24.216 ;
     RECT  34.369 25.44 34.808 27.912 ;
     RECT  34.729 29.04 34.808 29.496 ;
     RECT  34.585 31.344 34.808 31.8 ;
     RECT  33.617 32.784 34.808 33.816 ;
     RECT  34.765 35.52 34.808 36.6 ;
     RECT  33.829 37.584 34.808 38.136 ;
     RECT  33.937 39.216 34.808 40.632 ;
     RECT  33.937 41.904 34.808 42.744 ;
     RECT  34.357 44.352 34.808 51.384 ;
     RECT  34.808 2.148 34.912 51.852 ;
     RECT  34.912 2.256 35.104 51.582 ;
     RECT  35.104 4.944 35.165 18.168 ;
     RECT  35.104 20.16 35.603 29.448 ;
     RECT  35.104 2.256 35.669 3.432 ;
     RECT  35.603 26.064 35.699 29.448 ;
     RECT  35.165 14.256 35.705 18.168 ;
     RECT  35.705 14.496 35.777 18.168 ;
     RECT  35.104 41.904 35.849 42.744 ;
     RECT  35.777 15.024 35.993 18.168 ;
     RECT  35.993 15.024 36.101 15.048 ;
     RECT  35.104 34.656 36.101 38.232 ;
     RECT  35.993 16.272 36.137 18.168 ;
     RECT  36.085 40.176 36.172 40.2 ;
     RECT  35.165 4.944 36.173 13.128 ;
     RECT  35.699 26.064 36.179 29.352 ;
     RECT  35.104 31.152 36.205 32.904 ;
     RECT  36.173 4.944 36.245 9.864 ;
     RECT  35.603 20.544 36.245 24.408 ;
     RECT  36.101 34.656 36.245 35.352 ;
     RECT  36.173 10.944 36.389 13.128 ;
     RECT  35.669 2.256 36.461 2.856 ;
     RECT  36.461 2.256 36.569 2.28 ;
     RECT  36.101 36.576 36.637 38.232 ;
     RECT  35.104 44.736 36.641 51.144 ;
     RECT  36.205 31.152 36.853 33 ;
     RECT  36.637 36.576 36.893 38.568 ;
     RECT  36.137 16.896 36.925 18.168 ;
     RECT  36.245 20.544 36.949 21.384 ;
     RECT  36.949 20.16 37.036 21.384 ;
     RECT  36.241 3.936 37.073 3.96 ;
     RECT  36.925 16.896 37.105 18.84 ;
     RECT  36.245 22.512 37.105 24.408 ;
     RECT  37.105 16.608 37.109 18.84 ;
     RECT  36.853 31.152 37.109 33.384 ;
     RECT  36.389 10.944 37.181 12.792 ;
     RECT  37.181 11.232 37.289 12.792 ;
     RECT  36.179 26.064 37.289 28.872 ;
     RECT  36.245 4.944 37.357 8.856 ;
     RECT  36.245 9.84 37.357 9.864 ;
     RECT  37.109 16.608 37.361 18.168 ;
     RECT  37.289 26.064 37.361 28.584 ;
     RECT  36.641 51.12 37.397 51.144 ;
     RECT  37.361 16.896 37.433 18.168 ;
     RECT  37.105 22.512 37.433 24.504 ;
     RECT  37.289 11.952 37.537 12.792 ;
     RECT  37.433 16.896 37.541 17.976 ;
     RECT  36.893 36.576 37.541 38.472 ;
     RECT  37.537 11.952 37.573 13.368 ;
     RECT  37.036 20.544 37.613 21.384 ;
     RECT  37.433 22.512 37.613 22.92 ;
     RECT  37.433 23.904 37.645 24.504 ;
     RECT  37.177 40.608 37.645 40.632 ;
     RECT  37.501 2.784 37.649 2.808 ;
     RECT  37.361 26.544 37.685 28.584 ;
     RECT  37.573 11.952 37.721 14.232 ;
     RECT  37.357 4.944 37.825 9.864 ;
     RECT  37.825 4.896 37.861 9.864 ;
     RECT  36.245 35.136 37.969 35.352 ;
     RECT  37.109 31.152 38.003 33 ;
     RECT  37.613 22.512 38.005 22.824 ;
     RECT  37.721 11.952 38.009 14.136 ;
     RECT  38.003 31.488 38.009 33 ;
     RECT  37.861 4.896 38.081 9.96 ;
     RECT  38.081 4.896 38.149 9.864 ;
     RECT  38.009 32.592 38.149 33 ;
     RECT  38.005 22.224 38.225 22.824 ;
     RECT  37.645 40.32 38.225 40.632 ;
     RECT  38.041 43.68 38.297 43.704 ;
     RECT  37.541 16.896 38.401 17.88 ;
     RECT  38.401 16.56 38.509 17.88 ;
     RECT  37.613 20.544 38.509 21.048 ;
     RECT  38.009 11.952 38.545 13.704 ;
     RECT  38.509 16.56 38.581 18.168 ;
     RECT  38.509 19.776 38.581 21.048 ;
     RECT  37.685 26.544 38.653 27.432 ;
     RECT  37.685 28.416 38.653 28.584 ;
     RECT  37.541 36.576 38.653 38.28 ;
     RECT  38.581 16.56 38.693 18.504 ;
     RECT  38.581 19.728 38.725 21.048 ;
     RECT  38.653 26.544 38.765 28.584 ;
     RECT  38.149 4.224 38.801 9.864 ;
     RECT  38.693 16.608 38.801 18.504 ;
     RECT  37.969 35.04 38.833 35.352 ;
     RECT  38.653 36.528 38.833 38.28 ;
     RECT  38.545 11.424 38.837 13.704 ;
     RECT  38.833 35.04 38.905 38.28 ;
     RECT  38.905 34.752 38.941 38.28 ;
     RECT  37.249 30.048 38.977 30.072 ;
     RECT  38.009 31.488 38.977 31.512 ;
     RECT  38.941 34.752 39.089 38.808 ;
     RECT  38.225 40.608 39.205 40.632 ;
     RECT  35.849 41.904 39.205 42.456 ;
     RECT  37.645 23.904 39.253 24.888 ;
     RECT  38.225 22.224 39.301 22.776 ;
     RECT  39.205 40.608 39.373 42.456 ;
     RECT  38.977 30.048 39.445 31.512 ;
     RECT  38.801 4.944 39.733 9.864 ;
     RECT  38.837 11.424 39.733 13.656 ;
     RECT  39.373 40.608 39.877 42.744 ;
     RECT  39.877 40.608 39.913 43.128 ;
     RECT  39.685 3.936 39.949 3.96 ;
     RECT  39.733 4.944 39.949 13.656 ;
     RECT  39.253 23.856 39.985 24.888 ;
     RECT  39.949 3.936 40.208 13.656 ;
     RECT  38.801 16.896 40.208 18.504 ;
     RECT  38.725 19.68 40.208 21.048 ;
     RECT  39.301 22.032 40.208 22.776 ;
     RECT  39.985 23.856 40.208 24.936 ;
     RECT  38.765 26.544 40.208 28.056 ;
     RECT  39.445 29.616 40.208 31.512 ;
     RECT  38.149 32.592 40.208 33.432 ;
     RECT  39.089 34.752 40.208 37.656 ;
     RECT  39.089 38.784 40.208 38.808 ;
     RECT  39.913 40.608 40.208 43.56 ;
     RECT  36.641 44.736 40.208 50.136 ;
     RECT  40.208 2.148 40.312 51.852 ;
     RECT  40.312 2.304 40.504 51.582 ;
     RECT  40.504 34.752 40.529 35.496 ;
     RECT  40.504 2.304 40.637 12.888 ;
     RECT  40.637 2.304 40.691 12.792 ;
     RECT  40.504 24.912 40.745 25.512 ;
     RECT  40.504 36.528 40.781 39.288 ;
     RECT  40.504 30.864 40.853 31.368 ;
     RECT  40.504 17.136 40.889 18.504 ;
     RECT  40.504 19.632 40.925 22.92 ;
     RECT  40.781 36.528 41.033 38.616 ;
     RECT  40.691 2.304 41.213 2.856 ;
     RECT  40.691 4.512 41.249 12.792 ;
     RECT  40.504 51.264 41.249 51.288 ;
     RECT  40.504 40.608 41.497 40.92 ;
     RECT  40.504 42.432 41.497 43.32 ;
     RECT  40.504 44.448 41.497 50.136 ;
     RECT  40.889 17.184 41.605 18.504 ;
     RECT  40.925 19.632 41.605 20.952 ;
     RECT  40.529 34.752 41.717 35.256 ;
     RECT  41.497 40.608 41.717 50.136 ;
     RECT  41.717 40.608 41.785 41.304 ;
     RECT  40.853 31.344 41.789 31.368 ;
     RECT  40.925 22.032 41.845 22.92 ;
     RECT  41.497 24.048 41.845 24.072 ;
     RECT  40.745 25.056 41.845 25.272 ;
     RECT  41.845 22.032 41.891 25.272 ;
     RECT  41.717 42.432 41.929 50.136 ;
     RECT  41.891 24.576 41.969 25.272 ;
     RECT  40.504 26.544 41.969 27.816 ;
     RECT  41.969 26.544 42.005 27.432 ;
     RECT  41.249 6.048 42.145 12.792 ;
     RECT  40.504 13.92 42.145 16.008 ;
     RECT  40.504 32.448 42.221 33.528 ;
     RECT  42.145 6.048 42.227 16.008 ;
     RECT  41.929 42.432 42.257 50.856 ;
     RECT  42.221 32.496 42.293 33.528 ;
     RECT  41.605 17.184 42.325 20.952 ;
     RECT  42.227 13.632 42.365 16.008 ;
     RECT  41.717 34.8 42.373 35.256 ;
     RECT  41.033 36.528 42.373 38.472 ;
     RECT  42.005 26.544 42.397 27.336 ;
     RECT  41.891 22.032 42.437 23.544 ;
     RECT  42.373 34.8 42.46 38.472 ;
     RECT  41.213 2.304 42.469 2.424 ;
     RECT  41.249 4.512 42.577 4.968 ;
     RECT  42.227 6.048 42.577 12.6 ;
     RECT  42.46 36.576 42.577 38.472 ;
     RECT  42.577 36.576 42.689 38.664 ;
     RECT  42.577 4.512 42.721 12.6 ;
     RECT  42.437 22.224 42.725 23.544 ;
     RECT  42.365 13.872 42.757 16.008 ;
     RECT  42.325 16.992 42.757 20.952 ;
     RECT  40.504 29.808 42.757 29.832 ;
     RECT  42.469 31.296 42.757 31.32 ;
     RECT  42.469 2.304 42.761 2.952 ;
     RECT  42.397 26.496 42.761 27.336 ;
     RECT  42.689 36.576 42.761 38.472 ;
     RECT  42.761 2.352 42.793 2.952 ;
     RECT  42.721 3.936 42.793 12.6 ;
     RECT  42.757 13.872 42.869 20.952 ;
     RECT  42.293 32.832 42.901 33.528 ;
     RECT  42.46 34.8 42.941 35.256 ;
     RECT  41.785 39.984 42.941 41.304 ;
     RECT  42.757 29.808 43.013 31.32 ;
     RECT  42.761 36.576 43.013 38.232 ;
     RECT  42.257 42.432 43.225 43.128 ;
     RECT  42.257 44.448 43.225 50.856 ;
     RECT  42.725 23.52 43.261 23.544 ;
     RECT  42.941 40.032 43.261 41.304 ;
     RECT  43.225 42.432 43.261 50.856 ;
     RECT  42.793 2.352 43.301 12.6 ;
     RECT  41.969 25.056 43.333 25.272 ;
     RECT  42.761 26.544 43.369 27.336 ;
     RECT  43.301 5.664 43.373 12.6 ;
     RECT  43.013 31.008 43.405 31.32 ;
     RECT  43.333 25.056 43.445 25.56 ;
     RECT  43.261 23.52 43.549 23.928 ;
     RECT  43.445 25.056 43.549 25.272 ;
     RECT  42.941 35.232 43.549 35.256 ;
     RECT  43.013 36.576 43.549 36.792 ;
     RECT  43.301 2.4 43.553 4.632 ;
     RECT  42.869 15.312 43.657 20.952 ;
     RECT  42.725 22.224 43.657 22.488 ;
     RECT  43.657 15.312 43.661 22.488 ;
     RECT  43.553 2.928 43.667 4.632 ;
     RECT  43.373 11.952 43.697 12.6 ;
     RECT  43.013 29.808 43.697 29.832 ;
     RECT  43.661 16.512 43.765 22.488 ;
     RECT  43.549 23.52 43.765 25.272 ;
     RECT  43.661 15.312 43.769 15.336 ;
     RECT  43.765 16.512 43.811 25.272 ;
     RECT  43.013 38.016 43.877 38.232 ;
     RECT  43.667 2.928 43.913 3.672 ;
     RECT  43.373 5.664 43.913 10.92 ;
     RECT  43.811 23.28 44.021 25.272 ;
     RECT  43.811 16.512 44.093 20.664 ;
     RECT  44.021 25.104 44.129 25.272 ;
     RECT  42.901 32.832 44.149 33.624 ;
     RECT  44.149 32.832 44.161 34.248 ;
     RECT  43.261 40.032 44.165 50.856 ;
     RECT  43.405 31.008 44.201 31.416 ;
     RECT  44.165 42 44.339 50.856 ;
     RECT  44.161 32.496 44.341 34.248 ;
     RECT  43.549 35.232 44.341 36.792 ;
     RECT  44.093 16.512 44.345 19.56 ;
     RECT  44.021 23.28 44.381 23.976 ;
     RECT  44.341 32.496 44.387 36.792 ;
     RECT  43.913 6.096 44.449 10.92 ;
     RECT  43.697 11.952 44.449 11.976 ;
     RECT  43.369 26.544 44.485 27.624 ;
     RECT  44.387 34.704 44.561 36.792 ;
     RECT  44.165 40.032 44.629 40.968 ;
     RECT  43.913 3.024 44.917 3.672 ;
     RECT  42.869 13.872 44.953 14.232 ;
     RECT  44.485 26.544 44.953 27.672 ;
     RECT  44.953 13.824 44.989 14.232 ;
     RECT  44.449 6.096 45.025 11.976 ;
     RECT  44.917 3.024 45.133 4.536 ;
     RECT  44.953 26.544 45.169 28.44 ;
     RECT  45.025 6.096 45.241 12.504 ;
     RECT  44.989 15.456 45.241 15.48 ;
     RECT  45.241 15.216 45.277 15.48 ;
     RECT  44.345 16.512 45.277 19.128 ;
     RECT  44.381 23.952 45.385 23.976 ;
     RECT  44.989 13.632 45.421 14.232 ;
     RECT  45.277 15.216 45.421 19.128 ;
     RECT  45.385 23.904 45.493 23.976 ;
     RECT  44.129 25.248 45.493 25.272 ;
     RECT  44.629 39.312 45.529 40.968 ;
     RECT  44.339 42.432 45.529 42.84 ;
     RECT  44.339 43.872 45.529 50.856 ;
     RECT  45.133 2.832 45.608 4.536 ;
     RECT  45.241 5.856 45.608 12.504 ;
     RECT  45.421 13.632 45.608 19.128 ;
     RECT  44.093 20.544 45.608 20.664 ;
     RECT  43.811 21.936 45.608 21.96 ;
     RECT  45.493 23.904 45.608 25.272 ;
     RECT  45.169 26.544 45.608 29.352 ;
     RECT  44.387 32.496 45.608 33.384 ;
     RECT  44.561 34.704 45.608 36.648 ;
     RECT  45.529 39.264 45.608 40.968 ;
     RECT  45.529 42.432 45.608 50.856 ;
     RECT  45.608 2.148 45.712 51.852 ;
     RECT  45.712 2.418 45.904 51.582 ;
     RECT  45.904 2.418 46.001 3.432 ;
     RECT  45.904 22.944 46.001 29.352 ;
     RECT  45.904 19.872 46.019 20.664 ;
     RECT  45.904 5.232 46.163 18.84 ;
     RECT  46.001 22.944 46.217 23.928 ;
     RECT  46.001 25.248 46.289 29.352 ;
     RECT  45.904 42.768 46.325 50.856 ;
     RECT  45.904 32.832 46.361 41.304 ;
     RECT  46.217 22.944 46.396 22.968 ;
     RECT  45.904 21.936 46.433 21.96 ;
     RECT  46.325 42.768 46.477 50.136 ;
     RECT  46.289 29.28 46.541 29.352 ;
     RECT  46.163 5.232 46.613 18.264 ;
     RECT  46.001 2.418 46.753 3.144 ;
     RECT  46.289 25.248 46.787 27.912 ;
     RECT  46.361 34.224 46.793 41.304 ;
     RECT  46.541 29.28 46.829 29.304 ;
     RECT  46.613 5.232 46.835 18.216 ;
     RECT  46.787 25.248 46.969 27.864 ;
     RECT  46.969 24.624 47.009 27.864 ;
     RECT  46.477 43.248 47.045 50.136 ;
     RECT  46.835 5.232 47.077 10.584 ;
     RECT  46.835 11.856 47.117 12.888 ;
     RECT  47.077 5.136 47.185 10.584 ;
     RECT  47.009 24.624 47.185 27.624 ;
     RECT  46.793 34.608 47.221 41.304 ;
     RECT  47.185 4.656 47.261 10.584 ;
     RECT  47.185 24.192 47.333 27.624 ;
     RECT  47.261 4.656 47.369 10.488 ;
     RECT  47.369 5.232 47.477 10.488 ;
     RECT  47.117 12.528 47.513 12.888 ;
     RECT  47.477 5.424 47.585 10.488 ;
     RECT  47.585 5.712 47.693 10.488 ;
     RECT  47.221 34.608 47.729 42.216 ;
     RECT  46.753 2.304 47.761 3.144 ;
     RECT  47.729 34.704 47.891 42.216 ;
     RECT  47.513 12.528 47.945 12.552 ;
     RECT  46.019 20.304 47.977 20.664 ;
     RECT  47.869 21.696 47.977 21.72 ;
     RECT  47.977 20.304 48.017 21.72 ;
     RECT  47.891 34.704 48.017 42.168 ;
     RECT  47.045 43.248 48.085 43.272 ;
     RECT  47.045 44.448 48.085 50.136 ;
     RECT  47.761 2.304 48.161 3.288 ;
     RECT  47.693 6.24 48.197 10.488 ;
     RECT  46.835 14.208 48.265 18.216 ;
     RECT  47.333 24.24 48.409 27.624 ;
     RECT  48.197 6.288 48.485 10.488 ;
     RECT  47.413 51.312 48.485 51.336 ;
     RECT  48.017 20.304 48.593 21.288 ;
     RECT  48.161 2.544 48.629 3.288 ;
     RECT  48.485 6.336 48.769 10.488 ;
     RECT  48.409 23.376 48.877 27.624 ;
     RECT  48.589 4.368 48.989 4.392 ;
     RECT  48.265 14.208 49.097 18.792 ;
     RECT  48.017 34.704 49.129 40.056 ;
     RECT  48.841 29.088 49.133 29.64 ;
     RECT  48.593 20.304 49.205 21.192 ;
     RECT  46.361 32.832 49.237 32.856 ;
     RECT  49.129 34.704 49.237 40.248 ;
     RECT  48.017 41.664 49.237 42.168 ;
     RECT  49.237 32.832 49.273 33.336 ;
     RECT  49.097 14.208 49.309 17.64 ;
     RECT  49.097 18.768 49.313 18.792 ;
     RECT  48.877 22.8 49.333 27.624 ;
     RECT  49.205 20.64 49.349 21.192 ;
     RECT  49.333 22.752 49.379 27.624 ;
     RECT  49.129 30.768 49.381 30.792 ;
     RECT  49.379 24.24 49.385 27.624 ;
     RECT  49.273 32.832 49.427 33.432 ;
     RECT  48.769 6.336 49.453 11.16 ;
     RECT  49.349 21.072 49.457 21.192 ;
     RECT  49.381 30.72 49.465 31.416 ;
     RECT  49.237 34.704 49.561 42.168 ;
     RECT  48.085 43.248 49.561 50.136 ;
     RECT  49.385 24.528 49.565 27.624 ;
     RECT  49.561 34.704 49.571 50.136 ;
     RECT  49.565 26.544 49.669 27.624 ;
     RECT  49.133 29.088 49.669 29.112 ;
     RECT  49.571 38.16 49.669 50.136 ;
     RECT  49.309 14.112 49.709 17.64 ;
     RECT  49.669 38.16 49.709 50.616 ;
     RECT  49.565 24.528 49.853 25.272 ;
     RECT  49.273 13.104 49.961 13.128 ;
     RECT  49.427 33.312 49.993 33.432 ;
     RECT  49.571 34.704 49.993 37.08 ;
     RECT  49.993 33.312 50.033 37.08 ;
     RECT  49.453 6.192 50.101 11.16 ;
     RECT  49.379 22.752 50.101 22.872 ;
     RECT  49.709 16.8 50.281 17.64 ;
     RECT  49.709 43.776 50.317 50.616 ;
     RECT  50.101 22.128 50.389 22.872 ;
     RECT  50.389 4.752 50.677 4.776 ;
     RECT  50.101 6.096 50.677 11.16 ;
     RECT  49.709 38.16 50.677 42.792 ;
     RECT  50.317 43.776 50.677 51.432 ;
     RECT  50.677 4.752 50.713 11.16 ;
     RECT  48.629 2.544 51.008 2.568 ;
     RECT  50.713 4.752 51.008 11.544 ;
     RECT  49.709 14.112 51.008 15.768 ;
     RECT  50.281 16.8 51.008 17.976 ;
     RECT  50.101 19.2 51.008 19.224 ;
     RECT  49.457 21.072 51.008 21.096 ;
     RECT  50.389 22.128 51.008 23.4 ;
     RECT  49.853 24.624 51.008 25.272 ;
     RECT  49.669 26.544 51.008 29.112 ;
     RECT  49.465 31.104 51.008 31.416 ;
     RECT  50.033 33.312 51.008 34.2 ;
     RECT  50.033 35.232 51.008 37.08 ;
     RECT  50.677 38.16 51.008 51.432 ;
     RECT  51.008 2.148 51.112 51.852 ;
     RECT  51.112 2.418 51.304 51.582 ;
     RECT  51.304 34.176 51.473 37.08 ;
     RECT  51.304 6.096 51.509 11.16 ;
     RECT  51.473 34.704 51.539 37.08 ;
     RECT  51.304 13.824 51.545 14.136 ;
     RECT  51.539 36.624 51.581 37.08 ;
     RECT  51.304 23.328 51.587 27.96 ;
     RECT  51.304 28.944 52.013 31.944 ;
     RECT  51.304 38.448 52.115 51.432 ;
     RECT  52.013 30.768 52.121 31.944 ;
     RECT  51.304 2.496 52.229 3.336 ;
     RECT  51.304 15.696 52.405 17.928 ;
     RECT  52.405 15.552 52.477 17.928 ;
     RECT  52.477 15.552 52.513 18.12 ;
     RECT  51.587 23.808 52.553 27.96 ;
     RECT  52.553 25.248 52.657 27.96 ;
     RECT  52.013 28.944 52.657 29.64 ;
     RECT  51.539 35.232 52.765 35.256 ;
     RECT  52.657 25.248 52.769 29.64 ;
     RECT  51.545 13.824 52.837 13.848 ;
     RECT  52.765 34.368 52.909 35.256 ;
     RECT  52.121 31.008 52.913 31.944 ;
     RECT  52.909 34.128 52.945 35.256 ;
     RECT  51.581 36.624 52.945 37.032 ;
     RECT  51.509 6.096 53.017 9.864 ;
     RECT  52.837 13.632 53.017 13.848 ;
     RECT  53.017 13.632 53.125 14.52 ;
     RECT  52.513 15.504 53.125 18.12 ;
     RECT  52.115 38.448 53.161 42.504 ;
     RECT  51.509 11.136 53.197 11.16 ;
     RECT  52.769 25.248 53.201 28.488 ;
     RECT  52.945 34.128 53.221 37.032 ;
     RECT  53.161 38.448 53.221 42.648 ;
     RECT  53.221 34.128 53.237 42.648 ;
     RECT  53.237 36.48 53.267 42.648 ;
     RECT  53.125 13.632 53.273 18.12 ;
     RECT  53.273 13.632 53.309 16.536 ;
     RECT  53.267 37.824 53.315 42.648 ;
     RECT  53.273 17.712 53.345 18.12 ;
     RECT  53.315 37.824 53.363 39.864 ;
     RECT  53.315 41.136 53.363 42.648 ;
     RECT  53.017 6.096 53.485 10.056 ;
     RECT  53.197 11.136 53.485 11.688 ;
     RECT  53.363 38.832 53.561 38.856 ;
     RECT  53.363 41.52 53.633 42.648 ;
     RECT  53.345 18.096 53.741 18.12 ;
     RECT  53.309 13.632 53.777 14.568 ;
     RECT  53.237 34.128 53.849 35.256 ;
     RECT  53.777 13.632 53.881 13.992 ;
     RECT  52.769 29.616 53.996 29.64 ;
     RECT  52.913 31.008 53.996 31.032 ;
     RECT  53.633 41.664 54.025 42.648 ;
     RECT  52.115 43.632 54.025 51.432 ;
     RECT  52.553 23.808 54.037 23.88 ;
     RECT  53.267 36.48 54.083 36.504 ;
     RECT  53.953 32.976 54.085 33 ;
     RECT  53.996 29.616 54.097 31.032 ;
     RECT  54.085 32.496 54.173 33 ;
     RECT  53.485 6.096 54.209 11.688 ;
     RECT  54.037 23.808 54.241 23.928 ;
     RECT  53.201 25.248 54.241 25.272 ;
     RECT  54.097 29.472 54.323 31.032 ;
     RECT  54.241 23.808 54.325 25.272 ;
     RECT  54.209 6.096 54.349 11.16 ;
     RECT  53.309 15.552 54.457 16.536 ;
     RECT  53.849 34.8 54.461 35.256 ;
     RECT  54.173 32.976 54.497 33 ;
     RECT  54.325 25.248 54.529 25.272 ;
     RECT  53.201 26.544 54.529 28.488 ;
     RECT  54.349 5.904 54.565 11.16 ;
     RECT  53.363 37.824 54.569 37.848 ;
     RECT  54.061 19.68 54.605 19.704 ;
     RECT  54.461 34.848 54.673 35.256 ;
     RECT  54.565 5.28 54.677 11.16 ;
     RECT  54.493 40.032 54.709 40.056 ;
     RECT  54.325 23.808 54.749 23.928 ;
     RECT  54.745 18.672 54.817 18.696 ;
     RECT  54.709 40.032 54.821 40.152 ;
     RECT  54.817 18.672 54.857 19.416 ;
     RECT  54.457 15.552 54.965 17.064 ;
     RECT  54.529 25.248 55.045 28.488 ;
     RECT  54.323 29.472 55.045 29.496 ;
     RECT  54.493 22.704 55.109 22.728 ;
     RECT  54.965 15.552 55.141 16.344 ;
     RECT  54.025 41.664 55.141 51.432 ;
     RECT  53.881 13.104 55.181 13.992 ;
     RECT  54.673 34.848 55.217 36.36 ;
     RECT  54.323 30.864 55.249 31.032 ;
     RECT  55.045 25.248 55.253 29.496 ;
     RECT  55.181 13.968 55.285 13.992 ;
     RECT  55.141 15.264 55.285 16.344 ;
     RECT  54.749 23.856 55.325 23.928 ;
     RECT  55.253 25.248 55.361 28.488 ;
     RECT  55.141 41.616 55.388 51.432 ;
     RECT  52.229 3.312 55.393 3.336 ;
     RECT  55.033 52.704 55.609 52.728 ;
     RECT  55.249 30.864 55.717 31.464 ;
     RECT  55.609 52.464 55.717 52.728 ;
     RECT  54.677 6.096 56.077 11.16 ;
     RECT  55.213 12.48 56.077 12.504 ;
     RECT  56.077 6.096 56.204 12.504 ;
     RECT  55.285 13.968 56.204 16.344 ;
     RECT  56.204 6.096 56.257 16.344 ;
     RECT  56.257 6.096 56.293 16.392 ;
     RECT  55.717 30.864 56.401 31.848 ;
     RECT  54.673 33.024 56.401 33.048 ;
     RECT  55.393 2.496 56.408 3.336 ;
     RECT  56.293 5.856 56.408 16.392 ;
     RECT  55.681 17.472 56.408 17.496 ;
     RECT  54.857 18.816 56.408 19.416 ;
     RECT  55.325 23.904 56.408 23.928 ;
     RECT  55.361 25.248 56.408 28.008 ;
     RECT  55.753 29.76 56.408 29.784 ;
     RECT  56.401 30.864 56.408 33.048 ;
     RECT  55.217 34.848 56.408 36.072 ;
     RECT  54.673 37.872 56.408 37.896 ;
     RECT  54.821 40.032 56.408 40.056 ;
     RECT  55.388 41.472 56.408 51.432 ;
     RECT  55.717 52.464 56.408 53.112 ;
     RECT  56.408 2.148 56.512 53.112 ;
     RECT  56.512 2.418 56.704 53.112 ;
     RECT  56.704 5.184 56.765 5.208 ;
     RECT  56.704 6.384 56.765 14.232 ;
     RECT  56.765 12.288 56.819 14.232 ;
     RECT  56.765 10.848 57.017 11.16 ;
     RECT  56.704 30.864 57.125 33.048 ;
     RECT  56.704 35.232 57.125 36.024 ;
     RECT  56.704 23.328 57.155 23.928 ;
     RECT  56.704 40.416 57.196 40.44 ;
     RECT  56.704 19.248 57.197 21.096 ;
     RECT  56.704 25.104 57.197 27.912 ;
     RECT  56.704 4.176 57.413 4.2 ;
     RECT  56.704 15.552 57.413 16.392 ;
     RECT  57.155 23.904 57.491 23.928 ;
     RECT  57.197 25.104 57.521 27.672 ;
     RECT  57.521 25.152 57.557 27.672 ;
     RECT  56.819 12.288 57.629 13.656 ;
     RECT  57.557 25.152 57.629 25.272 ;
     RECT  57.413 15.744 57.665 16.392 ;
     RECT  56.704 17.472 57.665 17.496 ;
     RECT  57.125 30.864 57.773 31.992 ;
     RECT  56.765 6.384 57.809 9.864 ;
     RECT  57.125 35.232 57.841 35.88 ;
     RECT  57.809 6.72 57.881 9.864 ;
     RECT  56.704 29.28 57.913 29.4 ;
     RECT  57.197 19.248 57.917 20.52 ;
     RECT  57.773 30.864 58.117 31.656 ;
     RECT  57.841 34.8 58.193 35.88 ;
     RECT  57.017 10.848 58.237 10.872 ;
     RECT  57.629 12.288 58.237 13.608 ;
     RECT  58.117 30.768 58.241 31.656 ;
     RECT  58.193 34.128 58.259 35.88 ;
     RECT  56.704 42.144 58.259 53.112 ;
     RECT  57.665 15.744 58.313 16.104 ;
     RECT  57.913 29.232 58.385 29.4 ;
     RECT  57.769 37.056 58.385 37.08 ;
     RECT  58.241 30.768 58.421 31.416 ;
     RECT  57.917 19.968 58.453 20.52 ;
     RECT  57.125 33.024 58.453 33.048 ;
     RECT  58.259 34.128 58.453 34.152 ;
     RECT  58.453 33.024 58.493 34.152 ;
     RECT  58.421 30.768 58.529 31.176 ;
     RECT  57.557 26.592 58.597 27.672 ;
     RECT  58.259 35.232 58.633 35.88 ;
     RECT  58.259 42.192 58.705 53.112 ;
     RECT  58.313 15.744 58.741 15.768 ;
     RECT  58.453 19.968 58.781 21.096 ;
     RECT  58.237 10.848 58.817 13.608 ;
     RECT  58.705 42.192 58.817 53.16 ;
     RECT  58.633 17.904 58.957 17.928 ;
     RECT  58.493 33.024 58.961 33.816 ;
     RECT  58.957 17.904 59.029 18.648 ;
     RECT  58.781 19.968 59.033 20.52 ;
     RECT  58.385 29.232 59.033 29.256 ;
     RECT  59.029 17.04 59.075 18.648 ;
     RECT  58.597 26.256 59.101 27.672 ;
     RECT  57.629 25.248 59.173 25.272 ;
     RECT  59.101 26.256 59.173 27.912 ;
     RECT  58.817 13.104 59.177 13.608 ;
     RECT  59.075 17.04 59.213 17.928 ;
     RECT  58.817 42.432 59.245 53.16 ;
     RECT  58.961 33.792 59.321 33.816 ;
     RECT  58.633 35.232 59.321 36.12 ;
     RECT  57.881 6.912 59.357 9.864 ;
     RECT  59.173 25.248 59.357 27.912 ;
     RECT  58.741 15.312 59.389 15.768 ;
     RECT  58.817 10.848 59.461 11.448 ;
     RECT  59.357 25.248 59.573 26.664 ;
     RECT  59.357 6.912 59.609 9.48 ;
     RECT  59.389 15.312 59.641 16.248 ;
     RECT  59.461 10.704 59.645 11.448 ;
     RECT  59.641 15.216 59.677 16.248 ;
     RECT  59.645 10.704 59.681 10.872 ;
     RECT  59.609 6.912 59.717 6.936 ;
     RECT  59.177 13.104 59.717 13.176 ;
     RECT  58.529 30.768 59.789 30.792 ;
     RECT  59.677 14.976 59.893 16.248 ;
     RECT  59.717 13.104 60.077 13.128 ;
     RECT  59.245 42.432 60.179 53.88 ;
     RECT  59.573 26.208 60.185 26.664 ;
     RECT  60.185 26.64 60.329 26.664 ;
     RECT  60.179 42.432 60.371 52.152 ;
     RECT  59.929 30.192 60.467 30.744 ;
     RECT  60.179 53.136 60.467 53.88 ;
     RECT  59.321 35.232 60.545 35.256 ;
     RECT  60.371 42.432 60.545 51.912 ;
     RECT  59.609 7.92 60.581 9.48 ;
     RECT  60.581 9.456 60.617 9.48 ;
     RECT  59.681 10.704 60.653 10.728 ;
     RECT  60.545 42.528 60.689 51.912 ;
     RECT  59.893 14.928 60.725 16.248 ;
     RECT  60.725 14.928 60.755 16.008 ;
     RECT  60.689 42.768 60.755 51.912 ;
     RECT  60.755 14.928 60.797 15.384 ;
     RECT  60.755 42.768 60.905 51.864 ;
     RECT  61.045 40.896 61.225 40.92 ;
     RECT  61.549 34.944 61.621 35.064 ;
     RECT  61.621 34.944 61.657 36.024 ;
     RECT  60.467 53.856 61.661 53.88 ;
     RECT  61.657 34.464 61.669 36.024 ;
     RECT  61.669 34.176 61.693 36.024 ;
     RECT  60.581 7.92 61.808 7.944 ;
     RECT  61.081 11.952 61.808 11.976 ;
     RECT  60.797 14.976 61.808 15.384 ;
     RECT  59.213 17.904 61.808 17.928 ;
     RECT  60.397 22.848 61.808 22.872 ;
     RECT  61.405 24.24 61.808 24.264 ;
     RECT  59.357 27.648 61.808 27.912 ;
     RECT  60.467 30.72 61.808 30.744 ;
     RECT  59.029 32.448 61.808 32.472 ;
     RECT  61.693 34.176 61.808 36.072 ;
     RECT  61.405 37.104 61.808 37.128 ;
     RECT  61.669 39.504 61.808 39.528 ;
     RECT  61.225 40.512 61.808 40.92 ;
     RECT  60.905 42.768 61.808 51.852 ;
     RECT  61.808 2.148 61.912 51.852 ;
     RECT  61.912 2.418 62.104 51.582 ;
     RECT  62.104 14.976 62.165 15 ;
     RECT  62.104 42.672 62.525 50.376 ;
     RECT  62.104 27.648 63.205 28.2 ;
     RECT  62.104 7.248 63.241 9.384 ;
     RECT  62.104 17.904 63.241 18.792 ;
     RECT  62.104 26.256 63.241 26.28 ;
     RECT  63.205 27.648 63.241 28.776 ;
     RECT  63.241 7.248 63.277 9.672 ;
     RECT  63.241 16.368 63.277 18.888 ;
     RECT  63.241 26.256 63.277 28.776 ;
     RECT  62.525 42.672 63.277 49.896 ;
     RECT  63.277 16.176 63.781 18.888 ;
     RECT  63.277 7.248 63.817 9.864 ;
     RECT  63.277 26.064 63.817 28.776 ;
     RECT  63.781 16.176 63.853 18.984 ;
     RECT  63.277 42.576 63.853 49.896 ;
     RECT  63.853 42.192 64.685 49.896 ;
     RECT  63.817 6.864 64.764 9.864 ;
     RECT  63.853 16.08 64.764 19.08 ;
     RECT  63.817 26.064 64.764 29.064 ;
     RECT  64.685 42.192 64.764 49.8 ;
    LAYER M5 ;
     RECT  19.92 0.016 20.424 0.037 ;
     RECT  19.92 0.037 20.52 0.179 ;
     RECT  19.92 0.179 20.232 1.763 ;
     RECT  2.4 2.137 2.52 2.151 ;
     RECT  7.8 2.137 7.92 2.151 ;
     RECT  13.2 2.137 13.32 2.151 ;
     RECT  18.6 2.137 18.72 2.151 ;
     RECT  24 2.137 24.12 2.151 ;
     RECT  29.4 2.137 29.52 2.151 ;
     RECT  34.8 2.137 34.92 2.151 ;
     RECT  40.2 2.137 40.32 2.151 ;
     RECT  45.6 2.137 45.72 2.151 ;
     RECT  51 2.137 51.12 2.151 ;
     RECT  56.4 2.137 56.52 2.151 ;
     RECT  61.8 2.137 61.92 2.151 ;
     RECT  56.4 2.151 56.712 2.485 ;
     RECT  45.6 2.151 45.912 2.533 ;
     RECT  24 2.151 24.312 2.773 ;
     RECT  18.6 2.151 18.912 2.821 ;
     RECT  19.92 1.763 20.04 2.821 ;
     RECT  40.2 2.151 40.512 2.821 ;
     RECT  18.6 2.821 20.04 2.867 ;
     RECT  29.4 2.151 29.712 3.061 ;
     RECT  40.2 2.821 40.68 3.587 ;
     RECT  40.2 3.587 40.512 3.925 ;
     RECT  29.088 3.061 29.712 4.117 ;
     RECT  28.224 4.117 29.712 4.595 ;
     RECT  43.632 3.397 43.656 4.643 ;
     RECT  13.2 2.151 13.512 4.645 ;
     RECT  45.6 2.533 46.824 5.173 ;
     RECT  45.6 5.173 47.256 5.315 ;
     RECT  7.8 2.151 8.112 5.557 ;
     RECT  45.6 5.315 47.064 5.651 ;
     RECT  33.792 4.501 33.816 5.747 ;
     RECT  18.6 2.867 19.944 5.845 ;
     RECT  39.696 3.925 40.512 5.989 ;
     RECT  13.2 4.645 14.088 6.035 ;
     RECT  39.696 5.989 40.728 6.037 ;
     RECT  16.416 2.773 16.44 6.227 ;
     RECT  51 2.151 51.312 6.277 ;
     RECT  10.368 4.645 10.392 6.323 ;
     RECT  47.04 5.651 47.064 6.323 ;
     RECT  18.336 5.845 19.944 6.565 ;
     RECT  33.552 5.749 33.672 6.659 ;
     RECT  56.208 2.485 56.712 6.805 ;
     RECT  31.344 5.125 31.368 6.851 ;
     RECT  24 2.773 24.408 6.899 ;
     RECT  50.688 6.277 51.312 6.901 ;
     RECT  50.64 6.901 51.312 7.043 ;
     RECT  36.096 7.093 36.12 7.235 ;
     RECT  56.112 6.805 56.712 7.379 ;
     RECT  39.6 6.037 40.728 7.429 ;
     RECT  42.144 6.805 42.168 7.429 ;
     RECT  7.632 5.557 8.112 7.619 ;
     RECT  39.6 7.429 42.168 7.667 ;
     RECT  54.672 7.525 54.696 7.763 ;
     RECT  45.6 5.651 45.912 7.813 ;
     RECT  41.952 7.667 42.168 7.859 ;
     RECT  45.6 7.813 46.008 8.003 ;
     RECT  44.4 6.805 44.424 8.435 ;
     RECT  14.832 7.957 14.856 8.483 ;
     RECT  9.6 7.909 9.624 8.485 ;
     RECT  26.592 7.765 26.616 9.011 ;
     RECT  28.224 4.595 28.248 9.061 ;
     RECT  7.8 7.619 8.112 9.637 ;
     RECT  27.264 9.061 28.248 9.779 ;
     RECT  41.952 7.859 41.976 9.779 ;
     RECT  32.16 9.061 32.184 9.827 ;
     RECT  3.936 8.821 3.96 10.115 ;
     RECT  12 8.437 12.024 10.213 ;
     RECT  50.688 7.043 51.312 10.403 ;
     RECT  7.68 9.637 8.112 10.693 ;
     RECT  56.304 7.379 56.712 11.125 ;
     RECT  45.6 8.003 45.912 11.173 ;
     RECT  12 10.213 12.072 11.269 ;
     RECT  7.2 10.693 8.112 11.365 ;
     RECT  28.224 9.779 28.248 11.459 ;
     RECT  15.552 10.213 15.576 11.651 ;
     RECT  6.912 11.365 8.112 11.941 ;
     RECT  32.112 10.789 32.136 12.227 ;
     RECT  29.4 4.595 29.712 12.229 ;
     RECT  11.904 11.269 12.072 12.515 ;
     RECT  17.904 6.565 19.944 12.517 ;
     RECT  42.192 11.413 42.216 12.755 ;
     RECT  34.8 2.151 35.112 12.757 ;
     RECT  39.6 7.667 40.512 12.803 ;
     RECT  33.648 6.659 33.672 12.805 ;
     RECT  34.8 12.757 36.024 12.805 ;
     RECT  33.648 12.805 36.024 12.851 ;
     RECT  12.048 12.515 12.072 12.853 ;
     RECT  24 6.899 24.312 12.853 ;
     RECT  13.2 6.035 13.512 13.045 ;
     RECT  6.72 11.941 8.112 13.283 ;
     RECT  17.088 12.517 19.944 13.331 ;
     RECT  29.088 12.229 29.712 13.379 ;
     RECT  23.28 12.853 24.312 13.571 ;
     RECT  6.912 13.283 8.112 13.573 ;
     RECT  9.36 8.485 9.624 13.573 ;
     RECT  21.888 4.885 21.912 13.573 ;
     RECT  58.704 11.413 58.728 13.619 ;
     RECT  26.736 13.333 26.76 13.621 ;
     RECT  13.2 13.045 14.472 13.667 ;
     RECT  26.4 13.621 26.76 13.667 ;
     RECT  45.6 11.173 46.824 13.715 ;
     RECT  5.232 8.149 5.256 14.197 ;
     RECT  55.872 11.125 56.712 14.197 ;
     RECT  55.872 14.197 56.808 14.243 ;
     RECT  6.912 13.573 9.624 14.387 ;
     RECT  26.4 13.667 26.424 14.387 ;
     RECT  9.36 14.387 9.624 14.485 ;
     RECT  10.848 14.293 10.872 14.485 ;
     RECT  9.36 14.485 10.872 14.627 ;
     RECT  12.048 12.853 12.168 14.917 ;
     RECT  13.2 13.667 13.512 14.917 ;
     RECT  16.464 14.821 16.488 14.963 ;
     RECT  40.2 12.803 40.512 15.301 ;
     RECT  9.36 14.627 10.248 15.491 ;
     RECT  5.232 14.197 5.832 15.493 ;
     RECT  45.6 13.715 45.912 15.493 ;
     RECT  15.36 14.773 15.384 15.685 ;
     RECT  14.832 15.685 15.384 15.731 ;
     RECT  56.4 14.243 56.808 15.877 ;
     RECT  14.832 15.731 14.856 16.019 ;
     RECT  40.2 15.301 41.112 16.019 ;
     RECT  45.6 15.493 46.152 16.019 ;
     RECT  60.72 15.349 60.744 16.019 ;
     RECT  48.432 15.493 48.456 16.165 ;
     RECT  54.192 16.069 54.216 16.211 ;
     RECT  4.368 15.493 5.832 16.259 ;
     RECT  52.848 13.621 52.872 16.261 ;
     RECT  5.376 16.259 5.832 16.405 ;
     RECT  6.912 14.387 8.112 16.405 ;
     RECT  45.6 16.019 45.912 16.501 ;
     RECT  5.376 16.405 8.112 16.549 ;
     RECT  9.36 15.491 9.912 16.549 ;
     RECT  17.904 13.331 19.944 16.691 ;
     RECT  48.288 16.165 48.456 16.981 ;
     RECT  29.4 13.379 29.712 17.077 ;
     RECT  5.376 16.549 9.912 17.123 ;
     RECT  48.288 16.981 49.032 17.123 ;
     RECT  52.8 16.261 52.872 17.171 ;
     RECT  48.288 17.123 48.312 17.219 ;
     RECT  4.368 16.259 4.392 17.459 ;
     RECT  12.048 14.917 13.512 17.605 ;
     RECT  14.832 17.077 14.856 17.605 ;
     RECT  44.64 16.501 45.912 17.605 ;
     RECT  47.28 17.077 47.304 17.605 ;
     RECT  12.048 17.605 14.856 17.699 ;
     RECT  44.64 17.605 47.304 17.699 ;
     RECT  26.064 17.413 26.088 18.131 ;
     RECT  52.848 17.171 52.872 18.131 ;
     RECT  37.2 16.981 37.224 18.179 ;
     RECT  5.376 17.123 9.624 18.181 ;
     RECT  59.04 17.029 59.064 18.659 ;
     RECT  21.888 13.573 22.536 18.707 ;
     RECT  24 13.571 24.312 18.757 ;
     RECT  12.048 17.699 14.136 18.899 ;
     RECT  5.184 18.181 9.72 18.997 ;
     RECT  44.64 17.699 46.728 19.045 ;
     RECT  33.12 18.997 33.144 19.139 ;
     RECT  18.48 16.691 19.944 19.283 ;
     RECT  38.592 18.469 38.616 19.669 ;
     RECT  41.616 19.093 41.64 19.669 ;
     RECT  38.592 19.669 38.76 19.763 ;
     RECT  4.56 18.997 9.72 19.811 ;
     RECT  38.736 19.763 38.76 19.811 ;
     RECT  4.56 19.811 9.624 20.051 ;
     RECT  5.136 20.051 9.624 20.147 ;
     RECT  34.128 12.851 36.024 20.149 ;
     RECT  34.128 20.149 36.984 20.195 ;
     RECT  56.4 15.877 57.576 20.531 ;
     RECT  34.704 20.195 36.984 20.579 ;
     RECT  44.16 19.045 46.728 20.579 ;
     RECT  28.56 17.077 29.712 20.627 ;
     RECT  41.616 19.669 42.6 20.723 ;
     RECT  12.048 18.899 13.512 20.819 ;
     RECT  24 18.757 24.792 20.867 ;
     RECT  34.704 20.579 36.024 21.011 ;
     RECT  12.048 20.819 12.168 21.013 ;
     RECT  5.184 20.147 9.624 21.061 ;
     RECT  51 10.403 51.312 21.061 ;
     RECT  5.184 21.061 9.672 21.205 ;
     RECT  44.16 20.579 44.184 21.253 ;
     RECT  5.184 21.205 9.96 21.635 ;
     RECT  26.112 18.181 26.136 21.637 ;
     RECT  26.112 21.637 26.808 21.923 ;
     RECT  50.112 21.061 51.312 22.163 ;
     RECT  29.4 20.627 29.712 22.165 ;
     RECT  40.2 16.019 40.512 22.213 ;
     RECT  42.144 20.723 42.6 22.213 ;
     RECT  11.712 21.013 12.168 22.741 ;
     RECT  21.888 18.707 21.912 22.741 ;
     RECT  34.8 21.011 36.024 22.787 ;
     RECT  5.184 21.635 9.672 22.789 ;
     RECT  11.376 22.741 12.168 22.931 ;
     RECT  11.376 22.931 12.072 23.269 ;
     RECT  15.696 20.965 15.72 23.317 ;
     RECT  26.112 21.923 26.136 23.317 ;
     RECT  50.4 22.163 51.312 23.317 ;
     RECT  21.168 22.741 21.912 23.411 ;
     RECT  31.968 22.789 31.992 23.411 ;
     RECT  49.344 22.741 49.368 23.411 ;
     RECT  50.4 23.317 51.576 23.411 ;
     RECT  28.656 22.165 29.712 23.843 ;
     RECT  39.264 22.213 40.512 23.891 ;
     RECT  11.088 23.269 12.072 23.893 ;
     RECT  45.6 20.579 46.728 23.941 ;
     RECT  43.776 21.253 44.184 24.131 ;
     RECT  51 23.411 51.576 24.371 ;
     RECT  37.056 23.317 37.08 24.419 ;
     RECT  15.36 23.317 15.72 24.469 ;
     RECT  24 20.867 24.312 24.469 ;
     RECT  54.048 23.893 54.072 24.469 ;
     RECT  5.184 22.789 9.624 24.563 ;
     RECT  26.112 23.317 27.048 24.611 ;
     RECT  30.72 23.365 30.744 24.611 ;
     RECT  41.856 22.213 42.6 24.611 ;
     RECT  26.112 24.611 26.136 24.659 ;
     RECT  10.8 23.893 12.072 24.803 ;
     RECT  5.184 24.563 9.048 24.805 ;
     RECT  51 24.371 51.312 24.949 ;
     RECT  15.216 24.469 15.72 25.045 ;
     RECT  48.432 24.229 48.456 25.091 ;
     RECT  50.736 24.949 51.312 25.091 ;
     RECT  11.088 24.803 12.072 25.139 ;
     RECT  34.8 22.787 35.592 25.139 ;
     RECT  56.4 20.531 57.48 25.139 ;
     RECT  45.504 23.941 46.728 25.187 ;
     RECT  56.4 25.139 57.144 25.187 ;
     RECT  24 24.469 24.552 25.235 ;
     RECT  5.136 24.805 9.048 25.331 ;
     RECT  11.088 25.139 11.736 25.427 ;
     RECT  5.136 25.331 5.208 25.907 ;
     RECT  5.136 25.907 5.16 26.243 ;
     RECT  34.8 25.139 35.448 26.339 ;
     RECT  45.6 25.187 46.728 26.437 ;
     RECT  45.6 26.437 46.776 26.675 ;
     RECT  42.576 24.611 42.6 26.723 ;
     RECT  33.024 26.293 33.048 26.819 ;
     RECT  37.2 26.053 37.224 26.867 ;
     RECT  43.824 24.131 44.184 26.867 ;
     RECT  24 25.235 24.312 26.917 ;
     RECT  48.192 25.573 48.216 27.059 ;
     RECT  18.6 19.283 19.944 27.205 ;
     RECT  40.2 23.891 40.512 27.301 ;
     RECT  45.6 26.675 46.728 27.637 ;
     RECT  15.12 25.045 15.72 27.781 ;
     RECT  6.72 25.331 9.048 27.877 ;
     RECT  34.8 26.339 35.112 27.877 ;
     RECT  0.144 27.733 0.168 27.923 ;
     RECT  24 26.917 24.6 27.923 ;
     RECT  45.6 27.637 46.776 27.923 ;
     RECT  37.248 27.301 37.272 28.499 ;
     RECT  13.2 20.819 13.512 28.501 ;
     RECT  25.824 27.877 25.848 28.643 ;
     RECT  13.104 28.501 13.512 28.933 ;
     RECT  14.64 27.781 15.72 28.933 ;
     RECT  11.712 25.427 11.736 29.029 ;
     RECT  34.8 27.877 35.928 29.317 ;
     RECT  54.048 24.469 54.312 29.365 ;
     RECT  34.8 29.317 36.168 29.459 ;
     RECT  40.08 27.301 40.512 29.605 ;
     RECT  11.424 29.029 11.736 29.699 ;
     RECT  18.6 27.205 20.52 29.941 ;
     RECT  21.888 23.411 21.912 29.941 ;
     RECT  4.992 29.365 5.016 30.035 ;
     RECT  39.456 29.605 40.512 30.083 ;
     RECT  17.28 24.805 17.304 30.421 ;
     RECT  18.6 29.941 21.912 30.421 ;
     RECT  17.28 30.421 21.912 30.611 ;
     RECT  60.432 30.181 60.456 30.755 ;
     RECT  30.72 30.661 30.744 30.803 ;
     RECT  58.128 30.757 58.152 30.853 ;
     RECT  57.888 30.853 58.152 30.899 ;
     RECT  21.168 30.611 21.912 30.995 ;
     RECT  51 25.091 51.312 30.997 ;
     RECT  54.048 29.365 55.08 31.043 ;
     RECT  13.104 28.933 15.72 31.283 ;
     RECT  51 30.997 51.864 31.381 ;
     RECT  49.392 30.709 49.416 31.427 ;
     RECT  6 27.877 9.048 31.475 ;
     RECT  17.28 30.611 19.992 31.475 ;
     RECT  18.192 31.475 19.992 31.667 ;
     RECT  2.4 2.151 2.712 31.765 ;
     RECT  6 31.475 6.024 31.765 ;
     RECT  34.8 29.459 35.112 31.765 ;
     RECT  36.144 29.459 36.168 31.765 ;
     RECT  51 31.381 52.104 31.955 ;
     RECT  13.2 31.283 15.72 32.387 ;
     RECT  2.4 31.765 3.432 32.483 ;
     RECT  5.04 31.765 6.024 32.531 ;
     RECT  34.8 31.765 36.168 32.531 ;
     RECT  54.048 31.043 54.12 32.531 ;
     RECT  37.968 30.037 37.992 32.627 ;
     RECT  33.456 30.709 33.48 32.771 ;
     RECT  44.16 26.867 44.184 32.917 ;
     RECT  18.6 31.667 19.992 32.965 ;
     RECT  11.712 29.699 11.736 33.013 ;
     RECT  13.2 32.387 14.328 33.013 ;
     RECT  57.888 30.899 57.912 33.013 ;
     RECT  11.712 33.013 14.328 33.683 ;
     RECT  11.712 33.683 13.512 33.827 ;
     RECT  57.888 33.013 58.68 33.827 ;
     RECT  6 32.531 6.024 33.971 ;
     RECT  24 27.923 24.312 34.069 ;
     RECT  61.8 2.151 62.112 34.165 ;
     RECT  44.16 32.917 44.28 34.213 ;
     RECT  18.6 32.965 20.472 34.259 ;
     RECT  44.16 34.213 44.376 34.259 ;
     RECT  18.6 34.259 19.656 34.403 ;
     RECT  29.4 23.843 29.712 34.501 ;
     RECT  40.08 30.083 40.512 34.741 ;
     RECT  11.712 33.827 11.736 34.835 ;
     RECT  57.888 33.827 58.248 34.835 ;
     RECT  18.6 34.403 19.032 34.931 ;
     RECT  39.552 34.741 40.512 34.931 ;
     RECT  61.68 34.165 62.112 34.933 ;
     RECT  15.696 32.387 15.72 35.123 ;
     RECT  21.888 30.995 21.912 35.269 ;
     RECT  29.4 34.501 29.832 35.269 ;
     RECT  44.256 34.259 44.376 35.269 ;
     RECT  45.6 27.923 46.728 35.269 ;
     RECT  4.896 33.541 4.92 35.315 ;
     RECT  34.8 32.531 35.112 35.317 ;
     RECT  36.144 32.531 36.168 35.317 ;
     RECT  44.256 35.269 46.728 35.363 ;
     RECT  21.6 35.269 21.912 35.411 ;
     RECT  39.84 34.931 40.512 35.843 ;
     RECT  44.352 35.363 46.728 35.845 ;
     RECT  44.352 35.845 46.824 35.939 ;
     RECT  61.632 34.933 62.112 36.035 ;
     RECT  24 34.069 24.408 36.325 ;
     RECT  7.296 31.475 9.048 36.373 ;
     RECT  10.224 33.589 10.248 36.373 ;
     RECT  7.296 36.373 10.248 36.419 ;
     RECT  44.352 35.939 44.376 36.515 ;
     RECT  54.048 32.531 54.072 36.515 ;
     RECT  49.392 32.821 49.416 36.661 ;
     RECT  39.888 35.843 40.512 36.899 ;
     RECT  45.6 35.939 46.824 36.901 ;
     RECT  52.608 36.661 52.632 36.901 ;
     RECT  45.6 36.901 47.352 36.949 ;
     RECT  7.296 36.419 9.288 36.997 ;
     RECT  51 31.955 51.528 36.997 ;
     RECT  52.608 36.901 53.256 36.997 ;
     RECT  45.6 36.949 48.312 37.045 ;
     RECT  49.392 36.661 49.56 37.045 ;
     RECT  45.6 37.045 49.56 37.091 ;
     RECT  42.384 35.845 42.408 37.573 ;
     RECT  29.4 35.269 30.264 37.619 ;
     RECT  41.568 37.573 42.408 37.619 ;
     RECT  37.824 36.949 37.848 37.811 ;
     RECT  7.152 36.997 9.288 38.099 ;
     RECT  34.8 35.317 36.168 38.099 ;
     RECT  13.2 33.827 13.512 38.101 ;
     RECT  51 36.997 53.256 38.149 ;
     RECT  21.888 35.411 21.912 38.197 ;
     RECT  51 38.149 53.352 38.197 ;
     RECT  7.296 38.099 9.288 38.243 ;
     RECT  34.8 38.099 35.784 38.243 ;
     RECT  47.328 37.091 49.56 38.243 ;
     RECT  7.296 38.243 9.048 38.387 ;
     RECT  27.744 37.573 27.768 38.435 ;
     RECT  47.52 38.243 49.56 38.485 ;
     RECT  50.736 38.197 53.352 38.485 ;
     RECT  32.448 33.685 32.472 38.675 ;
     RECT  16.08 36.469 16.104 38.819 ;
     RECT  31.056 38.005 31.08 38.819 ;
     RECT  47.52 38.485 53.352 38.819 ;
     RECT  24 36.325 24.456 38.963 ;
     RECT  7.536 38.387 9.048 39.251 ;
     RECT  45.6 37.091 45.912 39.301 ;
     RECT  47.52 38.819 48.408 39.395 ;
     RECT  47.52 39.395 47.928 39.539 ;
     RECT  61.68 36.035 62.112 39.539 ;
     RECT  13.104 38.101 13.512 39.635 ;
     RECT  44.64 39.301 46.44 39.637 ;
     RECT  47.52 39.539 47.88 39.637 ;
     RECT  18.6 34.931 18.912 39.781 ;
     RECT  49.44 38.819 53.352 39.875 ;
     RECT  50.832 39.875 53.352 40.019 ;
     RECT  50.832 40.019 51.312 40.067 ;
     RECT  29.4 37.619 29.832 40.117 ;
     RECT  34.8 38.243 35.736 40.165 ;
     RECT  56.4 25.187 56.712 40.405 ;
     RECT  57.888 34.835 57.912 40.405 ;
     RECT  43.296 40.021 43.32 40.499 ;
     RECT  29.04 40.117 29.832 40.597 ;
     RECT  41.568 37.619 41.592 40.835 ;
     RECT  44.64 39.637 47.88 40.835 ;
     RECT  40.2 36.899 40.512 40.837 ;
     RECT  50.88 40.067 51.312 41.171 ;
     RECT  30.816 39.541 30.84 41.363 ;
     RECT  40.2 40.837 41.496 41.413 ;
     RECT  24 38.963 24.408 41.461 ;
     RECT  56.4 40.405 57.912 41.461 ;
     RECT  51 41.171 51.312 41.557 ;
     RECT  52.416 40.019 53.352 41.557 ;
     RECT  28.752 40.597 29.832 41.653 ;
     RECT  21.36 38.197 21.912 41.699 ;
     RECT  49.44 39.875 49.56 41.795 ;
     RECT  51 41.557 53.352 41.795 ;
     RECT  53.184 41.795 53.352 41.843 ;
     RECT  18.24 39.781 18.912 41.939 ;
     RECT  28.752 41.653 30.216 41.939 ;
     RECT  45.6 40.835 47.88 41.987 ;
     RECT  49.536 41.795 49.56 42.035 ;
     RECT  55.44 41.461 57.912 42.133 ;
     RECT  55.44 42.133 58.248 42.179 ;
     RECT  47.856 41.987 47.88 42.227 ;
     RECT  55.44 42.179 57.144 42.227 ;
     RECT  53.28 41.843 53.352 42.275 ;
     RECT  34.8 40.165 36.12 42.467 ;
     RECT  39.216 41.413 41.496 42.467 ;
     RECT  51 41.795 51.864 42.469 ;
     RECT  55.44 42.227 56.712 42.515 ;
     RECT  28.752 41.939 29.712 42.563 ;
     RECT  39.936 42.467 41.496 42.803 ;
     RECT  45.6 41.987 46.44 42.803 ;
     RECT  25.728 40.933 25.752 42.851 ;
     RECT  7.68 39.251 9.048 42.853 ;
     RECT  39.936 42.803 40.512 42.899 ;
     RECT  55.824 42.515 56.712 43.043 ;
     RECT  44.304 41.989 44.328 43.091 ;
     RECT  7.68 42.853 9.096 43.141 ;
     RECT  10.128 42.997 10.152 43.141 ;
     RECT  23.376 41.461 24.408 43.285 ;
     RECT  50.688 42.469 51.864 43.285 ;
     RECT  58.224 42.179 58.248 43.285 ;
     RECT  18.48 41.939 18.912 43.379 ;
     RECT  50.688 43.285 52.104 43.621 ;
     RECT  53.28 42.275 53.304 43.621 ;
     RECT  50.688 43.621 53.304 43.763 ;
     RECT  57.84 43.285 58.248 43.763 ;
     RECT  13.2 39.635 13.512 43.861 ;
     RECT  21.456 41.699 21.912 43.861 ;
     RECT  4.656 39.637 4.68 43.955 ;
     RECT  15.264 42.181 15.288 43.955 ;
     RECT  23.376 43.285 24.504 43.955 ;
     RECT  57.84 43.763 58.152 43.955 ;
     RECT  13.2 43.861 14.136 44.101 ;
     RECT  50.688 43.763 52.104 44.339 ;
     RECT  12.432 44.101 14.136 44.341 ;
     RECT  34.8 42.467 35.736 44.341 ;
     RECT  7.68 43.141 10.152 44.387 ;
     RECT  39.984 42.899 40.512 44.437 ;
     RECT  53.28 43.763 53.304 44.627 ;
     RECT  49.2 43.861 49.224 44.723 ;
     RECT  55.872 43.043 56.712 44.725 ;
     RECT  11.712 44.341 14.136 44.867 ;
     RECT  55.152 44.725 56.712 44.867 ;
     RECT  21.456 43.861 22.248 44.915 ;
     RECT  7.68 44.387 9.24 45.059 ;
     RECT  39.984 44.437 40.968 45.059 ;
     RECT  29.28 42.563 29.712 45.155 ;
     RECT  40.2 45.059 40.968 45.395 ;
     RECT  34.368 44.341 35.736 45.491 ;
     RECT  50.688 44.339 51.912 45.493 ;
     RECT  58.08 43.955 58.152 45.683 ;
     RECT  7.68 45.059 8.28 45.731 ;
     RECT  6.24 43.909 6.264 45.923 ;
     RECT  14.832 44.917 14.856 46.019 ;
     RECT  55.68 44.867 56.712 46.117 ;
     RECT  29.4 45.155 29.712 46.165 ;
     RECT  7.68 45.731 8.112 46.211 ;
     RECT  49.056 45.541 49.08 46.211 ;
     RECT  50.112 45.493 51.912 46.259 ;
     RECT  42.912 44.773 42.936 46.501 ;
     RECT  9.648 45.973 9.672 46.595 ;
     RECT  51 46.259 51.912 46.595 ;
     RECT  37.344 46.117 37.368 46.787 ;
     RECT  11.712 44.867 13.512 46.835 ;
     RECT  22.224 44.915 22.248 46.835 ;
     RECT  7.8 46.211 8.112 46.885 ;
     RECT  42 46.501 42.936 47.123 ;
     RECT  29.04 46.165 29.712 47.125 ;
     RECT  24 43.955 24.504 47.173 ;
     RECT  34.8 45.491 35.736 47.219 ;
     RECT  27.504 45.781 27.528 47.221 ;
     RECT  29.04 47.125 29.832 47.221 ;
     RECT  27.504 47.221 29.832 47.267 ;
     RECT  7.8 46.885 9.096 47.269 ;
     RECT  42 47.123 42.84 47.461 ;
     RECT  55.44 46.117 56.712 47.603 ;
     RECT  49.008 47.413 49.032 47.651 ;
     RECT  21.168 46.789 21.192 47.939 ;
     RECT  41.952 47.461 42.84 48.467 ;
     RECT  4.464 46.453 4.488 48.515 ;
     RECT  42.816 48.467 42.84 48.515 ;
     RECT  44.496 47.221 44.52 48.515 ;
     RECT  58.128 45.683 58.152 48.709 ;
     RECT  58.128 48.709 58.728 48.851 ;
     RECT  6.864 47.269 9.096 49.043 ;
     RECT  14.688 48.181 14.712 49.091 ;
     RECT  34.8 47.219 35.112 49.477 ;
     RECT  11.712 46.835 11.736 49.619 ;
     RECT  58.128 48.851 58.152 49.763 ;
     RECT  24 47.173 25.272 49.907 ;
     RECT  6.864 49.043 9.048 50.051 ;
     RECT  40.2 45.395 40.512 50.053 ;
     RECT  34.416 49.477 35.112 50.723 ;
     RECT  7.056 50.051 9.048 50.771 ;
     RECT  14.64 49.909 14.664 50.771 ;
     RECT  11.04 50.101 11.064 50.819 ;
     RECT  28.464 47.267 29.712 51.155 ;
     RECT  40.2 50.053 40.872 51.299 ;
     RECT  58.32 50.101 58.824 51.301 ;
     RECT  61.8 39.539 62.112 51.301 ;
     RECT  7.056 50.771 8.112 51.347 ;
     RECT  47.424 49.909 47.448 51.347 ;
     RECT  58.32 51.301 59.208 51.781 ;
     RECT  60.912 51.301 62.112 51.781 ;
     RECT  58.32 51.781 59.784 51.829 ;
     RECT  60.816 51.781 62.112 51.829 ;
     RECT  2.4 32.483 2.712 51.849 ;
     RECT  7.8 51.347 8.112 51.849 ;
     RECT  13.2 46.835 13.512 51.849 ;
     RECT  18.6 43.379 18.912 51.849 ;
     RECT  24 49.907 24.312 51.849 ;
     RECT  29.4 51.155 29.712 51.849 ;
     RECT  34.8 50.723 35.112 51.849 ;
     RECT  40.2 51.299 40.512 51.849 ;
     RECT  45.6 42.803 45.912 51.849 ;
     RECT  51 46.595 51.312 51.849 ;
     RECT  56.4 47.603 56.712 51.849 ;
     RECT  58.32 51.829 62.112 51.849 ;
     RECT  2.4 51.849 2.52 51.863 ;
     RECT  7.8 51.849 7.92 51.863 ;
     RECT  13.2 51.849 13.32 51.863 ;
     RECT  18.6 51.849 18.72 51.863 ;
     RECT  24 51.849 24.12 51.863 ;
     RECT  29.4 51.849 29.52 51.863 ;
     RECT  34.8 51.849 34.92 51.863 ;
     RECT  40.2 51.849 40.32 51.863 ;
     RECT  45.6 51.849 45.72 51.863 ;
     RECT  51 51.849 51.12 51.863 ;
     RECT  56.4 51.849 56.52 51.863 ;
     RECT  58.32 51.849 61.92 51.863 ;
     RECT  58.32 51.863 60.936 52.453 ;
     RECT  58.224 52.453 60.936 53.029 ;
     RECT  58.128 53.029 60.936 53.845 ;
     RECT  58.128 53.845 61.032 53.968 ;
  END
END ot_s81ph_native_sel_hist_bank
END LIBRARY
